# Autogenerated file; please don't edit
# date: 2023-12-21 15:24:16.315777

VERSION 5.8 ;

SITE IOLibSite
  CLASS PAD ;
  SYMMETRY R90 ;
  SIZE 1.00 BY 180.00 ;
END IOLibSite

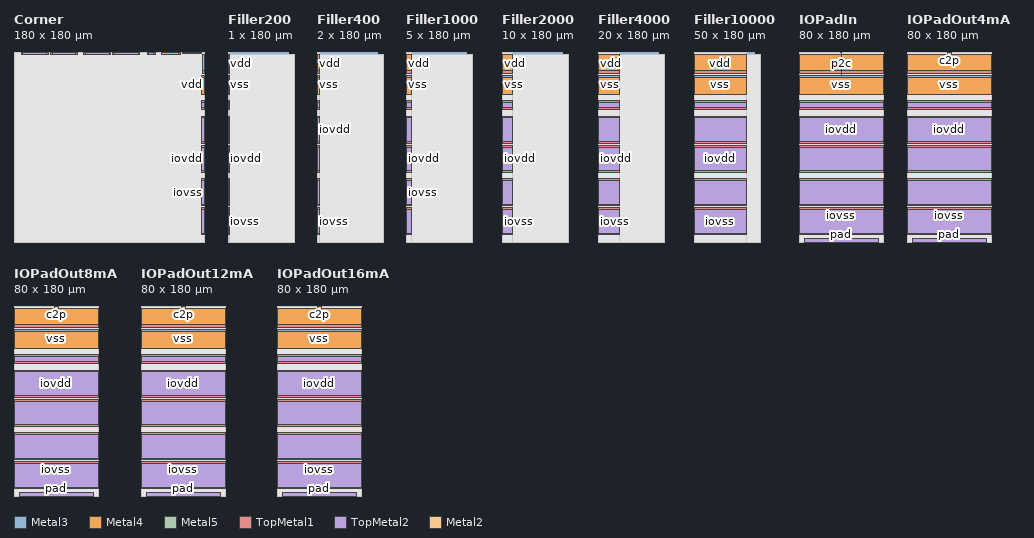
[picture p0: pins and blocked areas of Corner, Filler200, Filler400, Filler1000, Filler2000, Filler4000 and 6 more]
MACRO Corner
  CLASS PAD SPACER ;
  ORIGIN 180.000 0.000 ;
  FOREIGN Corner -180.000 0.000 ;
  SIZE 180.000 BY 180.000 ;
  SYMMETRY X Y R90 ;
  SITE IOLibSite ;
  PIN iovdd
    DIRECTION INOUT ;
    USE POWER ;
    PORT
      LAYER Metal3 ;
        RECT -2.000 66.000 0.000 91.500 ;
    END
    PORT
      LAYER Metal3 ;
        RECT -86.500 178.000 -61.000 180.000 ;
    END
    PORT
      LAYER Metal3 ;
        RECT -114.000 178.000 -88.500 180.000 ;
    END
    PORT
      LAYER Metal3 ;
        RECT -2.000 93.500 0.000 119.000 ;
    END
    PORT
      LAYER Metal4 ;
        RECT -2.000 66.000 0.000 91.500 ;
    END
    PORT
      LAYER Metal4 ;
        RECT -86.500 178.000 -61.000 180.000 ;
    END
    PORT
      LAYER Metal4 ;
        RECT -114.000 178.000 -88.500 180.000 ;
    END
    PORT
      LAYER Metal4 ;
        RECT -2.000 93.500 0.000 119.000 ;
    END
    PORT
      LAYER Metal5 ;
        RECT -2.000 66.000 0.000 91.500 ;
    END
    PORT
      LAYER Metal5 ;
        RECT -86.500 178.000 -61.000 180.000 ;
    END
    PORT
      LAYER Metal5 ;
        RECT -114.000 178.000 -88.500 180.000 ;
    END
    PORT
      LAYER Metal5 ;
        RECT -2.000 93.500 0.000 119.000 ;
    END
    PORT
      LAYER TopMetal1 ;
        RECT -2.000 66.000 0.000 91.500 ;
    END
    PORT
      LAYER TopMetal1 ;
        RECT -86.500 178.000 -61.000 180.000 ;
    END
    PORT
      LAYER TopMetal1 ;
        RECT -114.000 178.000 -88.500 180.000 ;
    END
    PORT
      LAYER TopMetal1 ;
        RECT -2.000 93.500 0.000 119.000 ;
    END
    PORT
      LAYER TopMetal2 ;
        RECT -112.500 178.000 -90.000 180.000 ;
    END
    PORT
      LAYER TopMetal2 ;
        RECT -2.000 67.500 0.000 90.000 ;
    END
    PORT
      LAYER TopMetal2 ;
        RECT -85.000 178.000 -62.500 180.000 ;
    END
    PORT
      LAYER TopMetal2 ;
        RECT -2.000 95.000 0.000 117.500 ;
    END
  END iovdd
  PIN iovss
    DIRECTION INOUT ;
    USE GROUND ;
    PORT
      LAYER Metal3 ;
        RECT -2.000 34.500 0.000 60.000 ;
    END
    PORT
      LAYER Metal3 ;
        RECT -173.000 178.000 -147.500 180.000 ;
    END
    PORT
      LAYER Metal3 ;
        RECT -2.000 126.000 0.000 134.000 ;
    END
    PORT
      LAYER Metal3 ;
        RECT -54.000 178.000 -46.000 180.000 ;
    END
    PORT
      LAYER Metal3 ;
        RECT -145.500 178.000 -120.000 180.000 ;
    END
    PORT
      LAYER Metal3 ;
        RECT -2.000 7.000 0.000 32.500 ;
    END
    PORT
      LAYER Metal4 ;
        RECT -2.000 34.500 0.000 60.000 ;
    END
    PORT
      LAYER Metal4 ;
        RECT -173.000 178.000 -147.500 180.000 ;
    END
    PORT
      LAYER Metal4 ;
        RECT -2.000 126.000 0.000 134.000 ;
    END
    PORT
      LAYER Metal4 ;
        RECT -54.000 178.000 -46.000 180.000 ;
    END
    PORT
      LAYER Metal4 ;
        RECT -145.500 178.000 -120.000 180.000 ;
    END
    PORT
      LAYER Metal4 ;
        RECT -2.000 7.000 0.000 32.500 ;
    END
    PORT
      LAYER Metal5 ;
        RECT -2.000 34.500 0.000 60.000 ;
    END
    PORT
      LAYER Metal5 ;
        RECT -173.000 178.000 -147.500 180.000 ;
    END
    PORT
      LAYER Metal5 ;
        RECT -2.000 126.000 0.000 134.000 ;
    END
    PORT
      LAYER Metal5 ;
        RECT -54.000 178.000 -46.000 180.000 ;
    END
    PORT
      LAYER Metal5 ;
        RECT -145.500 178.000 -120.000 180.000 ;
    END
    PORT
      LAYER Metal5 ;
        RECT -2.000 7.000 0.000 32.500 ;
    END
    PORT
      LAYER TopMetal1 ;
        RECT -2.000 34.500 0.000 60.000 ;
    END
    PORT
      LAYER TopMetal1 ;
        RECT -173.000 178.000 -147.500 180.000 ;
    END
    PORT
      LAYER TopMetal1 ;
        RECT -2.000 126.000 0.000 134.000 ;
    END
    PORT
      LAYER TopMetal1 ;
        RECT -54.000 178.000 -46.000 180.000 ;
    END
    PORT
      LAYER TopMetal1 ;
        RECT -145.500 178.000 -120.000 180.000 ;
    END
    PORT
      LAYER TopMetal1 ;
        RECT -2.000 7.000 0.000 32.500 ;
    END
    PORT
      LAYER TopMetal2 ;
        RECT -2.000 127.500 0.000 132.500 ;
    END
    PORT
      LAYER TopMetal2 ;
        RECT -2.000 36.000 0.000 58.500 ;
    END
    PORT
      LAYER TopMetal2 ;
        RECT -171.500 178.000 -149.000 180.000 ;
    END
    PORT
      LAYER TopMetal2 ;
        RECT -2.000 8.500 0.000 31.000 ;
    END
    PORT
      LAYER TopMetal2 ;
        RECT -144.000 178.000 -121.500 180.000 ;
    END
    PORT
      LAYER TopMetal2 ;
        RECT -52.500 178.000 -47.500 180.000 ;
    END
  END iovss
  PIN vdd
    DIRECTION INOUT ;
    USE POWER ;
    PORT
      LAYER Metal3 ;
        RECT -20.000 178.590 -2.000 180.000 ;
    END
    PORT
      LAYER Metal3 ;
        RECT -1.410 160.000 0.000 178.000 ;
    END
    PORT
      LAYER Metal4 ;
        RECT -2.000 140.000 0.000 155.800 ;
    END
    PORT
      LAYER Metal4 ;
        RECT -40.000 178.000 -24.200 180.000 ;
    END
    PORT
      LAYER Metal5 ;
        RECT -2.000 140.000 0.000 158.000 ;
    END
    PORT
      LAYER Metal5 ;
        RECT -40.000 178.000 -22.000 180.000 ;
    END
    PORT
      LAYER TopMetal1 ;
        RECT -2.000 140.000 0.000 158.000 ;
    END
    PORT
      LAYER TopMetal1 ;
        RECT -40.000 178.000 -22.000 180.000 ;
    END
  END vdd
  PIN vss
    DIRECTION INOUT ;
    USE GROUND ;
    PORT
      LAYER Metal3 ;
        RECT -2.000 140.000 0.000 158.000 ;
    END
    PORT
      LAYER Metal3 ;
        RECT -40.000 178.000 -22.000 180.000 ;
    END
    PORT
      LAYER Metal4 ;
        RECT -1.410 162.200 0.000 178.000 ;
    END
    PORT
      LAYER Metal4 ;
        RECT -17.800 178.590 -2.000 180.000 ;
    END
    PORT
      LAYER Metal5 ;
        RECT -20.000 178.590 -2.000 180.000 ;
    END
    PORT
      LAYER Metal5 ;
        RECT -1.410 160.000 0.000 178.000 ;
    END
    PORT
      LAYER TopMetal1 ;
        RECT -20.000 178.590 -2.000 180.000 ;
    END
    PORT
      LAYER TopMetal1 ;
        RECT -1.410 160.000 0.000 178.000 ;
    END
  END vss
  OBS
    LAYER Metal1 ;
      RECT -180.000 0.000 0.000 180.000 ;
    LAYER Metal2 ;
      RECT -180.000 0.000 0.000 180.000 ;
    LAYER Metal3 ;
      RECT -180.000 0.000 0.000 180.000 ;
    LAYER Metal4 ;
      RECT -180.000 0.000 0.000 180.000 ;
    LAYER Metal5 ;
      RECT -180.000 0.000 0.000 180.000 ;
    LAYER TopMetal1 ;
      RECT -180.000 0.000 0.000 180.000 ;
    LAYER TopMetal2 ;
      RECT -180.000 0.000 0.000 180.000 ;
    LAYER Via1 ;
      RECT -180.000 0.000 0.000 180.000 ;
    LAYER Via2 ;
      RECT -180.000 0.000 0.000 180.000 ;
  END
END Corner

MACRO Filler200
  CLASS PAD SPACER ;
  ORIGIN 0.000 0.000 ;
  FOREIGN Filler200 0.000 0.000 ;
  SIZE 1.000 BY 180.000 ;
  SYMMETRY X Y R90 ;
  SITE IOLibSite ;
  PIN iovdd
    DIRECTION INOUT ;
    USE POWER ;
    PORT
      LAYER Metal3 ;
        RECT 0.000 66.000 1.000 91.500 ;
    END
    PORT
      LAYER Metal3 ;
        RECT 0.000 93.500 1.000 119.000 ;
    END
    PORT
      LAYER Metal4 ;
        RECT 0.000 66.000 1.000 91.500 ;
    END
    PORT
      LAYER Metal4 ;
        RECT 0.000 93.500 1.000 119.000 ;
    END
    PORT
      LAYER Metal5 ;
        RECT 0.000 66.000 1.000 91.500 ;
    END
    PORT
      LAYER Metal5 ;
        RECT 0.000 93.500 1.000 119.000 ;
    END
    PORT
      LAYER TopMetal1 ;
        RECT 0.000 66.000 1.000 91.500 ;
    END
    PORT
      LAYER TopMetal1 ;
        RECT 0.000 93.500 1.000 119.000 ;
    END
    PORT
      LAYER TopMetal2 ;
        RECT 0.000 95.000 1.000 117.500 ;
    END
    PORT
      LAYER TopMetal2 ;
        RECT 0.000 67.500 1.000 90.000 ;
    END
  END iovdd
  PIN iovss
    DIRECTION INOUT ;
    USE GROUND ;
    PORT
      LAYER Metal3 ;
        RECT 0.000 7.000 1.000 32.500 ;
    END
    PORT
      LAYER Metal3 ;
        RECT 0.000 126.000 1.000 134.000 ;
    END
    PORT
      LAYER Metal3 ;
        RECT 0.000 34.500 1.000 60.000 ;
    END
    PORT
      LAYER Metal4 ;
        RECT 0.000 7.000 1.000 32.500 ;
    END
    PORT
      LAYER Metal4 ;
        RECT 0.000 126.000 1.000 134.000 ;
    END
    PORT
      LAYER Metal4 ;
        RECT 0.000 34.500 1.000 60.000 ;
    END
    PORT
      LAYER Metal5 ;
        RECT 0.000 7.000 1.000 32.500 ;
    END
    PORT
      LAYER Metal5 ;
        RECT 0.000 126.000 1.000 134.000 ;
    END
    PORT
      LAYER Metal5 ;
        RECT 0.000 34.500 1.000 60.000 ;
    END
    PORT
      LAYER TopMetal1 ;
        RECT 0.000 7.000 1.000 32.500 ;
    END
    PORT
      LAYER TopMetal1 ;
        RECT 0.000 126.000 1.000 134.000 ;
    END
    PORT
      LAYER TopMetal1 ;
        RECT 0.000 34.500 1.000 60.000 ;
    END
    PORT
      LAYER TopMetal2 ;
        RECT 0.000 8.500 1.000 31.000 ;
    END
    PORT
      LAYER TopMetal2 ;
        RECT 0.000 127.500 1.000 132.500 ;
    END
    PORT
      LAYER TopMetal2 ;
        RECT 0.000 36.000 1.000 58.500 ;
    END
  END iovss
  PIN vdd
    DIRECTION INOUT ;
    USE POWER ;
    PORT
      LAYER Metal3 ;
        RECT 0.000 160.000 1.000 178.000 ;
    END
    PORT
      LAYER Metal4 ;
        RECT 0.000 140.000 1.000 155.800 ;
    END
    PORT
      LAYER Metal5 ;
        RECT 0.000 140.000 1.000 158.000 ;
    END
    PORT
      LAYER TopMetal1 ;
        RECT 0.000 140.000 1.000 158.000 ;
    END
  END vdd
  PIN vss
    DIRECTION INOUT ;
    USE GROUND ;
    PORT
      LAYER Metal3 ;
        RECT 0.000 140.000 1.000 158.000 ;
    END
    PORT
      LAYER Metal4 ;
        RECT 0.000 162.200 1.000 178.000 ;
    END
    PORT
      LAYER Metal5 ;
        RECT 0.000 160.000 1.000 178.000 ;
    END
    PORT
      LAYER TopMetal1 ;
        RECT 0.000 160.000 1.000 178.000 ;
    END
  END vss
  OBS
    LAYER Metal1 ;
      RECT 0.000 0.000 1.000 180.000 ;
    LAYER Metal2 ;
      RECT 0.000 0.000 1.000 180.000 ;
    LAYER Metal3 ;
      RECT 0.000 0.000 80.000 178.000 ;
    LAYER Metal4 ;
      RECT 0.000 0.000 80.000 178.000 ;
    LAYER Metal5 ;
      RECT 0.000 0.000 80.000 178.000 ;
    LAYER TopMetal1 ;
      RECT 0.000 0.000 80.000 178.000 ;
    LAYER TopMetal2 ;
      RECT 0.000 8.500 1.000 132.500 ;
    LAYER Via1 ;
      RECT 0.000 0.000 1.000 180.000 ;
    LAYER Via2 ;
      RECT 0.000 0.000 1.000 180.000 ;
  END
END Filler200

MACRO Filler400
  CLASS PAD SPACER ;
  ORIGIN 0.000 0.000 ;
  FOREIGN Filler400 0.000 0.000 ;
  SIZE 2.000 BY 180.000 ;
  SYMMETRY X Y R90 ;
  SITE IOLibSite ;
  PIN iovdd
    DIRECTION INOUT ;
    USE POWER ;
    PORT
      LAYER Metal3 ;
        RECT 0.000 93.500 2.000 119.000 ;
    END
    PORT
      LAYER Metal3 ;
        RECT 0.000 66.000 2.000 91.500 ;
    END
    PORT
      LAYER Metal4 ;
        RECT 0.000 93.500 2.000 119.000 ;
    END
    PORT
      LAYER Metal4 ;
        RECT 0.000 66.000 2.000 91.500 ;
    END
    PORT
      LAYER Metal5 ;
        RECT 0.000 93.500 2.000 119.000 ;
    END
    PORT
      LAYER Metal5 ;
        RECT 0.000 66.000 2.000 91.500 ;
    END
    PORT
      LAYER TopMetal1 ;
        RECT 0.000 93.500 2.000 119.000 ;
    END
    PORT
      LAYER TopMetal1 ;
        RECT 0.000 66.000 2.000 91.500 ;
    END
    PORT
      LAYER TopMetal2 ;
        RECT 0.000 67.500 2.000 90.000 ;
    END
    PORT
      LAYER TopMetal2 ;
        RECT 0.000 95.000 2.000 117.500 ;
    END
  END iovdd
  PIN iovss
    DIRECTION INOUT ;
    USE GROUND ;
    PORT
      LAYER Metal3 ;
        RECT 0.000 126.000 2.000 134.000 ;
    END
    PORT
      LAYER Metal3 ;
        RECT 0.000 7.000 2.000 32.500 ;
    END
    PORT
      LAYER Metal3 ;
        RECT 0.000 34.500 2.000 60.000 ;
    END
    PORT
      LAYER Metal4 ;
        RECT 0.000 126.000 2.000 134.000 ;
    END
    PORT
      LAYER Metal4 ;
        RECT 0.000 7.000 2.000 32.500 ;
    END
    PORT
      LAYER Metal4 ;
        RECT 0.000 34.500 2.000 60.000 ;
    END
    PORT
      LAYER Metal5 ;
        RECT 0.000 126.000 2.000 134.000 ;
    END
    PORT
      LAYER Metal5 ;
        RECT 0.000 7.000 2.000 32.500 ;
    END
    PORT
      LAYER Metal5 ;
        RECT 0.000 34.500 2.000 60.000 ;
    END
    PORT
      LAYER TopMetal1 ;
        RECT 0.000 126.000 2.000 134.000 ;
    END
    PORT
      LAYER TopMetal1 ;
        RECT 0.000 7.000 2.000 32.500 ;
    END
    PORT
      LAYER TopMetal1 ;
        RECT 0.000 34.500 2.000 60.000 ;
    END
    PORT
      LAYER TopMetal2 ;
        RECT 0.000 8.500 2.000 31.000 ;
    END
    PORT
      LAYER TopMetal2 ;
        RECT 0.000 36.000 2.000 58.500 ;
    END
    PORT
      LAYER TopMetal2 ;
        RECT 0.000 127.500 2.000 132.500 ;
    END
  END iovss
  PIN vdd
    DIRECTION INOUT ;
    USE POWER ;
    PORT
      LAYER Metal3 ;
        RECT 0.000 160.000 2.000 178.000 ;
    END
    PORT
      LAYER Metal4 ;
        RECT 0.000 140.000 2.000 155.800 ;
    END
    PORT
      LAYER Metal5 ;
        RECT 0.000 140.000 2.000 158.000 ;
    END
    PORT
      LAYER TopMetal1 ;
        RECT 0.000 140.000 2.000 158.000 ;
    END
  END vdd
  PIN vss
    DIRECTION INOUT ;
    USE GROUND ;
    PORT
      LAYER Metal3 ;
        RECT 0.000 140.000 2.000 158.000 ;
    END
    PORT
      LAYER Metal4 ;
        RECT 0.000 162.200 2.000 178.000 ;
    END
    PORT
      LAYER Metal5 ;
        RECT 0.000 160.000 2.000 178.000 ;
    END
    PORT
      LAYER TopMetal1 ;
        RECT 0.000 160.000 2.000 178.000 ;
    END
  END vss
  OBS
    LAYER Metal1 ;
      RECT 0.000 0.000 2.000 180.000 ;
    LAYER Metal2 ;
      RECT 0.000 0.000 2.000 180.000 ;
    LAYER Metal3 ;
      RECT 0.000 0.000 80.000 178.000 ;
    LAYER Metal4 ;
      RECT 0.000 0.000 80.000 178.000 ;
    LAYER Metal5 ;
      RECT 0.000 0.000 80.000 178.000 ;
    LAYER TopMetal1 ;
      RECT 0.000 0.000 80.000 178.000 ;
    LAYER TopMetal2 ;
      RECT 0.000 8.500 2.000 132.500 ;
    LAYER Via1 ;
      RECT 0.000 0.000 2.000 180.000 ;
    LAYER Via2 ;
      RECT 0.000 0.000 2.000 180.000 ;
  END
END Filler400

MACRO Filler1000
  CLASS PAD SPACER ;
  ORIGIN 0.000 0.000 ;
  FOREIGN Filler1000 0.000 0.000 ;
  SIZE 5.000 BY 180.000 ;
  SYMMETRY X Y R90 ;
  SITE IOLibSite ;
  PIN iovdd
    DIRECTION INOUT ;
    USE POWER ;
    PORT
      LAYER Metal3 ;
        RECT 0.000 66.000 5.000 91.500 ;
    END
    PORT
      LAYER Metal3 ;
        RECT 0.000 93.500 5.000 119.000 ;
    END
    PORT
      LAYER Metal4 ;
        RECT 0.000 66.000 5.000 91.500 ;
    END
    PORT
      LAYER Metal4 ;
        RECT 0.000 93.500 5.000 119.000 ;
    END
    PORT
      LAYER Metal5 ;
        RECT 0.000 66.000 5.000 91.500 ;
    END
    PORT
      LAYER Metal5 ;
        RECT 0.000 93.500 5.000 119.000 ;
    END
    PORT
      LAYER TopMetal1 ;
        RECT 0.000 66.000 5.000 91.500 ;
    END
    PORT
      LAYER TopMetal1 ;
        RECT 0.000 93.500 5.000 119.000 ;
    END
    PORT
      LAYER TopMetal2 ;
        RECT 0.000 95.000 5.000 117.500 ;
    END
    PORT
      LAYER TopMetal2 ;
        RECT 0.000 67.500 5.000 90.000 ;
    END
  END iovdd
  PIN iovss
    DIRECTION INOUT ;
    USE GROUND ;
    PORT
      LAYER Metal3 ;
        RECT 0.000 34.500 5.000 60.000 ;
    END
    PORT
      LAYER Metal3 ;
        RECT 0.000 7.000 5.000 32.500 ;
    END
    PORT
      LAYER Metal3 ;
        RECT 0.000 126.000 5.000 134.000 ;
    END
    PORT
      LAYER Metal4 ;
        RECT 0.000 34.500 5.000 60.000 ;
    END
    PORT
      LAYER Metal4 ;
        RECT 0.000 7.000 5.000 32.500 ;
    END
    PORT
      LAYER Metal4 ;
        RECT 0.000 126.000 5.000 134.000 ;
    END
    PORT
      LAYER Metal5 ;
        RECT 0.000 34.500 5.000 60.000 ;
    END
    PORT
      LAYER Metal5 ;
        RECT 0.000 7.000 5.000 32.500 ;
    END
    PORT
      LAYER Metal5 ;
        RECT 0.000 126.000 5.000 134.000 ;
    END
    PORT
      LAYER TopMetal1 ;
        RECT 0.000 34.500 5.000 60.000 ;
    END
    PORT
      LAYER TopMetal1 ;
        RECT 0.000 7.000 5.000 32.500 ;
    END
    PORT
      LAYER TopMetal1 ;
        RECT 0.000 126.000 5.000 134.000 ;
    END
    PORT
      LAYER TopMetal2 ;
        RECT 0.000 127.500 5.000 132.500 ;
    END
    PORT
      LAYER TopMetal2 ;
        RECT 0.000 36.000 5.000 58.500 ;
    END
    PORT
      LAYER TopMetal2 ;
        RECT 0.000 8.500 5.000 31.000 ;
    END
  END iovss
  PIN vdd
    DIRECTION INOUT ;
    USE POWER ;
    PORT
      LAYER Metal3 ;
        RECT 0.000 160.000 5.000 178.000 ;
    END
    PORT
      LAYER Metal4 ;
        RECT 0.000 140.000 5.000 155.800 ;
    END
    PORT
      LAYER Metal5 ;
        RECT 0.000 140.000 5.000 158.000 ;
    END
    PORT
      LAYER TopMetal1 ;
        RECT 0.000 140.000 5.000 158.000 ;
    END
  END vdd
  PIN vss
    DIRECTION INOUT ;
    USE GROUND ;
    PORT
      LAYER Metal3 ;
        RECT 0.000 140.000 5.000 158.000 ;
    END
    PORT
      LAYER Metal4 ;
        RECT 0.000 162.200 5.000 178.000 ;
    END
    PORT
      LAYER Metal5 ;
        RECT 0.000 160.000 5.000 178.000 ;
    END
    PORT
      LAYER TopMetal1 ;
        RECT 0.000 160.000 5.000 178.000 ;
    END
  END vss
  OBS
    LAYER Metal1 ;
      RECT 0.000 0.000 5.000 180.000 ;
    LAYER Metal2 ;
      RECT 0.000 0.000 5.000 180.000 ;
    LAYER Metal3 ;
      RECT 0.000 0.000 80.000 178.000 ;
    LAYER Metal4 ;
      RECT 0.000 0.000 80.000 178.000 ;
    LAYER Metal5 ;
      RECT 0.000 0.000 80.000 178.000 ;
    LAYER TopMetal1 ;
      RECT 0.000 0.000 80.000 178.000 ;
    LAYER TopMetal2 ;
      RECT 0.000 8.500 5.000 132.500 ;
    LAYER Via1 ;
      RECT 0.000 0.000 5.000 180.000 ;
    LAYER Via2 ;
      RECT 0.000 0.000 5.000 180.000 ;
  END
END Filler1000

MACRO Filler2000
  CLASS PAD SPACER ;
  ORIGIN 0.000 0.000 ;
  FOREIGN Filler2000 0.000 0.000 ;
  SIZE 10.000 BY 180.000 ;
  SYMMETRY X Y R90 ;
  SITE IOLibSite ;
  PIN iovdd
    DIRECTION INOUT ;
    USE POWER ;
    PORT
      LAYER Metal3 ;
        RECT 0.000 66.000 10.000 91.500 ;
    END
    PORT
      LAYER Metal3 ;
        RECT 0.000 93.500 10.000 119.000 ;
    END
    PORT
      LAYER Metal4 ;
        RECT 0.000 66.000 10.000 91.500 ;
    END
    PORT
      LAYER Metal4 ;
        RECT 0.000 93.500 10.000 119.000 ;
    END
    PORT
      LAYER Metal5 ;
        RECT 0.000 66.000 10.000 91.500 ;
    END
    PORT
      LAYER Metal5 ;
        RECT 0.000 93.500 10.000 119.000 ;
    END
    PORT
      LAYER TopMetal1 ;
        RECT 0.000 66.000 10.000 91.500 ;
    END
    PORT
      LAYER TopMetal1 ;
        RECT 0.000 93.500 10.000 119.000 ;
    END
    PORT
      LAYER TopMetal2 ;
        RECT 0.000 67.500 10.000 90.000 ;
    END
    PORT
      LAYER TopMetal2 ;
        RECT 0.000 95.000 10.000 117.500 ;
    END
  END iovdd
  PIN iovss
    DIRECTION INOUT ;
    USE GROUND ;
    PORT
      LAYER Metal3 ;
        RECT 0.000 126.000 10.000 134.000 ;
    END
    PORT
      LAYER Metal3 ;
        RECT 0.000 7.000 10.000 32.500 ;
    END
    PORT
      LAYER Metal3 ;
        RECT 0.000 34.500 10.000 60.000 ;
    END
    PORT
      LAYER Metal4 ;
        RECT 0.000 126.000 10.000 134.000 ;
    END
    PORT
      LAYER Metal4 ;
        RECT 0.000 7.000 10.000 32.500 ;
    END
    PORT
      LAYER Metal4 ;
        RECT 0.000 34.500 10.000 60.000 ;
    END
    PORT
      LAYER Metal5 ;
        RECT 0.000 126.000 10.000 134.000 ;
    END
    PORT
      LAYER Metal5 ;
        RECT 0.000 7.000 10.000 32.500 ;
    END
    PORT
      LAYER Metal5 ;
        RECT 0.000 34.500 10.000 60.000 ;
    END
    PORT
      LAYER TopMetal1 ;
        RECT 0.000 126.000 10.000 134.000 ;
    END
    PORT
      LAYER TopMetal1 ;
        RECT 0.000 7.000 10.000 32.500 ;
    END
    PORT
      LAYER TopMetal1 ;
        RECT 0.000 34.500 10.000 60.000 ;
    END
    PORT
      LAYER TopMetal2 ;
        RECT 0.000 8.500 10.000 31.000 ;
    END
    PORT
      LAYER TopMetal2 ;
        RECT 0.000 36.000 10.000 58.500 ;
    END
    PORT
      LAYER TopMetal2 ;
        RECT 0.000 127.500 10.000 132.500 ;
    END
  END iovss
  PIN vdd
    DIRECTION INOUT ;
    USE POWER ;
    PORT
      LAYER Metal3 ;
        RECT 0.000 160.000 10.000 178.000 ;
    END
    PORT
      LAYER Metal4 ;
        RECT 0.000 140.000 10.000 155.800 ;
    END
    PORT
      LAYER Metal5 ;
        RECT 0.000 140.000 10.000 158.000 ;
    END
    PORT
      LAYER TopMetal1 ;
        RECT 0.000 140.000 10.000 158.000 ;
    END
  END vdd
  PIN vss
    DIRECTION INOUT ;
    USE GROUND ;
    PORT
      LAYER Metal3 ;
        RECT 0.000 140.000 10.000 158.000 ;
    END
    PORT
      LAYER Metal4 ;
        RECT 0.000 162.200 10.000 178.000 ;
    END
    PORT
      LAYER Metal5 ;
        RECT 0.000 160.000 10.000 178.000 ;
    END
    PORT
      LAYER TopMetal1 ;
        RECT 0.000 160.000 10.000 178.000 ;
    END
  END vss
  OBS
    LAYER Metal1 ;
      RECT 0.000 0.000 10.000 180.000 ;
    LAYER Metal2 ;
      RECT 0.000 0.000 10.000 180.000 ;
    LAYER Metal3 ;
      RECT 0.000 0.000 80.000 178.000 ;
    LAYER Metal4 ;
      RECT 0.000 0.000 80.000 178.000 ;
    LAYER Metal5 ;
      RECT 0.000 0.000 80.000 178.000 ;
    LAYER TopMetal1 ;
      RECT 0.000 0.000 80.000 178.000 ;
    LAYER TopMetal2 ;
      RECT 0.000 8.500 10.000 132.500 ;
    LAYER Via1 ;
      RECT 0.000 0.000 10.000 180.000 ;
    LAYER Via2 ;
      RECT 0.000 0.000 10.000 180.000 ;
  END
END Filler2000

MACRO Filler4000
  CLASS PAD SPACER ;
  ORIGIN 0.000 0.000 ;
  FOREIGN Filler4000 0.000 0.000 ;
  SIZE 20.000 BY 180.000 ;
  SYMMETRY X Y R90 ;
  SITE IOLibSite ;
  PIN iovdd
    DIRECTION INOUT ;
    USE POWER ;
    PORT
      LAYER Metal3 ;
        RECT 0.000 66.000 20.000 91.500 ;
    END
    PORT
      LAYER Metal3 ;
        RECT 0.000 93.500 20.000 119.000 ;
    END
    PORT
      LAYER Metal4 ;
        RECT 0.000 66.000 20.000 91.500 ;
    END
    PORT
      LAYER Metal4 ;
        RECT 0.000 93.500 20.000 119.000 ;
    END
    PORT
      LAYER Metal5 ;
        RECT 0.000 66.000 20.000 91.500 ;
    END
    PORT
      LAYER Metal5 ;
        RECT 0.000 93.500 20.000 119.000 ;
    END
    PORT
      LAYER TopMetal1 ;
        RECT 0.000 66.000 20.000 91.500 ;
    END
    PORT
      LAYER TopMetal1 ;
        RECT 0.000 93.500 20.000 119.000 ;
    END
    PORT
      LAYER TopMetal2 ;
        RECT 0.000 95.000 20.000 117.500 ;
    END
    PORT
      LAYER TopMetal2 ;
        RECT 0.000 67.500 20.000 90.000 ;
    END
  END iovdd
  PIN iovss
    DIRECTION INOUT ;
    USE GROUND ;
    PORT
      LAYER Metal3 ;
        RECT 0.000 7.000 20.000 32.500 ;
    END
    PORT
      LAYER Metal3 ;
        RECT 0.000 34.500 20.000 60.000 ;
    END
    PORT
      LAYER Metal3 ;
        RECT 0.000 126.000 20.000 134.000 ;
    END
    PORT
      LAYER Metal4 ;
        RECT 0.000 7.000 20.000 32.500 ;
    END
    PORT
      LAYER Metal4 ;
        RECT 0.000 34.500 20.000 60.000 ;
    END
    PORT
      LAYER Metal4 ;
        RECT 0.000 126.000 20.000 134.000 ;
    END
    PORT
      LAYER Metal5 ;
        RECT 0.000 7.000 20.000 32.500 ;
    END
    PORT
      LAYER Metal5 ;
        RECT 0.000 34.500 20.000 60.000 ;
    END
    PORT
      LAYER Metal5 ;
        RECT 0.000 126.000 20.000 134.000 ;
    END
    PORT
      LAYER TopMetal1 ;
        RECT 0.000 7.000 20.000 32.500 ;
    END
    PORT
      LAYER TopMetal1 ;
        RECT 0.000 34.500 20.000 60.000 ;
    END
    PORT
      LAYER TopMetal1 ;
        RECT 0.000 126.000 20.000 134.000 ;
    END
    PORT
      LAYER TopMetal2 ;
        RECT 0.000 127.500 20.000 132.500 ;
    END
    PORT
      LAYER TopMetal2 ;
        RECT 0.000 36.000 20.000 58.500 ;
    END
    PORT
      LAYER TopMetal2 ;
        RECT 0.000 8.500 20.000 31.000 ;
    END
  END iovss
  PIN vdd
    DIRECTION INOUT ;
    USE POWER ;
    PORT
      LAYER Metal3 ;
        RECT 0.000 160.000 20.000 178.000 ;
    END
    PORT
      LAYER Metal4 ;
        RECT 0.000 140.000 20.000 155.800 ;
    END
    PORT
      LAYER Metal5 ;
        RECT 0.000 140.000 20.000 158.000 ;
    END
    PORT
      LAYER TopMetal1 ;
        RECT 0.000 140.000 20.000 158.000 ;
    END
  END vdd
  PIN vss
    DIRECTION INOUT ;
    USE GROUND ;
    PORT
      LAYER Metal3 ;
        RECT 0.000 140.000 20.000 158.000 ;
    END
    PORT
      LAYER Metal4 ;
        RECT 0.000 162.200 20.000 178.000 ;
    END
    PORT
      LAYER Metal5 ;
        RECT 0.000 160.000 20.000 178.000 ;
    END
    PORT
      LAYER TopMetal1 ;
        RECT 0.000 160.000 20.000 178.000 ;
    END
  END vss
  OBS
    LAYER Metal1 ;
      RECT 0.000 0.000 20.000 180.000 ;
    LAYER Metal2 ;
      RECT 0.000 0.000 20.000 180.000 ;
    LAYER Metal3 ;
      RECT 0.000 0.000 80.000 178.000 ;
    LAYER Metal4 ;
      RECT 0.000 0.000 80.000 178.000 ;
    LAYER Metal5 ;
      RECT 0.000 0.000 80.000 178.000 ;
    LAYER TopMetal1 ;
      RECT 0.000 0.000 80.000 178.000 ;
    LAYER TopMetal2 ;
      RECT 0.000 8.500 20.000 132.500 ;
    LAYER Via1 ;
      RECT 0.000 0.000 20.000 180.000 ;
    LAYER Via2 ;
      RECT 0.000 0.000 20.000 180.000 ;
  END
END Filler4000

MACRO Filler10000
  CLASS PAD SPACER ;
  ORIGIN 0.000 0.000 ;
  FOREIGN Filler10000 0.000 0.000 ;
  SIZE 50.000 BY 180.000 ;
  SYMMETRY X Y R90 ;
  SITE IOLibSite ;
  PIN iovdd
    DIRECTION INOUT ;
    USE POWER ;
    PORT
      LAYER Metal3 ;
        RECT 0.000 66.000 50.000 91.500 ;
    END
    PORT
      LAYER Metal3 ;
        RECT 0.000 93.500 50.000 119.000 ;
    END
    PORT
      LAYER Metal4 ;
        RECT 0.000 66.000 50.000 91.500 ;
    END
    PORT
      LAYER Metal4 ;
        RECT 0.000 93.500 50.000 119.000 ;
    END
    PORT
      LAYER Metal5 ;
        RECT 0.000 66.000 50.000 91.500 ;
    END
    PORT
      LAYER Metal5 ;
        RECT 0.000 93.500 50.000 119.000 ;
    END
    PORT
      LAYER TopMetal1 ;
        RECT 0.000 66.000 50.000 91.500 ;
    END
    PORT
      LAYER TopMetal1 ;
        RECT 0.000 93.500 50.000 119.000 ;
    END
    PORT
      LAYER TopMetal2 ;
        RECT 0.000 95.000 50.000 117.500 ;
    END
    PORT
      LAYER TopMetal2 ;
        RECT 0.000 67.500 50.000 90.000 ;
    END
  END iovdd
  PIN iovss
    DIRECTION INOUT ;
    USE GROUND ;
    PORT
      LAYER Metal3 ;
        RECT 0.000 7.000 50.000 32.500 ;
    END
    PORT
      LAYER Metal3 ;
        RECT 0.000 126.000 50.000 134.000 ;
    END
    PORT
      LAYER Metal3 ;
        RECT 0.000 34.500 50.000 60.000 ;
    END
    PORT
      LAYER Metal4 ;
        RECT 0.000 7.000 50.000 32.500 ;
    END
    PORT
      LAYER Metal4 ;
        RECT 0.000 126.000 50.000 134.000 ;
    END
    PORT
      LAYER Metal4 ;
        RECT 0.000 34.500 50.000 60.000 ;
    END
    PORT
      LAYER Metal5 ;
        RECT 0.000 7.000 50.000 32.500 ;
    END
    PORT
      LAYER Metal5 ;
        RECT 0.000 126.000 50.000 134.000 ;
    END
    PORT
      LAYER Metal5 ;
        RECT 0.000 34.500 50.000 60.000 ;
    END
    PORT
      LAYER TopMetal1 ;
        RECT 0.000 7.000 50.000 32.500 ;
    END
    PORT
      LAYER TopMetal1 ;
        RECT 0.000 126.000 50.000 134.000 ;
    END
    PORT
      LAYER TopMetal1 ;
        RECT 0.000 34.500 50.000 60.000 ;
    END
    PORT
      LAYER TopMetal2 ;
        RECT 0.000 8.500 50.000 31.000 ;
    END
    PORT
      LAYER TopMetal2 ;
        RECT 0.000 127.500 50.000 132.500 ;
    END
    PORT
      LAYER TopMetal2 ;
        RECT 0.000 36.000 50.000 58.500 ;
    END
  END iovss
  PIN vdd
    DIRECTION INOUT ;
    USE POWER ;
    PORT
      LAYER Metal3 ;
        RECT 0.000 160.000 50.000 178.000 ;
    END
    PORT
      LAYER Metal4 ;
        RECT 0.000 140.000 50.000 155.800 ;
    END
    PORT
      LAYER Metal5 ;
        RECT 0.000 140.000 50.000 158.000 ;
    END
    PORT
      LAYER TopMetal1 ;
        RECT 0.000 140.000 50.000 158.000 ;
    END
  END vdd
  PIN vss
    DIRECTION INOUT ;
    USE GROUND ;
    PORT
      LAYER Metal3 ;
        RECT 0.000 140.000 50.000 158.000 ;
    END
    PORT
      LAYER Metal4 ;
        RECT 0.000 162.200 50.000 178.000 ;
    END
    PORT
      LAYER Metal5 ;
        RECT 0.000 160.000 50.000 178.000 ;
    END
    PORT
      LAYER TopMetal1 ;
        RECT 0.000 160.000 50.000 178.000 ;
    END
  END vss
  OBS
    LAYER Metal1 ;
      RECT 0.000 0.000 50.000 180.000 ;
    LAYER Metal2 ;
      RECT 0.000 0.000 50.000 180.000 ;
    LAYER Metal3 ;
      RECT 0.000 0.000 80.000 178.000 ;
    LAYER Metal4 ;
      RECT 0.000 0.000 80.000 178.000 ;
    LAYER Metal5 ;
      RECT 0.000 0.000 80.000 178.000 ;
    LAYER TopMetal1 ;
      RECT 0.000 0.000 80.000 178.000 ;
    LAYER TopMetal2 ;
      RECT 0.000 8.500 50.000 132.500 ;
    LAYER Via1 ;
      RECT 0.000 0.000 50.000 180.000 ;
    LAYER Via2 ;
      RECT 0.000 0.000 50.000 180.000 ;
  END
END Filler10000

MACRO IOPadIn
  CLASS PAD INPUT ;
  ORIGIN 0.000 0.000 ;
  FOREIGN IOPadIn 0.000 0.000 ;
  SIZE 80.000 BY 180.000 ;
  SYMMETRY X Y R90 ;
  SITE IOLibSite ;
  PIN iovdd
    DIRECTION INOUT ;
    USE POWER ;
    PORT
      LAYER Metal3 ;
        RECT 0.000 93.500 80.000 119.000 ;
    END
    PORT
      LAYER Metal3 ;
        RECT 0.000 66.000 80.000 91.500 ;
    END
    PORT
      LAYER Metal4 ;
        RECT 0.000 93.500 80.000 119.000 ;
    END
    PORT
      LAYER Metal4 ;
        RECT 0.000 66.000 80.000 91.500 ;
    END
    PORT
      LAYER Metal5 ;
        RECT 0.000 93.500 80.000 119.000 ;
    END
    PORT
      LAYER Metal5 ;
        RECT 0.000 66.000 80.000 91.500 ;
    END
    PORT
      LAYER TopMetal1 ;
        RECT 0.000 93.500 80.000 119.000 ;
    END
    PORT
      LAYER TopMetal1 ;
        RECT 0.000 66.000 80.000 91.500 ;
    END
    PORT
      LAYER TopMetal2 ;
        RECT 0.000 95.000 80.000 117.500 ;
    END
    PORT
      LAYER TopMetal2 ;
        RECT 0.000 67.500 80.000 90.000 ;
    END
  END iovdd
  PIN iovss
    DIRECTION INOUT ;
    USE GROUND ;
    PORT
      LAYER Metal3 ;
        RECT 0.000 7.000 80.000 32.500 ;
    END
    PORT
      LAYER Metal3 ;
        RECT 0.000 126.000 80.000 134.000 ;
    END
    PORT
      LAYER Metal3 ;
        RECT 0.000 34.500 80.000 60.000 ;
    END
    PORT
      LAYER Metal4 ;
        RECT 0.000 7.000 80.000 32.500 ;
    END
    PORT
      LAYER Metal4 ;
        RECT 0.000 126.000 80.000 134.000 ;
    END
    PORT
      LAYER Metal4 ;
        RECT 0.000 34.500 80.000 60.000 ;
    END
    PORT
      LAYER Metal5 ;
        RECT 0.000 7.000 80.000 32.500 ;
    END
    PORT
      LAYER Metal5 ;
        RECT 0.000 126.000 80.000 134.000 ;
    END
    PORT
      LAYER Metal5 ;
        RECT 0.000 34.500 80.000 60.000 ;
    END
    PORT
      LAYER TopMetal1 ;
        RECT 0.000 7.000 80.000 32.500 ;
    END
    PORT
      LAYER TopMetal1 ;
        RECT 0.000 126.000 80.000 134.000 ;
    END
    PORT
      LAYER TopMetal1 ;
        RECT 0.000 34.500 80.000 60.000 ;
    END
    PORT
      LAYER TopMetal2 ;
        RECT 0.000 36.000 80.000 58.500 ;
    END
    PORT
      LAYER TopMetal2 ;
        RECT 0.000 8.500 80.000 31.000 ;
    END
    PORT
      LAYER TopMetal2 ;
        RECT 0.000 127.500 80.000 132.500 ;
    END
  END iovss
  PIN p2c
    DIRECTION OUTPUT ;
    USE SIGNAL ;
    PORT
      LAYER Metal2 ;
        RECT 39.830 157.810 40.120 180.000 ;
      LAYER Metal3 ;
        RECT 39.725 179.710 40.225 180.000 ;
    END
  END p2c
  PIN pad
    DIRECTION INOUT ;
    USE SIGNAL ;
    PORT
      LAYER Metal2 ;
        RECT 5.000 0.000 75.000 3.000 ;
      LAYER Metal3 ;
        RECT 5.000 0.000 75.000 3.000 ;
      LAYER Metal4 ;
        RECT 5.000 0.000 75.000 3.000 ;
      LAYER Metal5 ;
        RECT 5.000 0.000 75.000 3.000 ;
      LAYER TopMetal1 ;
        RECT 5.000 0.000 75.000 3.000 ;
      LAYER TopMetal2 ;
        RECT 5.000 0.000 75.000 3.000 ;
    END
  END pad
  PIN vdd
    DIRECTION INOUT ;
    USE POWER ;
    PORT
      LAYER Metal3 ;
        RECT 0.000 160.000 80.000 178.000 ;
    END
    PORT
      LAYER Metal4 ;
        RECT 0.000 140.000 80.000 155.800 ;
    END
    PORT
      LAYER Metal5 ;
        RECT 0.000 140.000 80.000 158.000 ;
    END
    PORT
      LAYER TopMetal1 ;
        RECT 0.000 140.000 80.000 158.000 ;
    END
  END vdd
  PIN vss
    DIRECTION INOUT ;
    USE GROUND ;
    PORT
      LAYER Metal3 ;
        RECT 0.000 140.000 80.000 158.000 ;
    END
    PORT
      LAYER Metal4 ;
        RECT 0.000 162.200 80.000 178.000 ;
    END
    PORT
      LAYER Metal5 ;
        RECT 0.000 160.000 80.000 178.000 ;
    END
    PORT
      LAYER TopMetal1 ;
        RECT 0.000 160.000 80.000 178.000 ;
    END
  END vss
  OBS
    LAYER Metal1 ;
      RECT 0.000 0.000 80.000 180.000 ;
    LAYER Metal2 ;
      RECT 0.000 0.000 80.000 180.000 ;
    LAYER Metal3 ;
      RECT 0.000 0.000 80.000 178.000 ;
    LAYER Metal4 ;
      RECT 0.000 0.000 80.000 178.000 ;
    LAYER Metal5 ;
      RECT 0.000 0.000 80.000 178.000 ;
    LAYER TopMetal1 ;
      RECT 0.000 0.000 80.000 178.000 ;
    LAYER TopMetal2 ;
      RECT 0.000 0.000 80.000 132.500 ;
    LAYER Via1 ;
      RECT 0.000 0.000 80.000 180.000 ;
    LAYER Via2 ;
      RECT 0.000 0.000 80.000 180.000 ;
  END
END IOPadIn

MACRO IOPadOut4mA
  CLASS PAD OUTPUT ;
  ORIGIN 0.000 0.000 ;
  FOREIGN IOPadOut4mA 0.000 0.000 ;
  SIZE 80.000 BY 180.000 ;
  SYMMETRY X Y R90 ;
  SITE IOLibSite ;
  PIN c2p
    DIRECTION INPUT ;
    USE SIGNAL ;
    PORT
      LAYER Metal2 ;
        RECT 38.145 167.000 41.855 180.000 ;
      LAYER Metal3 ;
        RECT 38.145 179.710 41.855 180.000 ;
    END
  END c2p
  PIN iovdd
    DIRECTION INOUT ;
    USE POWER ;
    PORT
      LAYER Metal3 ;
        RECT 0.000 93.500 80.000 119.000 ;
    END
    PORT
      LAYER Metal3 ;
        RECT 0.000 66.000 80.000 91.500 ;
    END
    PORT
      LAYER Metal4 ;
        RECT 0.000 93.500 80.000 119.000 ;
    END
    PORT
      LAYER Metal4 ;
        RECT 0.000 66.000 80.000 91.500 ;
    END
    PORT
      LAYER Metal5 ;
        RECT 0.000 93.500 80.000 119.000 ;
    END
    PORT
      LAYER Metal5 ;
        RECT 0.000 66.000 80.000 91.500 ;
    END
    PORT
      LAYER TopMetal1 ;
        RECT 0.000 93.500 80.000 119.000 ;
    END
    PORT
      LAYER TopMetal1 ;
        RECT 0.000 66.000 80.000 91.500 ;
    END
    PORT
      LAYER TopMetal2 ;
        RECT 0.000 95.000 80.000 117.500 ;
    END
    PORT
      LAYER TopMetal2 ;
        RECT 0.000 67.500 80.000 90.000 ;
    END
  END iovdd
  PIN iovss
    DIRECTION INOUT ;
    USE GROUND ;
    PORT
      LAYER Metal3 ;
        RECT 0.000 7.000 80.000 32.500 ;
    END
    PORT
      LAYER Metal3 ;
        RECT 0.000 126.000 80.000 134.000 ;
    END
    PORT
      LAYER Metal3 ;
        RECT 0.000 34.500 80.000 60.000 ;
    END
    PORT
      LAYER Metal4 ;
        RECT 0.000 7.000 80.000 32.500 ;
    END
    PORT
      LAYER Metal4 ;
        RECT 0.000 126.000 80.000 134.000 ;
    END
    PORT
      LAYER Metal4 ;
        RECT 0.000 34.500 80.000 60.000 ;
    END
    PORT
      LAYER Metal5 ;
        RECT 0.000 7.000 80.000 32.500 ;
    END
    PORT
      LAYER Metal5 ;
        RECT 0.000 126.000 80.000 134.000 ;
    END
    PORT
      LAYER Metal5 ;
        RECT 0.000 34.500 80.000 60.000 ;
    END
    PORT
      LAYER TopMetal1 ;
        RECT 0.000 7.000 80.000 32.500 ;
    END
    PORT
      LAYER TopMetal1 ;
        RECT 0.000 126.000 80.000 134.000 ;
    END
    PORT
      LAYER TopMetal1 ;
        RECT 0.000 34.500 80.000 60.000 ;
    END
    PORT
      LAYER TopMetal2 ;
        RECT 0.000 36.000 80.000 58.500 ;
    END
    PORT
      LAYER TopMetal2 ;
        RECT 0.000 8.500 80.000 31.000 ;
    END
    PORT
      LAYER TopMetal2 ;
        RECT 0.000 127.500 80.000 132.500 ;
    END
  END iovss
  PIN pad
    DIRECTION INOUT ;
    USE SIGNAL ;
    PORT
      LAYER Metal2 ;
        RECT 5.000 0.000 75.000 3.000 ;
      LAYER Metal3 ;
        RECT 5.000 0.000 75.000 3.000 ;
      LAYER Metal4 ;
        RECT 5.000 0.000 75.000 3.000 ;
      LAYER Metal5 ;
        RECT 5.000 0.000 75.000 3.000 ;
      LAYER TopMetal1 ;
        RECT 5.000 0.000 75.000 3.000 ;
      LAYER TopMetal2 ;
        RECT 5.000 0.000 75.000 3.000 ;
    END
  END pad
  PIN vdd
    DIRECTION INOUT ;
    USE POWER ;
    PORT
      LAYER Metal3 ;
        RECT 0.000 160.000 80.000 178.000 ;
    END
    PORT
      LAYER Metal4 ;
        RECT 0.000 140.000 80.000 155.800 ;
    END
    PORT
      LAYER Metal5 ;
        RECT 0.000 140.000 80.000 158.000 ;
    END
    PORT
      LAYER TopMetal1 ;
        RECT 0.000 140.000 80.000 158.000 ;
    END
  END vdd
  PIN vss
    DIRECTION INOUT ;
    USE GROUND ;
    PORT
      LAYER Metal3 ;
        RECT 0.000 140.000 80.000 158.000 ;
    END
    PORT
      LAYER Metal4 ;
        RECT 0.000 162.200 80.000 178.000 ;
    END
    PORT
      LAYER Metal5 ;
        RECT 0.000 160.000 80.000 178.000 ;
    END
    PORT
      LAYER TopMetal1 ;
        RECT 0.000 160.000 80.000 178.000 ;
    END
  END vss
  OBS
    LAYER Metal1 ;
      RECT 0.000 0.000 80.000 180.000 ;
    LAYER Metal2 ;
      RECT 0.000 0.000 80.000 180.000 ;
    LAYER Metal3 ;
      RECT 0.000 0.000 80.000 178.000 ;
    LAYER Metal4 ;
      RECT 0.000 0.000 80.000 178.000 ;
    LAYER Metal5 ;
      RECT 0.000 0.000 80.000 178.000 ;
    LAYER TopMetal1 ;
      RECT 0.000 0.000 80.000 178.000 ;
    LAYER TopMetal2 ;
      RECT 0.000 0.000 80.000 132.500 ;
    LAYER Via1 ;
      RECT 0.000 0.000 80.000 180.000 ;
    LAYER Via2 ;
      RECT 0.000 0.000 80.000 180.000 ;
  END
END IOPadOut4mA

MACRO IOPadOut8mA
  CLASS PAD OUTPUT ;
  ORIGIN 0.000 0.000 ;
  FOREIGN IOPadOut8mA 0.000 0.000 ;
  SIZE 80.000 BY 180.000 ;
  SYMMETRY X Y R90 ;
  SITE IOLibSite ;
  PIN c2p
    DIRECTION INPUT ;
    USE SIGNAL ;
    PORT
      LAYER Metal2 ;
        RECT 38.145 167.000 41.855 180.000 ;
      LAYER Metal3 ;
        RECT 38.145 179.710 41.855 180.000 ;
    END
  END c2p
  PIN iovdd
    DIRECTION INOUT ;
    USE POWER ;
    PORT
      LAYER Metal3 ;
        RECT 0.000 93.500 80.000 119.000 ;
    END
    PORT
      LAYER Metal3 ;
        RECT 0.000 66.000 80.000 91.500 ;
    END
    PORT
      LAYER Metal4 ;
        RECT 0.000 93.500 80.000 119.000 ;
    END
    PORT
      LAYER Metal4 ;
        RECT 0.000 66.000 80.000 91.500 ;
    END
    PORT
      LAYER Metal5 ;
        RECT 0.000 93.500 80.000 119.000 ;
    END
    PORT
      LAYER Metal5 ;
        RECT 0.000 66.000 80.000 91.500 ;
    END
    PORT
      LAYER TopMetal1 ;
        RECT 0.000 93.500 80.000 119.000 ;
    END
    PORT
      LAYER TopMetal1 ;
        RECT 0.000 66.000 80.000 91.500 ;
    END
    PORT
      LAYER TopMetal2 ;
        RECT 0.000 95.000 80.000 117.500 ;
    END
    PORT
      LAYER TopMetal2 ;
        RECT 0.000 67.500 80.000 90.000 ;
    END
  END iovdd
  PIN iovss
    DIRECTION INOUT ;
    USE GROUND ;
    PORT
      LAYER Metal3 ;
        RECT 0.000 7.000 80.000 32.500 ;
    END
    PORT
      LAYER Metal3 ;
        RECT 0.000 126.000 80.000 134.000 ;
    END
    PORT
      LAYER Metal3 ;
        RECT 0.000 34.500 80.000 60.000 ;
    END
    PORT
      LAYER Metal4 ;
        RECT 0.000 7.000 80.000 32.500 ;
    END
    PORT
      LAYER Metal4 ;
        RECT 0.000 126.000 80.000 134.000 ;
    END
    PORT
      LAYER Metal4 ;
        RECT 0.000 34.500 80.000 60.000 ;
    END
    PORT
      LAYER Metal5 ;
        RECT 0.000 7.000 80.000 32.500 ;
    END
    PORT
      LAYER Metal5 ;
        RECT 0.000 126.000 80.000 134.000 ;
    END
    PORT
      LAYER Metal5 ;
        RECT 0.000 34.500 80.000 60.000 ;
    END
    PORT
      LAYER TopMetal1 ;
        RECT 0.000 7.000 80.000 32.500 ;
    END
    PORT
      LAYER TopMetal1 ;
        RECT 0.000 126.000 80.000 134.000 ;
    END
    PORT
      LAYER TopMetal1 ;
        RECT 0.000 34.500 80.000 60.000 ;
    END
    PORT
      LAYER TopMetal2 ;
        RECT 0.000 36.000 80.000 58.500 ;
    END
    PORT
      LAYER TopMetal2 ;
        RECT 0.000 8.500 80.000 31.000 ;
    END
    PORT
      LAYER TopMetal2 ;
        RECT 0.000 127.500 80.000 132.500 ;
    END
  END iovss
  PIN pad
    DIRECTION INOUT ;
    USE SIGNAL ;
    PORT
      LAYER Metal2 ;
        RECT 5.000 0.000 75.000 3.000 ;
      LAYER Metal3 ;
        RECT 5.000 0.000 75.000 3.000 ;
      LAYER Metal4 ;
        RECT 5.000 0.000 75.000 3.000 ;
      LAYER Metal5 ;
        RECT 5.000 0.000 75.000 3.000 ;
      LAYER TopMetal1 ;
        RECT 5.000 0.000 75.000 3.000 ;
      LAYER TopMetal2 ;
        RECT 5.000 0.000 75.000 3.000 ;
    END
  END pad
  PIN vdd
    DIRECTION INOUT ;
    USE POWER ;
    PORT
      LAYER Metal3 ;
        RECT 0.000 160.000 80.000 178.000 ;
    END
    PORT
      LAYER Metal4 ;
        RECT 0.000 140.000 80.000 155.800 ;
    END
    PORT
      LAYER Metal5 ;
        RECT 0.000 140.000 80.000 158.000 ;
    END
    PORT
      LAYER TopMetal1 ;
        RECT 0.000 140.000 80.000 158.000 ;
    END
  END vdd
  PIN vss
    DIRECTION INOUT ;
    USE GROUND ;
    PORT
      LAYER Metal3 ;
        RECT 0.000 140.000 80.000 158.000 ;
    END
    PORT
      LAYER Metal4 ;
        RECT 0.000 162.200 80.000 178.000 ;
    END
    PORT
      LAYER Metal5 ;
        RECT 0.000 160.000 80.000 178.000 ;
    END
    PORT
      LAYER TopMetal1 ;
        RECT 0.000 160.000 80.000 178.000 ;
    END
  END vss
  OBS
    LAYER Metal1 ;
      RECT 0.000 0.000 80.000 180.000 ;
    LAYER Metal2 ;
      RECT 0.000 0.000 80.000 180.000 ;
    LAYER Metal3 ;
      RECT 0.000 0.000 80.000 178.000 ;
    LAYER Metal4 ;
      RECT 0.000 0.000 80.000 178.000 ;
    LAYER Metal5 ;
      RECT 0.000 0.000 80.000 178.000 ;
    LAYER TopMetal1 ;
      RECT 0.000 0.000 80.000 178.000 ;
    LAYER TopMetal2 ;
      RECT 0.000 0.000 80.000 132.500 ;
    LAYER Via1 ;
      RECT 0.000 0.000 80.000 180.000 ;
    LAYER Via2 ;
      RECT 0.000 0.000 80.000 180.000 ;
  END
END IOPadOut8mA

MACRO IOPadOut12mA
  CLASS PAD OUTPUT ;
  ORIGIN 0.000 0.000 ;
  FOREIGN IOPadOut12mA 0.000 0.000 ;
  SIZE 80.000 BY 180.000 ;
  SYMMETRY X Y R90 ;
  SITE IOLibSite ;
  PIN c2p
    DIRECTION INPUT ;
    USE SIGNAL ;
    PORT
      LAYER Metal2 ;
        RECT 38.145 167.000 41.855 180.000 ;
      LAYER Metal3 ;
        RECT 38.145 179.710 41.855 180.000 ;
    END
  END c2p
  PIN iovdd
    DIRECTION INOUT ;
    USE POWER ;
    PORT
      LAYER Metal3 ;
        RECT 0.000 93.500 80.000 119.000 ;
    END
    PORT
      LAYER Metal3 ;
        RECT 0.000 66.000 80.000 91.500 ;
    END
    PORT
      LAYER Metal4 ;
        RECT 0.000 93.500 80.000 119.000 ;
    END
    PORT
      LAYER Metal4 ;
        RECT 0.000 66.000 80.000 91.500 ;
    END
    PORT
      LAYER Metal5 ;
        RECT 0.000 93.500 80.000 119.000 ;
    END
    PORT
      LAYER Metal5 ;
        RECT 0.000 66.000 80.000 91.500 ;
    END
    PORT
      LAYER TopMetal1 ;
        RECT 0.000 93.500 80.000 119.000 ;
    END
    PORT
      LAYER TopMetal1 ;
        RECT 0.000 66.000 80.000 91.500 ;
    END
    PORT
      LAYER TopMetal2 ;
        RECT 0.000 95.000 80.000 117.500 ;
    END
    PORT
      LAYER TopMetal2 ;
        RECT 0.000 67.500 80.000 90.000 ;
    END
  END iovdd
  PIN iovss
    DIRECTION INOUT ;
    USE GROUND ;
    PORT
      LAYER Metal3 ;
        RECT 0.000 7.000 80.000 32.500 ;
    END
    PORT
      LAYER Metal3 ;
        RECT 0.000 126.000 80.000 134.000 ;
    END
    PORT
      LAYER Metal3 ;
        RECT 0.000 34.500 80.000 60.000 ;
    END
    PORT
      LAYER Metal4 ;
        RECT 0.000 7.000 80.000 32.500 ;
    END
    PORT
      LAYER Metal4 ;
        RECT 0.000 126.000 80.000 134.000 ;
    END
    PORT
      LAYER Metal4 ;
        RECT 0.000 34.500 80.000 60.000 ;
    END
    PORT
      LAYER Metal5 ;
        RECT 0.000 7.000 80.000 32.500 ;
    END
    PORT
      LAYER Metal5 ;
        RECT 0.000 126.000 80.000 134.000 ;
    END
    PORT
      LAYER Metal5 ;
        RECT 0.000 34.500 80.000 60.000 ;
    END
    PORT
      LAYER TopMetal1 ;
        RECT 0.000 7.000 80.000 32.500 ;
    END
    PORT
      LAYER TopMetal1 ;
        RECT 0.000 126.000 80.000 134.000 ;
    END
    PORT
      LAYER TopMetal1 ;
        RECT 0.000 34.500 80.000 60.000 ;
    END
    PORT
      LAYER TopMetal2 ;
        RECT 0.000 36.000 80.000 58.500 ;
    END
    PORT
      LAYER TopMetal2 ;
        RECT 0.000 8.500 80.000 31.000 ;
    END
    PORT
      LAYER TopMetal2 ;
        RECT 0.000 127.500 80.000 132.500 ;
    END
  END iovss
  PIN pad
    DIRECTION INOUT ;
    USE SIGNAL ;
    PORT
      LAYER Metal2 ;
        RECT 5.000 0.000 75.000 3.000 ;
      LAYER Metal3 ;
        RECT 5.000 0.000 75.000 3.000 ;
      LAYER Metal4 ;
        RECT 5.000 0.000 75.000 3.000 ;
      LAYER Metal5 ;
        RECT 5.000 0.000 75.000 3.000 ;
      LAYER TopMetal1 ;
        RECT 5.000 0.000 75.000 3.000 ;
      LAYER TopMetal2 ;
        RECT 5.000 0.000 75.000 3.000 ;
    END
  END pad
  PIN vdd
    DIRECTION INOUT ;
    USE POWER ;
    PORT
      LAYER Metal3 ;
        RECT 0.000 160.000 80.000 178.000 ;
    END
    PORT
      LAYER Metal4 ;
        RECT 0.000 140.000 80.000 155.800 ;
    END
    PORT
      LAYER Metal5 ;
        RECT 0.000 140.000 80.000 158.000 ;
    END
    PORT
      LAYER TopMetal1 ;
        RECT 0.000 140.000 80.000 158.000 ;
    END
  END vdd
  PIN vss
    DIRECTION INOUT ;
    USE GROUND ;
    PORT
      LAYER Metal3 ;
        RECT 0.000 140.000 80.000 158.000 ;
    END
    PORT
      LAYER Metal4 ;
        RECT 0.000 162.200 80.000 178.000 ;
    END
    PORT
      LAYER Metal5 ;
        RECT 0.000 160.000 80.000 178.000 ;
    END
    PORT
      LAYER TopMetal1 ;
        RECT 0.000 160.000 80.000 178.000 ;
    END
  END vss
  OBS
    LAYER Metal1 ;
      RECT 0.000 0.000 80.000 180.000 ;
    LAYER Metal2 ;
      RECT 0.000 0.000 80.000 180.000 ;
    LAYER Metal3 ;
      RECT 0.000 0.000 80.000 178.000 ;
    LAYER Metal4 ;
      RECT 0.000 0.000 80.000 178.000 ;
    LAYER Metal5 ;
      RECT 0.000 0.000 80.000 178.000 ;
    LAYER TopMetal1 ;
      RECT 0.000 0.000 80.000 178.000 ;
    LAYER TopMetal2 ;
      RECT 0.000 0.000 80.000 132.500 ;
    LAYER Via1 ;
      RECT 0.000 0.000 80.000 180.000 ;
    LAYER Via2 ;
      RECT 0.000 0.000 80.000 180.000 ;
  END
END IOPadOut12mA

MACRO IOPadOut16mA
  CLASS PAD OUTPUT ;
  ORIGIN 0.000 0.000 ;
  FOREIGN IOPadOut16mA 0.000 0.000 ;
  SIZE 80.000 BY 180.000 ;
  SYMMETRY X Y R90 ;
  SITE IOLibSite ;
  PIN c2p
    DIRECTION INPUT ;
    USE SIGNAL ;
    PORT
      LAYER Metal2 ;
        RECT 38.145 167.000 41.855 180.000 ;
      LAYER Metal3 ;
        RECT 38.145 179.710 41.855 180.000 ;
    END
  END c2p
  PIN iovdd
    DIRECTION INOUT ;
    USE POWER ;
    PORT
      LAYER Metal3 ;
        RECT 0.000 93.500 80.000 119.000 ;
    END
    PORT
      LAYER Metal3 ;
        RECT 0.000 66.000 80.000 91.500 ;
    END
    PORT
      LAYER Metal4 ;
        RECT 0.000 93.500 80.000 119.000 ;
    END
    PORT
      LAYER Metal4 ;
        RECT 0.000 66.000 80.000 91.500 ;
    END
    PORT
      LAYER Metal5 ;
        RECT 0.000 93.500 80.000 119.000 ;
    END
    PORT
      LAYER Metal5 ;
        RECT 0.000 66.000 80.000 91.500 ;
    END
    PORT
      LAYER TopMetal1 ;
        RECT 0.000 93.500 80.000 119.000 ;
    END
    PORT
      LAYER TopMetal1 ;
        RECT 0.000 66.000 80.000 91.500 ;
    END
    PORT
      LAYER TopMetal2 ;
        RECT 0.000 95.000 80.000 117.500 ;
    END
    PORT
      LAYER TopMetal2 ;
        RECT 0.000 67.500 80.000 90.000 ;
    END
  END iovdd
  PIN iovss
    DIRECTION INOUT ;
    USE GROUND ;
    PORT
      LAYER Metal3 ;
        RECT 0.000 7.000 80.000 32.500 ;
    END
    PORT
      LAYER Metal3 ;
        RECT 0.000 126.000 80.000 134.000 ;
    END
    PORT
      LAYER Metal3 ;
        RECT 0.000 34.500 80.000 60.000 ;
    END
    PORT
      LAYER Metal4 ;
        RECT 0.000 7.000 80.000 32.500 ;
    END
    PORT
      LAYER Metal4 ;
        RECT 0.000 126.000 80.000 134.000 ;
    END
    PORT
      LAYER Metal4 ;
        RECT 0.000 34.500 80.000 60.000 ;
    END
    PORT
      LAYER Metal5 ;
        RECT 0.000 7.000 80.000 32.500 ;
    END
    PORT
      LAYER Metal5 ;
        RECT 0.000 126.000 80.000 134.000 ;
    END
    PORT
      LAYER Metal5 ;
        RECT 0.000 34.500 80.000 60.000 ;
    END
    PORT
      LAYER TopMetal1 ;
        RECT 0.000 7.000 80.000 32.500 ;
    END
    PORT
      LAYER TopMetal1 ;
        RECT 0.000 126.000 80.000 134.000 ;
    END
    PORT
      LAYER TopMetal1 ;
        RECT 0.000 34.500 80.000 60.000 ;
    END
    PORT
      LAYER TopMetal2 ;
        RECT 0.000 36.000 80.000 58.500 ;
    END
    PORT
      LAYER TopMetal2 ;
        RECT 0.000 8.500 80.000 31.000 ;
    END
    PORT
      LAYER TopMetal2 ;
        RECT 0.000 127.500 80.000 132.500 ;
    END
  END iovss
  PIN pad
    DIRECTION INOUT ;
    USE SIGNAL ;
    PORT
      LAYER Metal2 ;
        RECT 5.000 0.000 75.000 3.000 ;
      LAYER Metal3 ;
        RECT 5.000 0.000 75.000 3.000 ;
      LAYER Metal4 ;
        RECT 5.000 0.000 75.000 3.000 ;
      LAYER Metal5 ;
        RECT 5.000 0.000 75.000 3.000 ;
      LAYER TopMetal1 ;
        RECT 5.000 0.000 75.000 3.000 ;
      LAYER TopMetal2 ;
        RECT 5.000 0.000 75.000 3.000 ;
    END
  END pad
  PIN vdd
    DIRECTION INOUT ;
    USE POWER ;
    PORT
      LAYER Metal3 ;
        RECT 0.000 160.000 80.000 178.000 ;
    END
    PORT
      LAYER Metal4 ;
        RECT 0.000 140.000 80.000 155.800 ;
    END
    PORT
      LAYER Metal5 ;
        RECT 0.000 140.000 80.000 158.000 ;
    END
    PORT
      LAYER TopMetal1 ;
        RECT 0.000 140.000 80.000 158.000 ;
    END
  END vdd
  PIN vss
    DIRECTION INOUT ;
    USE GROUND ;
    PORT
      LAYER Metal3 ;
        RECT 0.000 140.000 80.000 158.000 ;
    END
    PORT
      LAYER Metal4 ;
        RECT 0.000 162.200 80.000 178.000 ;
    END
    PORT
      LAYER Metal5 ;
        RECT 0.000 160.000 80.000 178.000 ;
    END
    PORT
      LAYER TopMetal1 ;
        RECT 0.000 160.000 80.000 178.000 ;
    END
  END vss
  OBS
    LAYER Metal1 ;
      RECT 0.000 0.000 80.000 180.000 ;
    LAYER Metal2 ;
      RECT 0.000 0.000 80.000 180.000 ;
    LAYER Metal3 ;
      RECT 0.000 0.000 80.000 178.000 ;
    LAYER Metal4 ;
      RECT 0.000 0.000 80.000 178.000 ;
    LAYER Metal5 ;
      RECT 0.000 0.000 80.000 178.000 ;
    LAYER TopMetal1 ;
      RECT 0.000 0.000 80.000 178.000 ;
    LAYER TopMetal2 ;
      RECT 0.000 0.000 80.000 132.500 ;
    LAYER Via1 ;
      RECT 0.000 0.000 80.000 180.000 ;
    LAYER Via2 ;
      RECT 0.000 0.000 80.000 180.000 ;
  END
END IOPadOut16mA

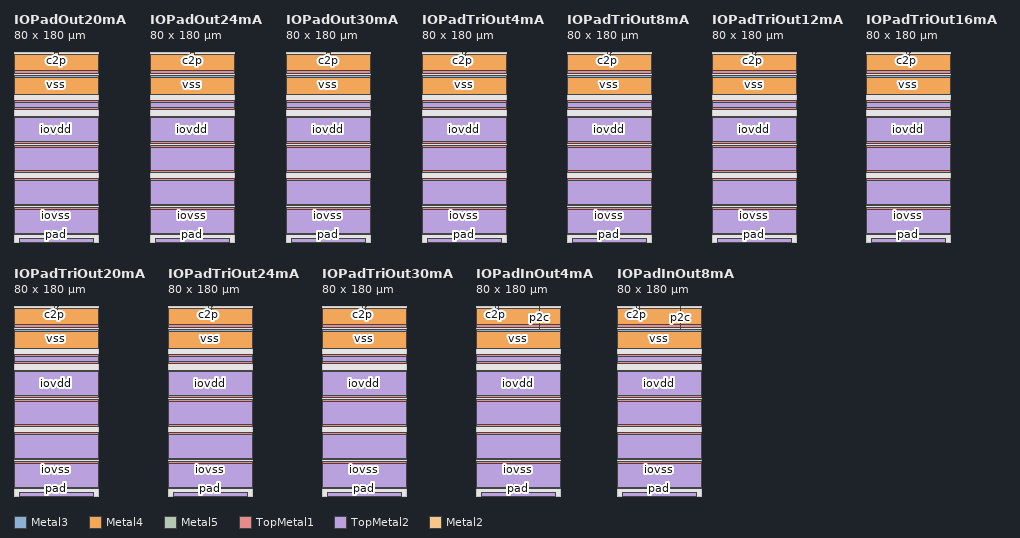
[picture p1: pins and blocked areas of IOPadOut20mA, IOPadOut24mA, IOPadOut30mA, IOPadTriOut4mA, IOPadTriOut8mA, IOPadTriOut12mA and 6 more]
MACRO IOPadOut20mA
  CLASS PAD OUTPUT ;
  ORIGIN 0.000 0.000 ;
  FOREIGN IOPadOut20mA 0.000 0.000 ;
  SIZE 80.000 BY 180.000 ;
  SYMMETRY X Y R90 ;
  SITE IOLibSite ;
  PIN c2p
    DIRECTION INPUT ;
    USE SIGNAL ;
    PORT
      LAYER Metal2 ;
        RECT 38.145 167.000 41.855 180.000 ;
      LAYER Metal3 ;
        RECT 38.145 179.710 41.855 180.000 ;
    END
  END c2p
  PIN iovdd
    DIRECTION INOUT ;
    USE POWER ;
    PORT
      LAYER Metal3 ;
        RECT 0.000 93.500 80.000 119.000 ;
    END
    PORT
      LAYER Metal3 ;
        RECT 0.000 66.000 80.000 91.500 ;
    END
    PORT
      LAYER Metal4 ;
        RECT 0.000 93.500 80.000 119.000 ;
    END
    PORT
      LAYER Metal4 ;
        RECT 0.000 66.000 80.000 91.500 ;
    END
    PORT
      LAYER Metal5 ;
        RECT 0.000 93.500 80.000 119.000 ;
    END
    PORT
      LAYER Metal5 ;
        RECT 0.000 66.000 80.000 91.500 ;
    END
    PORT
      LAYER TopMetal1 ;
        RECT 0.000 93.500 80.000 119.000 ;
    END
    PORT
      LAYER TopMetal1 ;
        RECT 0.000 66.000 80.000 91.500 ;
    END
    PORT
      LAYER TopMetal2 ;
        RECT 0.000 95.000 80.000 117.500 ;
    END
    PORT
      LAYER TopMetal2 ;
        RECT 0.000 67.500 80.000 90.000 ;
    END
  END iovdd
  PIN iovss
    DIRECTION INOUT ;
    USE GROUND ;
    PORT
      LAYER Metal3 ;
        RECT 0.000 7.000 80.000 32.500 ;
    END
    PORT
      LAYER Metal3 ;
        RECT 0.000 126.000 80.000 134.000 ;
    END
    PORT
      LAYER Metal3 ;
        RECT 0.000 34.500 80.000 60.000 ;
    END
    PORT
      LAYER Metal4 ;
        RECT 0.000 7.000 80.000 32.500 ;
    END
    PORT
      LAYER Metal4 ;
        RECT 0.000 126.000 80.000 134.000 ;
    END
    PORT
      LAYER Metal4 ;
        RECT 0.000 34.500 80.000 60.000 ;
    END
    PORT
      LAYER Metal5 ;
        RECT 0.000 7.000 80.000 32.500 ;
    END
    PORT
      LAYER Metal5 ;
        RECT 0.000 126.000 80.000 134.000 ;
    END
    PORT
      LAYER Metal5 ;
        RECT 0.000 34.500 80.000 60.000 ;
    END
    PORT
      LAYER TopMetal1 ;
        RECT 0.000 7.000 80.000 32.500 ;
    END
    PORT
      LAYER TopMetal1 ;
        RECT 0.000 126.000 80.000 134.000 ;
    END
    PORT
      LAYER TopMetal1 ;
        RECT 0.000 34.500 80.000 60.000 ;
    END
    PORT
      LAYER TopMetal2 ;
        RECT 0.000 36.000 80.000 58.500 ;
    END
    PORT
      LAYER TopMetal2 ;
        RECT 0.000 8.500 80.000 31.000 ;
    END
    PORT
      LAYER TopMetal2 ;
        RECT 0.000 127.500 80.000 132.500 ;
    END
  END iovss
  PIN pad
    DIRECTION INOUT ;
    USE SIGNAL ;
    PORT
      LAYER Metal2 ;
        RECT 5.000 0.000 75.000 3.000 ;
      LAYER Metal3 ;
        RECT 5.000 0.000 75.000 3.000 ;
      LAYER Metal4 ;
        RECT 5.000 0.000 75.000 3.000 ;
      LAYER Metal5 ;
        RECT 5.000 0.000 75.000 3.000 ;
      LAYER TopMetal1 ;
        RECT 5.000 0.000 75.000 3.000 ;
      LAYER TopMetal2 ;
        RECT 5.000 0.000 75.000 3.000 ;
    END
  END pad
  PIN vdd
    DIRECTION INOUT ;
    USE POWER ;
    PORT
      LAYER Metal3 ;
        RECT 0.000 160.000 80.000 178.000 ;
    END
    PORT
      LAYER Metal4 ;
        RECT 0.000 140.000 80.000 155.800 ;
    END
    PORT
      LAYER Metal5 ;
        RECT 0.000 140.000 80.000 158.000 ;
    END
    PORT
      LAYER TopMetal1 ;
        RECT 0.000 140.000 80.000 158.000 ;
    END
  END vdd
  PIN vss
    DIRECTION INOUT ;
    USE GROUND ;
    PORT
      LAYER Metal3 ;
        RECT 0.000 140.000 80.000 158.000 ;
    END
    PORT
      LAYER Metal4 ;
        RECT 0.000 162.200 80.000 178.000 ;
    END
    PORT
      LAYER Metal5 ;
        RECT 0.000 160.000 80.000 178.000 ;
    END
    PORT
      LAYER TopMetal1 ;
        RECT 0.000 160.000 80.000 178.000 ;
    END
  END vss
  OBS
    LAYER Metal1 ;
      RECT 0.000 0.000 80.000 180.000 ;
    LAYER Metal2 ;
      RECT 0.000 0.000 80.000 180.000 ;
    LAYER Metal3 ;
      RECT 0.000 0.000 80.000 178.000 ;
    LAYER Metal4 ;
      RECT 0.000 0.000 80.000 178.000 ;
    LAYER Metal5 ;
      RECT 0.000 0.000 80.000 178.000 ;
    LAYER TopMetal1 ;
      RECT 0.000 0.000 80.000 178.000 ;
    LAYER TopMetal2 ;
      RECT 0.000 0.000 80.000 132.500 ;
    LAYER Via1 ;
      RECT 0.000 0.000 80.000 180.000 ;
    LAYER Via2 ;
      RECT 0.000 0.000 80.000 180.000 ;
  END
END IOPadOut20mA

MACRO IOPadOut24mA
  CLASS PAD OUTPUT ;
  ORIGIN 0.000 0.000 ;
  FOREIGN IOPadOut24mA 0.000 0.000 ;
  SIZE 80.000 BY 180.000 ;
  SYMMETRY X Y R90 ;
  SITE IOLibSite ;
  PIN c2p
    DIRECTION INPUT ;
    USE SIGNAL ;
    PORT
      LAYER Metal2 ;
        RECT 38.145 167.000 41.855 180.000 ;
      LAYER Metal3 ;
        RECT 38.145 179.710 41.855 180.000 ;
    END
  END c2p
  PIN iovdd
    DIRECTION INOUT ;
    USE POWER ;
    PORT
      LAYER Metal3 ;
        RECT 0.000 93.500 80.000 119.000 ;
    END
    PORT
      LAYER Metal3 ;
        RECT 0.000 66.000 80.000 91.500 ;
    END
    PORT
      LAYER Metal4 ;
        RECT 0.000 93.500 80.000 119.000 ;
    END
    PORT
      LAYER Metal4 ;
        RECT 0.000 66.000 80.000 91.500 ;
    END
    PORT
      LAYER Metal5 ;
        RECT 0.000 93.500 80.000 119.000 ;
    END
    PORT
      LAYER Metal5 ;
        RECT 0.000 66.000 80.000 91.500 ;
    END
    PORT
      LAYER TopMetal1 ;
        RECT 0.000 93.500 80.000 119.000 ;
    END
    PORT
      LAYER TopMetal1 ;
        RECT 0.000 66.000 80.000 91.500 ;
    END
    PORT
      LAYER TopMetal2 ;
        RECT 0.000 95.000 80.000 117.500 ;
    END
    PORT
      LAYER TopMetal2 ;
        RECT 0.000 67.500 80.000 90.000 ;
    END
  END iovdd
  PIN iovss
    DIRECTION INOUT ;
    USE GROUND ;
    PORT
      LAYER Metal3 ;
        RECT 0.000 7.000 80.000 32.500 ;
    END
    PORT
      LAYER Metal3 ;
        RECT 0.000 126.000 80.000 134.000 ;
    END
    PORT
      LAYER Metal3 ;
        RECT 0.000 34.500 80.000 60.000 ;
    END
    PORT
      LAYER Metal4 ;
        RECT 0.000 7.000 80.000 32.500 ;
    END
    PORT
      LAYER Metal4 ;
        RECT 0.000 126.000 80.000 134.000 ;
    END
    PORT
      LAYER Metal4 ;
        RECT 0.000 34.500 80.000 60.000 ;
    END
    PORT
      LAYER Metal5 ;
        RECT 0.000 7.000 80.000 32.500 ;
    END
    PORT
      LAYER Metal5 ;
        RECT 0.000 126.000 80.000 134.000 ;
    END
    PORT
      LAYER Metal5 ;
        RECT 0.000 34.500 80.000 60.000 ;
    END
    PORT
      LAYER TopMetal1 ;
        RECT 0.000 7.000 80.000 32.500 ;
    END
    PORT
      LAYER TopMetal1 ;
        RECT 0.000 126.000 80.000 134.000 ;
    END
    PORT
      LAYER TopMetal1 ;
        RECT 0.000 34.500 80.000 60.000 ;
    END
    PORT
      LAYER TopMetal2 ;
        RECT 0.000 36.000 80.000 58.500 ;
    END
    PORT
      LAYER TopMetal2 ;
        RECT 0.000 8.500 80.000 31.000 ;
    END
    PORT
      LAYER TopMetal2 ;
        RECT 0.000 127.500 80.000 132.500 ;
    END
  END iovss
  PIN pad
    DIRECTION INOUT ;
    USE SIGNAL ;
    PORT
      LAYER Metal2 ;
        RECT 5.000 0.000 75.000 3.000 ;
      LAYER Metal3 ;
        RECT 5.000 0.000 75.000 3.000 ;
      LAYER Metal4 ;
        RECT 5.000 0.000 75.000 3.000 ;
      LAYER Metal5 ;
        RECT 5.000 0.000 75.000 3.000 ;
      LAYER TopMetal1 ;
        RECT 5.000 0.000 75.000 3.000 ;
      LAYER TopMetal2 ;
        RECT 5.000 0.000 75.000 3.000 ;
    END
  END pad
  PIN vdd
    DIRECTION INOUT ;
    USE POWER ;
    PORT
      LAYER Metal3 ;
        RECT 0.000 160.000 80.000 178.000 ;
    END
    PORT
      LAYER Metal4 ;
        RECT 0.000 140.000 80.000 155.800 ;
    END
    PORT
      LAYER Metal5 ;
        RECT 0.000 140.000 80.000 158.000 ;
    END
    PORT
      LAYER TopMetal1 ;
        RECT 0.000 140.000 80.000 158.000 ;
    END
  END vdd
  PIN vss
    DIRECTION INOUT ;
    USE GROUND ;
    PORT
      LAYER Metal3 ;
        RECT 0.000 140.000 80.000 158.000 ;
    END
    PORT
      LAYER Metal4 ;
        RECT 0.000 162.200 80.000 178.000 ;
    END
    PORT
      LAYER Metal5 ;
        RECT 0.000 160.000 80.000 178.000 ;
    END
    PORT
      LAYER TopMetal1 ;
        RECT 0.000 160.000 80.000 178.000 ;
    END
  END vss
  OBS
    LAYER Metal1 ;
      RECT 0.000 0.000 80.000 180.000 ;
    LAYER Metal2 ;
      RECT 0.000 0.000 80.000 180.000 ;
    LAYER Metal3 ;
      RECT 0.000 0.000 80.000 178.000 ;
    LAYER Metal4 ;
      RECT 0.000 0.000 80.000 178.000 ;
    LAYER Metal5 ;
      RECT 0.000 0.000 80.000 178.000 ;
    LAYER TopMetal1 ;
      RECT 0.000 0.000 80.000 178.000 ;
    LAYER TopMetal2 ;
      RECT 0.000 0.000 80.000 132.500 ;
    LAYER Via1 ;
      RECT 0.000 0.000 80.000 180.000 ;
    LAYER Via2 ;
      RECT 0.000 0.000 80.000 180.000 ;
  END
END IOPadOut24mA

MACRO IOPadOut30mA
  CLASS PAD OUTPUT ;
  ORIGIN 0.000 0.000 ;
  FOREIGN IOPadOut30mA 0.000 0.000 ;
  SIZE 80.000 BY 180.000 ;
  SYMMETRY X Y R90 ;
  SITE IOLibSite ;
  PIN c2p
    DIRECTION INPUT ;
    USE SIGNAL ;
    PORT
      LAYER Metal2 ;
        RECT 38.145 167.000 41.855 180.000 ;
      LAYER Metal3 ;
        RECT 38.145 179.710 41.855 180.000 ;
    END
  END c2p
  PIN iovdd
    DIRECTION INOUT ;
    USE POWER ;
    PORT
      LAYER Metal3 ;
        RECT 0.000 93.500 80.000 119.000 ;
    END
    PORT
      LAYER Metal3 ;
        RECT 0.000 66.000 80.000 91.500 ;
    END
    PORT
      LAYER Metal4 ;
        RECT 0.000 93.500 80.000 119.000 ;
    END
    PORT
      LAYER Metal4 ;
        RECT 0.000 66.000 80.000 91.500 ;
    END
    PORT
      LAYER Metal5 ;
        RECT 0.000 93.500 80.000 119.000 ;
    END
    PORT
      LAYER Metal5 ;
        RECT 0.000 66.000 80.000 91.500 ;
    END
    PORT
      LAYER TopMetal1 ;
        RECT 0.000 93.500 80.000 119.000 ;
    END
    PORT
      LAYER TopMetal1 ;
        RECT 0.000 66.000 80.000 91.500 ;
    END
    PORT
      LAYER TopMetal2 ;
        RECT 0.000 95.000 80.000 117.500 ;
    END
    PORT
      LAYER TopMetal2 ;
        RECT 0.000 67.500 80.000 90.000 ;
    END
  END iovdd
  PIN iovss
    DIRECTION INOUT ;
    USE GROUND ;
    PORT
      LAYER Metal3 ;
        RECT 0.000 7.000 80.000 32.500 ;
    END
    PORT
      LAYER Metal3 ;
        RECT 0.000 126.000 80.000 134.000 ;
    END
    PORT
      LAYER Metal3 ;
        RECT 0.000 34.500 80.000 60.000 ;
    END
    PORT
      LAYER Metal4 ;
        RECT 0.000 7.000 80.000 32.500 ;
    END
    PORT
      LAYER Metal4 ;
        RECT 0.000 126.000 80.000 134.000 ;
    END
    PORT
      LAYER Metal4 ;
        RECT 0.000 34.500 80.000 60.000 ;
    END
    PORT
      LAYER Metal5 ;
        RECT 0.000 7.000 80.000 32.500 ;
    END
    PORT
      LAYER Metal5 ;
        RECT 0.000 126.000 80.000 134.000 ;
    END
    PORT
      LAYER Metal5 ;
        RECT 0.000 34.500 80.000 60.000 ;
    END
    PORT
      LAYER TopMetal1 ;
        RECT 0.000 7.000 80.000 32.500 ;
    END
    PORT
      LAYER TopMetal1 ;
        RECT 0.000 126.000 80.000 134.000 ;
    END
    PORT
      LAYER TopMetal1 ;
        RECT 0.000 34.500 80.000 60.000 ;
    END
    PORT
      LAYER TopMetal2 ;
        RECT 0.000 36.000 80.000 58.500 ;
    END
    PORT
      LAYER TopMetal2 ;
        RECT 0.000 8.500 80.000 31.000 ;
    END
    PORT
      LAYER TopMetal2 ;
        RECT 0.000 127.500 80.000 132.500 ;
    END
  END iovss
  PIN pad
    DIRECTION INOUT ;
    USE SIGNAL ;
    PORT
      LAYER Metal2 ;
        RECT 5.000 0.000 75.000 3.000 ;
      LAYER Metal3 ;
        RECT 5.000 0.000 75.000 3.000 ;
      LAYER Metal4 ;
        RECT 5.000 0.000 75.000 3.000 ;
      LAYER Metal5 ;
        RECT 5.000 0.000 75.000 3.000 ;
      LAYER TopMetal1 ;
        RECT 5.000 0.000 75.000 3.000 ;
      LAYER TopMetal2 ;
        RECT 5.000 0.000 75.000 3.000 ;
    END
  END pad
  PIN vdd
    DIRECTION INOUT ;
    USE POWER ;
    PORT
      LAYER Metal3 ;
        RECT 0.000 160.000 80.000 178.000 ;
    END
    PORT
      LAYER Metal4 ;
        RECT 0.000 140.000 80.000 155.800 ;
    END
    PORT
      LAYER Metal5 ;
        RECT 0.000 140.000 80.000 158.000 ;
    END
    PORT
      LAYER TopMetal1 ;
        RECT 0.000 140.000 80.000 158.000 ;
    END
  END vdd
  PIN vss
    DIRECTION INOUT ;
    USE GROUND ;
    PORT
      LAYER Metal3 ;
        RECT 0.000 140.000 80.000 158.000 ;
    END
    PORT
      LAYER Metal4 ;
        RECT 0.000 162.200 80.000 178.000 ;
    END
    PORT
      LAYER Metal5 ;
        RECT 0.000 160.000 80.000 178.000 ;
    END
    PORT
      LAYER TopMetal1 ;
        RECT 0.000 160.000 80.000 178.000 ;
    END
  END vss
  OBS
    LAYER Metal1 ;
      RECT 0.000 0.000 80.000 180.000 ;
    LAYER Metal2 ;
      RECT 0.000 0.000 80.000 180.000 ;
    LAYER Metal3 ;
      RECT 0.000 0.000 80.000 178.000 ;
    LAYER Metal4 ;
      RECT 0.000 0.000 80.000 178.000 ;
    LAYER Metal5 ;
      RECT 0.000 0.000 80.000 178.000 ;
    LAYER TopMetal1 ;
      RECT 0.000 0.000 80.000 178.000 ;
    LAYER TopMetal2 ;
      RECT 0.000 0.000 80.000 132.500 ;
    LAYER Via1 ;
      RECT 0.000 0.000 80.000 180.000 ;
    LAYER Via2 ;
      RECT 0.000 0.000 80.000 180.000 ;
  END
END IOPadOut30mA

MACRO IOPadTriOut4mA
  CLASS PAD OUTPUT ;
  ORIGIN 0.000 0.000 ;
  FOREIGN IOPadTriOut4mA 0.000 0.000 ;
  SIZE 80.000 BY 180.000 ;
  SYMMETRY X Y R90 ;
  SITE IOLibSite ;
  PIN c2p
    DIRECTION INPUT ;
    USE SIGNAL ;
    PORT
      LAYER Metal2 ;
        RECT 38.330 178.090 38.620 180.000 ;
      LAYER Metal3 ;
        RECT 38.225 179.710 38.725 180.000 ;
    END
  END c2p
  PIN c2p_en
    DIRECTION INPUT ;
    USE SIGNAL ;
    PORT
      LAYER Metal2 ;
        RECT 41.380 174.045 41.670 180.000 ;
      LAYER Metal3 ;
        RECT 41.275 179.710 41.775 180.000 ;
    END
  END c2p_en
  PIN iovdd
    DIRECTION INOUT ;
    USE POWER ;
    PORT
      LAYER Metal3 ;
        RECT 0.000 93.500 80.000 119.000 ;
    END
    PORT
      LAYER Metal3 ;
        RECT 0.000 66.000 80.000 91.500 ;
    END
    PORT
      LAYER Metal4 ;
        RECT 0.000 93.500 80.000 119.000 ;
    END
    PORT
      LAYER Metal4 ;
        RECT 0.000 66.000 80.000 91.500 ;
    END
    PORT
      LAYER Metal5 ;
        RECT 0.000 93.500 80.000 119.000 ;
    END
    PORT
      LAYER Metal5 ;
        RECT 0.000 66.000 80.000 91.500 ;
    END
    PORT
      LAYER TopMetal1 ;
        RECT 0.000 93.500 80.000 119.000 ;
    END
    PORT
      LAYER TopMetal1 ;
        RECT 0.000 66.000 80.000 91.500 ;
    END
    PORT
      LAYER TopMetal2 ;
        RECT 0.000 95.000 80.000 117.500 ;
    END
    PORT
      LAYER TopMetal2 ;
        RECT 0.000 67.500 80.000 90.000 ;
    END
  END iovdd
  PIN iovss
    DIRECTION INOUT ;
    USE GROUND ;
    PORT
      LAYER Metal3 ;
        RECT 0.000 7.000 80.000 32.500 ;
    END
    PORT
      LAYER Metal3 ;
        RECT 0.000 126.000 80.000 134.000 ;
    END
    PORT
      LAYER Metal3 ;
        RECT 0.000 34.500 80.000 60.000 ;
    END
    PORT
      LAYER Metal4 ;
        RECT 0.000 7.000 80.000 32.500 ;
    END
    PORT
      LAYER Metal4 ;
        RECT 0.000 126.000 80.000 134.000 ;
    END
    PORT
      LAYER Metal4 ;
        RECT 0.000 34.500 80.000 60.000 ;
    END
    PORT
      LAYER Metal5 ;
        RECT 0.000 7.000 80.000 32.500 ;
    END
    PORT
      LAYER Metal5 ;
        RECT 0.000 126.000 80.000 134.000 ;
    END
    PORT
      LAYER Metal5 ;
        RECT 0.000 34.500 80.000 60.000 ;
    END
    PORT
      LAYER TopMetal1 ;
        RECT 0.000 7.000 80.000 32.500 ;
    END
    PORT
      LAYER TopMetal1 ;
        RECT 0.000 126.000 80.000 134.000 ;
    END
    PORT
      LAYER TopMetal1 ;
        RECT 0.000 34.500 80.000 60.000 ;
    END
    PORT
      LAYER TopMetal2 ;
        RECT 0.000 36.000 80.000 58.500 ;
    END
    PORT
      LAYER TopMetal2 ;
        RECT 0.000 8.500 80.000 31.000 ;
    END
    PORT
      LAYER TopMetal2 ;
        RECT 0.000 127.500 80.000 132.500 ;
    END
  END iovss
  PIN pad
    DIRECTION INOUT ;
    USE SIGNAL ;
    PORT
      LAYER Metal2 ;
        RECT 5.000 0.000 75.000 3.000 ;
      LAYER Metal3 ;
        RECT 5.000 0.000 75.000 3.000 ;
      LAYER Metal4 ;
        RECT 5.000 0.000 75.000 3.000 ;
      LAYER Metal5 ;
        RECT 5.000 0.000 75.000 3.000 ;
      LAYER TopMetal1 ;
        RECT 5.000 0.000 75.000 3.000 ;
      LAYER TopMetal2 ;
        RECT 5.000 0.000 75.000 3.000 ;
    END
  END pad
  PIN vdd
    DIRECTION INOUT ;
    USE POWER ;
    PORT
      LAYER Metal3 ;
        RECT 0.000 160.000 80.000 178.000 ;
    END
    PORT
      LAYER Metal4 ;
        RECT 0.000 140.000 80.000 155.800 ;
    END
    PORT
      LAYER Metal5 ;
        RECT 0.000 140.000 80.000 158.000 ;
    END
    PORT
      LAYER TopMetal1 ;
        RECT 0.000 140.000 80.000 158.000 ;
    END
  END vdd
  PIN vss
    DIRECTION INOUT ;
    USE GROUND ;
    PORT
      LAYER Metal3 ;
        RECT 0.000 140.000 80.000 158.000 ;
    END
    PORT
      LAYER Metal4 ;
        RECT 0.000 162.200 80.000 178.000 ;
    END
    PORT
      LAYER Metal5 ;
        RECT 0.000 160.000 80.000 178.000 ;
    END
    PORT
      LAYER TopMetal1 ;
        RECT 0.000 160.000 80.000 178.000 ;
    END
  END vss
  OBS
    LAYER Metal1 ;
      RECT 0.000 0.000 80.000 180.000 ;
    LAYER Metal2 ;
      RECT 0.000 0.000 80.000 180.000 ;
    LAYER Metal3 ;
      RECT 0.000 0.000 80.000 178.000 ;
    LAYER Metal4 ;
      RECT 0.000 0.000 80.000 178.000 ;
    LAYER Metal5 ;
      RECT 0.000 0.000 80.000 178.000 ;
    LAYER TopMetal1 ;
      RECT 0.000 0.000 80.000 178.000 ;
    LAYER TopMetal2 ;
      RECT 0.000 0.000 80.000 132.500 ;
    LAYER Via1 ;
      RECT 0.000 0.000 80.000 180.000 ;
    LAYER Via2 ;
      RECT 0.000 0.000 80.000 180.000 ;
  END
END IOPadTriOut4mA

MACRO IOPadTriOut8mA
  CLASS PAD OUTPUT ;
  ORIGIN 0.000 0.000 ;
  FOREIGN IOPadTriOut8mA 0.000 0.000 ;
  SIZE 80.000 BY 180.000 ;
  SYMMETRY X Y R90 ;
  SITE IOLibSite ;
  PIN c2p
    DIRECTION INPUT ;
    USE SIGNAL ;
    PORT
      LAYER Metal2 ;
        RECT 38.330 178.090 38.620 180.000 ;
      LAYER Metal3 ;
        RECT 38.225 179.710 38.725 180.000 ;
    END
  END c2p
  PIN c2p_en
    DIRECTION INPUT ;
    USE SIGNAL ;
    PORT
      LAYER Metal2 ;
        RECT 41.380 174.045 41.670 180.000 ;
      LAYER Metal3 ;
        RECT 41.275 179.710 41.775 180.000 ;
    END
  END c2p_en
  PIN iovdd
    DIRECTION INOUT ;
    USE POWER ;
    PORT
      LAYER Metal3 ;
        RECT 0.000 93.500 80.000 119.000 ;
    END
    PORT
      LAYER Metal3 ;
        RECT 0.000 66.000 80.000 91.500 ;
    END
    PORT
      LAYER Metal4 ;
        RECT 0.000 93.500 80.000 119.000 ;
    END
    PORT
      LAYER Metal4 ;
        RECT 0.000 66.000 80.000 91.500 ;
    END
    PORT
      LAYER Metal5 ;
        RECT 0.000 93.500 80.000 119.000 ;
    END
    PORT
      LAYER Metal5 ;
        RECT 0.000 66.000 80.000 91.500 ;
    END
    PORT
      LAYER TopMetal1 ;
        RECT 0.000 93.500 80.000 119.000 ;
    END
    PORT
      LAYER TopMetal1 ;
        RECT 0.000 66.000 80.000 91.500 ;
    END
    PORT
      LAYER TopMetal2 ;
        RECT 0.000 95.000 80.000 117.500 ;
    END
    PORT
      LAYER TopMetal2 ;
        RECT 0.000 67.500 80.000 90.000 ;
    END
  END iovdd
  PIN iovss
    DIRECTION INOUT ;
    USE GROUND ;
    PORT
      LAYER Metal3 ;
        RECT 0.000 7.000 80.000 32.500 ;
    END
    PORT
      LAYER Metal3 ;
        RECT 0.000 126.000 80.000 134.000 ;
    END
    PORT
      LAYER Metal3 ;
        RECT 0.000 34.500 80.000 60.000 ;
    END
    PORT
      LAYER Metal4 ;
        RECT 0.000 7.000 80.000 32.500 ;
    END
    PORT
      LAYER Metal4 ;
        RECT 0.000 126.000 80.000 134.000 ;
    END
    PORT
      LAYER Metal4 ;
        RECT 0.000 34.500 80.000 60.000 ;
    END
    PORT
      LAYER Metal5 ;
        RECT 0.000 7.000 80.000 32.500 ;
    END
    PORT
      LAYER Metal5 ;
        RECT 0.000 126.000 80.000 134.000 ;
    END
    PORT
      LAYER Metal5 ;
        RECT 0.000 34.500 80.000 60.000 ;
    END
    PORT
      LAYER TopMetal1 ;
        RECT 0.000 7.000 80.000 32.500 ;
    END
    PORT
      LAYER TopMetal1 ;
        RECT 0.000 126.000 80.000 134.000 ;
    END
    PORT
      LAYER TopMetal1 ;
        RECT 0.000 34.500 80.000 60.000 ;
    END
    PORT
      LAYER TopMetal2 ;
        RECT 0.000 36.000 80.000 58.500 ;
    END
    PORT
      LAYER TopMetal2 ;
        RECT 0.000 8.500 80.000 31.000 ;
    END
    PORT
      LAYER TopMetal2 ;
        RECT 0.000 127.500 80.000 132.500 ;
    END
  END iovss
  PIN pad
    DIRECTION INOUT ;
    USE SIGNAL ;
    PORT
      LAYER Metal2 ;
        RECT 5.000 0.000 75.000 3.000 ;
      LAYER Metal3 ;
        RECT 5.000 0.000 75.000 3.000 ;
      LAYER Metal4 ;
        RECT 5.000 0.000 75.000 3.000 ;
      LAYER Metal5 ;
        RECT 5.000 0.000 75.000 3.000 ;
      LAYER TopMetal1 ;
        RECT 5.000 0.000 75.000 3.000 ;
      LAYER TopMetal2 ;
        RECT 5.000 0.000 75.000 3.000 ;
    END
  END pad
  PIN vdd
    DIRECTION INOUT ;
    USE POWER ;
    PORT
      LAYER Metal3 ;
        RECT 0.000 160.000 80.000 178.000 ;
    END
    PORT
      LAYER Metal4 ;
        RECT 0.000 140.000 80.000 155.800 ;
    END
    PORT
      LAYER Metal5 ;
        RECT 0.000 140.000 80.000 158.000 ;
    END
    PORT
      LAYER TopMetal1 ;
        RECT 0.000 140.000 80.000 158.000 ;
    END
  END vdd
  PIN vss
    DIRECTION INOUT ;
    USE GROUND ;
    PORT
      LAYER Metal3 ;
        RECT 0.000 140.000 80.000 158.000 ;
    END
    PORT
      LAYER Metal4 ;
        RECT 0.000 162.200 80.000 178.000 ;
    END
    PORT
      LAYER Metal5 ;
        RECT 0.000 160.000 80.000 178.000 ;
    END
    PORT
      LAYER TopMetal1 ;
        RECT 0.000 160.000 80.000 178.000 ;
    END
  END vss
  OBS
    LAYER Metal1 ;
      RECT 0.000 0.000 80.000 180.000 ;
    LAYER Metal2 ;
      RECT 0.000 0.000 80.000 180.000 ;
    LAYER Metal3 ;
      RECT 0.000 0.000 80.000 178.000 ;
    LAYER Metal4 ;
      RECT 0.000 0.000 80.000 178.000 ;
    LAYER Metal5 ;
      RECT 0.000 0.000 80.000 178.000 ;
    LAYER TopMetal1 ;
      RECT 0.000 0.000 80.000 178.000 ;
    LAYER TopMetal2 ;
      RECT 0.000 0.000 80.000 132.500 ;
    LAYER Via1 ;
      RECT 0.000 0.000 80.000 180.000 ;
    LAYER Via2 ;
      RECT 0.000 0.000 80.000 180.000 ;
  END
END IOPadTriOut8mA

MACRO IOPadTriOut12mA
  CLASS PAD OUTPUT ;
  ORIGIN 0.000 0.000 ;
  FOREIGN IOPadTriOut12mA 0.000 0.000 ;
  SIZE 80.000 BY 180.000 ;
  SYMMETRY X Y R90 ;
  SITE IOLibSite ;
  PIN c2p
    DIRECTION INPUT ;
    USE SIGNAL ;
    PORT
      LAYER Metal2 ;
        RECT 38.330 178.090 38.620 180.000 ;
      LAYER Metal3 ;
        RECT 38.225 179.710 38.725 180.000 ;
    END
  END c2p
  PIN c2p_en
    DIRECTION INPUT ;
    USE SIGNAL ;
    PORT
      LAYER Metal2 ;
        RECT 41.380 174.045 41.670 180.000 ;
      LAYER Metal3 ;
        RECT 41.275 179.710 41.775 180.000 ;
    END
  END c2p_en
  PIN iovdd
    DIRECTION INOUT ;
    USE POWER ;
    PORT
      LAYER Metal3 ;
        RECT 0.000 93.500 80.000 119.000 ;
    END
    PORT
      LAYER Metal3 ;
        RECT 0.000 66.000 80.000 91.500 ;
    END
    PORT
      LAYER Metal4 ;
        RECT 0.000 93.500 80.000 119.000 ;
    END
    PORT
      LAYER Metal4 ;
        RECT 0.000 66.000 80.000 91.500 ;
    END
    PORT
      LAYER Metal5 ;
        RECT 0.000 93.500 80.000 119.000 ;
    END
    PORT
      LAYER Metal5 ;
        RECT 0.000 66.000 80.000 91.500 ;
    END
    PORT
      LAYER TopMetal1 ;
        RECT 0.000 93.500 80.000 119.000 ;
    END
    PORT
      LAYER TopMetal1 ;
        RECT 0.000 66.000 80.000 91.500 ;
    END
    PORT
      LAYER TopMetal2 ;
        RECT 0.000 95.000 80.000 117.500 ;
    END
    PORT
      LAYER TopMetal2 ;
        RECT 0.000 67.500 80.000 90.000 ;
    END
  END iovdd
  PIN iovss
    DIRECTION INOUT ;
    USE GROUND ;
    PORT
      LAYER Metal3 ;
        RECT 0.000 7.000 80.000 32.500 ;
    END
    PORT
      LAYER Metal3 ;
        RECT 0.000 126.000 80.000 134.000 ;
    END
    PORT
      LAYER Metal3 ;
        RECT 0.000 34.500 80.000 60.000 ;
    END
    PORT
      LAYER Metal4 ;
        RECT 0.000 7.000 80.000 32.500 ;
    END
    PORT
      LAYER Metal4 ;
        RECT 0.000 126.000 80.000 134.000 ;
    END
    PORT
      LAYER Metal4 ;
        RECT 0.000 34.500 80.000 60.000 ;
    END
    PORT
      LAYER Metal5 ;
        RECT 0.000 7.000 80.000 32.500 ;
    END
    PORT
      LAYER Metal5 ;
        RECT 0.000 126.000 80.000 134.000 ;
    END
    PORT
      LAYER Metal5 ;
        RECT 0.000 34.500 80.000 60.000 ;
    END
    PORT
      LAYER TopMetal1 ;
        RECT 0.000 7.000 80.000 32.500 ;
    END
    PORT
      LAYER TopMetal1 ;
        RECT 0.000 126.000 80.000 134.000 ;
    END
    PORT
      LAYER TopMetal1 ;
        RECT 0.000 34.500 80.000 60.000 ;
    END
    PORT
      LAYER TopMetal2 ;
        RECT 0.000 36.000 80.000 58.500 ;
    END
    PORT
      LAYER TopMetal2 ;
        RECT 0.000 8.500 80.000 31.000 ;
    END
    PORT
      LAYER TopMetal2 ;
        RECT 0.000 127.500 80.000 132.500 ;
    END
  END iovss
  PIN pad
    DIRECTION INOUT ;
    USE SIGNAL ;
    PORT
      LAYER Metal2 ;
        RECT 5.000 0.000 75.000 3.000 ;
      LAYER Metal3 ;
        RECT 5.000 0.000 75.000 3.000 ;
      LAYER Metal4 ;
        RECT 5.000 0.000 75.000 3.000 ;
      LAYER Metal5 ;
        RECT 5.000 0.000 75.000 3.000 ;
      LAYER TopMetal1 ;
        RECT 5.000 0.000 75.000 3.000 ;
      LAYER TopMetal2 ;
        RECT 5.000 0.000 75.000 3.000 ;
    END
  END pad
  PIN vdd
    DIRECTION INOUT ;
    USE POWER ;
    PORT
      LAYER Metal3 ;
        RECT 0.000 160.000 80.000 178.000 ;
    END
    PORT
      LAYER Metal4 ;
        RECT 0.000 140.000 80.000 155.800 ;
    END
    PORT
      LAYER Metal5 ;
        RECT 0.000 140.000 80.000 158.000 ;
    END
    PORT
      LAYER TopMetal1 ;
        RECT 0.000 140.000 80.000 158.000 ;
    END
  END vdd
  PIN vss
    DIRECTION INOUT ;
    USE GROUND ;
    PORT
      LAYER Metal3 ;
        RECT 0.000 140.000 80.000 158.000 ;
    END
    PORT
      LAYER Metal4 ;
        RECT 0.000 162.200 80.000 178.000 ;
    END
    PORT
      LAYER Metal5 ;
        RECT 0.000 160.000 80.000 178.000 ;
    END
    PORT
      LAYER TopMetal1 ;
        RECT 0.000 160.000 80.000 178.000 ;
    END
  END vss
  OBS
    LAYER Metal1 ;
      RECT 0.000 0.000 80.000 180.000 ;
    LAYER Metal2 ;
      RECT 0.000 0.000 80.000 180.000 ;
    LAYER Metal3 ;
      RECT 0.000 0.000 80.000 178.000 ;
    LAYER Metal4 ;
      RECT 0.000 0.000 80.000 178.000 ;
    LAYER Metal5 ;
      RECT 0.000 0.000 80.000 178.000 ;
    LAYER TopMetal1 ;
      RECT 0.000 0.000 80.000 178.000 ;
    LAYER TopMetal2 ;
      RECT 0.000 0.000 80.000 132.500 ;
    LAYER Via1 ;
      RECT 0.000 0.000 80.000 180.000 ;
    LAYER Via2 ;
      RECT 0.000 0.000 80.000 180.000 ;
  END
END IOPadTriOut12mA

MACRO IOPadTriOut16mA
  CLASS PAD OUTPUT ;
  ORIGIN 0.000 0.000 ;
  FOREIGN IOPadTriOut16mA 0.000 0.000 ;
  SIZE 80.000 BY 180.000 ;
  SYMMETRY X Y R90 ;
  SITE IOLibSite ;
  PIN c2p
    DIRECTION INPUT ;
    USE SIGNAL ;
    PORT
      LAYER Metal2 ;
        RECT 38.330 178.090 38.620 180.000 ;
      LAYER Metal3 ;
        RECT 38.225 179.710 38.725 180.000 ;
    END
  END c2p
  PIN c2p_en
    DIRECTION INPUT ;
    USE SIGNAL ;
    PORT
      LAYER Metal2 ;
        RECT 41.380 174.045 41.670 180.000 ;
      LAYER Metal3 ;
        RECT 41.275 179.710 41.775 180.000 ;
    END
  END c2p_en
  PIN iovdd
    DIRECTION INOUT ;
    USE POWER ;
    PORT
      LAYER Metal3 ;
        RECT 0.000 93.500 80.000 119.000 ;
    END
    PORT
      LAYER Metal3 ;
        RECT 0.000 66.000 80.000 91.500 ;
    END
    PORT
      LAYER Metal4 ;
        RECT 0.000 93.500 80.000 119.000 ;
    END
    PORT
      LAYER Metal4 ;
        RECT 0.000 66.000 80.000 91.500 ;
    END
    PORT
      LAYER Metal5 ;
        RECT 0.000 93.500 80.000 119.000 ;
    END
    PORT
      LAYER Metal5 ;
        RECT 0.000 66.000 80.000 91.500 ;
    END
    PORT
      LAYER TopMetal1 ;
        RECT 0.000 93.500 80.000 119.000 ;
    END
    PORT
      LAYER TopMetal1 ;
        RECT 0.000 66.000 80.000 91.500 ;
    END
    PORT
      LAYER TopMetal2 ;
        RECT 0.000 95.000 80.000 117.500 ;
    END
    PORT
      LAYER TopMetal2 ;
        RECT 0.000 67.500 80.000 90.000 ;
    END
  END iovdd
  PIN iovss
    DIRECTION INOUT ;
    USE GROUND ;
    PORT
      LAYER Metal3 ;
        RECT 0.000 7.000 80.000 32.500 ;
    END
    PORT
      LAYER Metal3 ;
        RECT 0.000 126.000 80.000 134.000 ;
    END
    PORT
      LAYER Metal3 ;
        RECT 0.000 34.500 80.000 60.000 ;
    END
    PORT
      LAYER Metal4 ;
        RECT 0.000 7.000 80.000 32.500 ;
    END
    PORT
      LAYER Metal4 ;
        RECT 0.000 126.000 80.000 134.000 ;
    END
    PORT
      LAYER Metal4 ;
        RECT 0.000 34.500 80.000 60.000 ;
    END
    PORT
      LAYER Metal5 ;
        RECT 0.000 7.000 80.000 32.500 ;
    END
    PORT
      LAYER Metal5 ;
        RECT 0.000 126.000 80.000 134.000 ;
    END
    PORT
      LAYER Metal5 ;
        RECT 0.000 34.500 80.000 60.000 ;
    END
    PORT
      LAYER TopMetal1 ;
        RECT 0.000 7.000 80.000 32.500 ;
    END
    PORT
      LAYER TopMetal1 ;
        RECT 0.000 126.000 80.000 134.000 ;
    END
    PORT
      LAYER TopMetal1 ;
        RECT 0.000 34.500 80.000 60.000 ;
    END
    PORT
      LAYER TopMetal2 ;
        RECT 0.000 36.000 80.000 58.500 ;
    END
    PORT
      LAYER TopMetal2 ;
        RECT 0.000 8.500 80.000 31.000 ;
    END
    PORT
      LAYER TopMetal2 ;
        RECT 0.000 127.500 80.000 132.500 ;
    END
  END iovss
  PIN pad
    DIRECTION INOUT ;
    USE SIGNAL ;
    PORT
      LAYER Metal2 ;
        RECT 5.000 0.000 75.000 3.000 ;
      LAYER Metal3 ;
        RECT 5.000 0.000 75.000 3.000 ;
      LAYER Metal4 ;
        RECT 5.000 0.000 75.000 3.000 ;
      LAYER Metal5 ;
        RECT 5.000 0.000 75.000 3.000 ;
      LAYER TopMetal1 ;
        RECT 5.000 0.000 75.000 3.000 ;
      LAYER TopMetal2 ;
        RECT 5.000 0.000 75.000 3.000 ;
    END
  END pad
  PIN vdd
    DIRECTION INOUT ;
    USE POWER ;
    PORT
      LAYER Metal3 ;
        RECT 0.000 160.000 80.000 178.000 ;
    END
    PORT
      LAYER Metal4 ;
        RECT 0.000 140.000 80.000 155.800 ;
    END
    PORT
      LAYER Metal5 ;
        RECT 0.000 140.000 80.000 158.000 ;
    END
    PORT
      LAYER TopMetal1 ;
        RECT 0.000 140.000 80.000 158.000 ;
    END
  END vdd
  PIN vss
    DIRECTION INOUT ;
    USE GROUND ;
    PORT
      LAYER Metal3 ;
        RECT 0.000 140.000 80.000 158.000 ;
    END
    PORT
      LAYER Metal4 ;
        RECT 0.000 162.200 80.000 178.000 ;
    END
    PORT
      LAYER Metal5 ;
        RECT 0.000 160.000 80.000 178.000 ;
    END
    PORT
      LAYER TopMetal1 ;
        RECT 0.000 160.000 80.000 178.000 ;
    END
  END vss
  OBS
    LAYER Metal1 ;
      RECT 0.000 0.000 80.000 180.000 ;
    LAYER Metal2 ;
      RECT 0.000 0.000 80.000 180.000 ;
    LAYER Metal3 ;
      RECT 0.000 0.000 80.000 178.000 ;
    LAYER Metal4 ;
      RECT 0.000 0.000 80.000 178.000 ;
    LAYER Metal5 ;
      RECT 0.000 0.000 80.000 178.000 ;
    LAYER TopMetal1 ;
      RECT 0.000 0.000 80.000 178.000 ;
    LAYER TopMetal2 ;
      RECT 0.000 0.000 80.000 132.500 ;
    LAYER Via1 ;
      RECT 0.000 0.000 80.000 180.000 ;
    LAYER Via2 ;
      RECT 0.000 0.000 80.000 180.000 ;
  END
END IOPadTriOut16mA

MACRO IOPadTriOut20mA
  CLASS PAD OUTPUT ;
  ORIGIN 0.000 0.000 ;
  FOREIGN IOPadTriOut20mA 0.000 0.000 ;
  SIZE 80.000 BY 180.000 ;
  SYMMETRY X Y R90 ;
  SITE IOLibSite ;
  PIN c2p
    DIRECTION INPUT ;
    USE SIGNAL ;
    PORT
      LAYER Metal2 ;
        RECT 38.330 178.090 38.620 180.000 ;
      LAYER Metal3 ;
        RECT 38.225 179.710 38.725 180.000 ;
    END
  END c2p
  PIN c2p_en
    DIRECTION INPUT ;
    USE SIGNAL ;
    PORT
      LAYER Metal2 ;
        RECT 41.380 174.045 41.670 180.000 ;
      LAYER Metal3 ;
        RECT 41.275 179.710 41.775 180.000 ;
    END
  END c2p_en
  PIN iovdd
    DIRECTION INOUT ;
    USE POWER ;
    PORT
      LAYER Metal3 ;
        RECT 0.000 93.500 80.000 119.000 ;
    END
    PORT
      LAYER Metal3 ;
        RECT 0.000 66.000 80.000 91.500 ;
    END
    PORT
      LAYER Metal4 ;
        RECT 0.000 93.500 80.000 119.000 ;
    END
    PORT
      LAYER Metal4 ;
        RECT 0.000 66.000 80.000 91.500 ;
    END
    PORT
      LAYER Metal5 ;
        RECT 0.000 93.500 80.000 119.000 ;
    END
    PORT
      LAYER Metal5 ;
        RECT 0.000 66.000 80.000 91.500 ;
    END
    PORT
      LAYER TopMetal1 ;
        RECT 0.000 93.500 80.000 119.000 ;
    END
    PORT
      LAYER TopMetal1 ;
        RECT 0.000 66.000 80.000 91.500 ;
    END
    PORT
      LAYER TopMetal2 ;
        RECT 0.000 95.000 80.000 117.500 ;
    END
    PORT
      LAYER TopMetal2 ;
        RECT 0.000 67.500 80.000 90.000 ;
    END
  END iovdd
  PIN iovss
    DIRECTION INOUT ;
    USE GROUND ;
    PORT
      LAYER Metal3 ;
        RECT 0.000 7.000 80.000 32.500 ;
    END
    PORT
      LAYER Metal3 ;
        RECT 0.000 126.000 80.000 134.000 ;
    END
    PORT
      LAYER Metal3 ;
        RECT 0.000 34.500 80.000 60.000 ;
    END
    PORT
      LAYER Metal4 ;
        RECT 0.000 7.000 80.000 32.500 ;
    END
    PORT
      LAYER Metal4 ;
        RECT 0.000 126.000 80.000 134.000 ;
    END
    PORT
      LAYER Metal4 ;
        RECT 0.000 34.500 80.000 60.000 ;
    END
    PORT
      LAYER Metal5 ;
        RECT 0.000 7.000 80.000 32.500 ;
    END
    PORT
      LAYER Metal5 ;
        RECT 0.000 126.000 80.000 134.000 ;
    END
    PORT
      LAYER Metal5 ;
        RECT 0.000 34.500 80.000 60.000 ;
    END
    PORT
      LAYER TopMetal1 ;
        RECT 0.000 7.000 80.000 32.500 ;
    END
    PORT
      LAYER TopMetal1 ;
        RECT 0.000 126.000 80.000 134.000 ;
    END
    PORT
      LAYER TopMetal1 ;
        RECT 0.000 34.500 80.000 60.000 ;
    END
    PORT
      LAYER TopMetal2 ;
        RECT 0.000 36.000 80.000 58.500 ;
    END
    PORT
      LAYER TopMetal2 ;
        RECT 0.000 8.500 80.000 31.000 ;
    END
    PORT
      LAYER TopMetal2 ;
        RECT 0.000 127.500 80.000 132.500 ;
    END
  END iovss
  PIN pad
    DIRECTION INOUT ;
    USE SIGNAL ;
    PORT
      LAYER Metal2 ;
        RECT 5.000 0.000 75.000 3.000 ;
      LAYER Metal3 ;
        RECT 5.000 0.000 75.000 3.000 ;
      LAYER Metal4 ;
        RECT 5.000 0.000 75.000 3.000 ;
      LAYER Metal5 ;
        RECT 5.000 0.000 75.000 3.000 ;
      LAYER TopMetal1 ;
        RECT 5.000 0.000 75.000 3.000 ;
      LAYER TopMetal2 ;
        RECT 5.000 0.000 75.000 3.000 ;
    END
  END pad
  PIN vdd
    DIRECTION INOUT ;
    USE POWER ;
    PORT
      LAYER Metal3 ;
        RECT 0.000 160.000 80.000 178.000 ;
    END
    PORT
      LAYER Metal4 ;
        RECT 0.000 140.000 80.000 155.800 ;
    END
    PORT
      LAYER Metal5 ;
        RECT 0.000 140.000 80.000 158.000 ;
    END
    PORT
      LAYER TopMetal1 ;
        RECT 0.000 140.000 80.000 158.000 ;
    END
  END vdd
  PIN vss
    DIRECTION INOUT ;
    USE GROUND ;
    PORT
      LAYER Metal3 ;
        RECT 0.000 140.000 80.000 158.000 ;
    END
    PORT
      LAYER Metal4 ;
        RECT 0.000 162.200 80.000 178.000 ;
    END
    PORT
      LAYER Metal5 ;
        RECT 0.000 160.000 80.000 178.000 ;
    END
    PORT
      LAYER TopMetal1 ;
        RECT 0.000 160.000 80.000 178.000 ;
    END
  END vss
  OBS
    LAYER Metal1 ;
      RECT 0.000 0.000 80.000 180.000 ;
    LAYER Metal2 ;
      RECT 0.000 0.000 80.000 180.000 ;
    LAYER Metal3 ;
      RECT 0.000 0.000 80.000 178.000 ;
    LAYER Metal4 ;
      RECT 0.000 0.000 80.000 178.000 ;
    LAYER Metal5 ;
      RECT 0.000 0.000 80.000 178.000 ;
    LAYER TopMetal1 ;
      RECT 0.000 0.000 80.000 178.000 ;
    LAYER TopMetal2 ;
      RECT 0.000 0.000 80.000 132.500 ;
    LAYER Via1 ;
      RECT 0.000 0.000 80.000 180.000 ;
    LAYER Via2 ;
      RECT 0.000 0.000 80.000 180.000 ;
  END
END IOPadTriOut20mA

MACRO IOPadTriOut24mA
  CLASS PAD OUTPUT ;
  ORIGIN 0.000 0.000 ;
  FOREIGN IOPadTriOut24mA 0.000 0.000 ;
  SIZE 80.000 BY 180.000 ;
  SYMMETRY X Y R90 ;
  SITE IOLibSite ;
  PIN c2p
    DIRECTION INPUT ;
    USE SIGNAL ;
    PORT
      LAYER Metal2 ;
        RECT 38.330 178.090 38.620 180.000 ;
      LAYER Metal3 ;
        RECT 38.225 179.710 38.725 180.000 ;
    END
  END c2p
  PIN c2p_en
    DIRECTION INPUT ;
    USE SIGNAL ;
    PORT
      LAYER Metal2 ;
        RECT 41.380 174.045 41.670 180.000 ;
      LAYER Metal3 ;
        RECT 41.275 179.710 41.775 180.000 ;
    END
  END c2p_en
  PIN iovdd
    DIRECTION INOUT ;
    USE POWER ;
    PORT
      LAYER Metal3 ;
        RECT 0.000 93.500 80.000 119.000 ;
    END
    PORT
      LAYER Metal3 ;
        RECT 0.000 66.000 80.000 91.500 ;
    END
    PORT
      LAYER Metal4 ;
        RECT 0.000 93.500 80.000 119.000 ;
    END
    PORT
      LAYER Metal4 ;
        RECT 0.000 66.000 80.000 91.500 ;
    END
    PORT
      LAYER Metal5 ;
        RECT 0.000 93.500 80.000 119.000 ;
    END
    PORT
      LAYER Metal5 ;
        RECT 0.000 66.000 80.000 91.500 ;
    END
    PORT
      LAYER TopMetal1 ;
        RECT 0.000 93.500 80.000 119.000 ;
    END
    PORT
      LAYER TopMetal1 ;
        RECT 0.000 66.000 80.000 91.500 ;
    END
    PORT
      LAYER TopMetal2 ;
        RECT 0.000 95.000 80.000 117.500 ;
    END
    PORT
      LAYER TopMetal2 ;
        RECT 0.000 67.500 80.000 90.000 ;
    END
  END iovdd
  PIN iovss
    DIRECTION INOUT ;
    USE GROUND ;
    PORT
      LAYER Metal3 ;
        RECT 0.000 7.000 80.000 32.500 ;
    END
    PORT
      LAYER Metal3 ;
        RECT 0.000 126.000 80.000 134.000 ;
    END
    PORT
      LAYER Metal3 ;
        RECT 0.000 34.500 80.000 60.000 ;
    END
    PORT
      LAYER Metal4 ;
        RECT 0.000 7.000 80.000 32.500 ;
    END
    PORT
      LAYER Metal4 ;
        RECT 0.000 126.000 80.000 134.000 ;
    END
    PORT
      LAYER Metal4 ;
        RECT 0.000 34.500 80.000 60.000 ;
    END
    PORT
      LAYER Metal5 ;
        RECT 0.000 7.000 80.000 32.500 ;
    END
    PORT
      LAYER Metal5 ;
        RECT 0.000 126.000 80.000 134.000 ;
    END
    PORT
      LAYER Metal5 ;
        RECT 0.000 34.500 80.000 60.000 ;
    END
    PORT
      LAYER TopMetal1 ;
        RECT 0.000 7.000 80.000 32.500 ;
    END
    PORT
      LAYER TopMetal1 ;
        RECT 0.000 126.000 80.000 134.000 ;
    END
    PORT
      LAYER TopMetal1 ;
        RECT 0.000 34.500 80.000 60.000 ;
    END
    PORT
      LAYER TopMetal2 ;
        RECT 0.000 36.000 80.000 58.500 ;
    END
    PORT
      LAYER TopMetal2 ;
        RECT 0.000 8.500 80.000 31.000 ;
    END
    PORT
      LAYER TopMetal2 ;
        RECT 0.000 127.500 80.000 132.500 ;
    END
  END iovss
  PIN pad
    DIRECTION INOUT ;
    USE SIGNAL ;
    PORT
      LAYER Metal2 ;
        RECT 5.000 0.000 75.000 3.000 ;
      LAYER Metal3 ;
        RECT 5.000 0.000 75.000 3.000 ;
      LAYER Metal4 ;
        RECT 5.000 0.000 75.000 3.000 ;
      LAYER Metal5 ;
        RECT 5.000 0.000 75.000 3.000 ;
      LAYER TopMetal1 ;
        RECT 5.000 0.000 75.000 3.000 ;
      LAYER TopMetal2 ;
        RECT 5.000 0.000 75.000 3.000 ;
    END
  END pad
  PIN vdd
    DIRECTION INOUT ;
    USE POWER ;
    PORT
      LAYER Metal3 ;
        RECT 0.000 160.000 80.000 178.000 ;
    END
    PORT
      LAYER Metal4 ;
        RECT 0.000 140.000 80.000 155.800 ;
    END
    PORT
      LAYER Metal5 ;
        RECT 0.000 140.000 80.000 158.000 ;
    END
    PORT
      LAYER TopMetal1 ;
        RECT 0.000 140.000 80.000 158.000 ;
    END
  END vdd
  PIN vss
    DIRECTION INOUT ;
    USE GROUND ;
    PORT
      LAYER Metal3 ;
        RECT 0.000 140.000 80.000 158.000 ;
    END
    PORT
      LAYER Metal4 ;
        RECT 0.000 162.200 80.000 178.000 ;
    END
    PORT
      LAYER Metal5 ;
        RECT 0.000 160.000 80.000 178.000 ;
    END
    PORT
      LAYER TopMetal1 ;
        RECT 0.000 160.000 80.000 178.000 ;
    END
  END vss
  OBS
    LAYER Metal1 ;
      RECT 0.000 0.000 80.000 180.000 ;
    LAYER Metal2 ;
      RECT 0.000 0.000 80.000 180.000 ;
    LAYER Metal3 ;
      RECT 0.000 0.000 80.000 178.000 ;
    LAYER Metal4 ;
      RECT 0.000 0.000 80.000 178.000 ;
    LAYER Metal5 ;
      RECT 0.000 0.000 80.000 178.000 ;
    LAYER TopMetal1 ;
      RECT 0.000 0.000 80.000 178.000 ;
    LAYER TopMetal2 ;
      RECT 0.000 0.000 80.000 132.500 ;
    LAYER Via1 ;
      RECT 0.000 0.000 80.000 180.000 ;
    LAYER Via2 ;
      RECT 0.000 0.000 80.000 180.000 ;
  END
END IOPadTriOut24mA

MACRO IOPadTriOut30mA
  CLASS PAD OUTPUT ;
  ORIGIN 0.000 0.000 ;
  FOREIGN IOPadTriOut30mA 0.000 0.000 ;
  SIZE 80.000 BY 180.000 ;
  SYMMETRY X Y R90 ;
  SITE IOLibSite ;
  PIN c2p
    DIRECTION INPUT ;
    USE SIGNAL ;
    PORT
      LAYER Metal2 ;
        RECT 38.330 178.090 38.620 180.000 ;
      LAYER Metal3 ;
        RECT 38.225 179.710 38.725 180.000 ;
    END
  END c2p
  PIN c2p_en
    DIRECTION INPUT ;
    USE SIGNAL ;
    PORT
      LAYER Metal2 ;
        RECT 41.380 174.045 41.670 180.000 ;
      LAYER Metal3 ;
        RECT 41.275 179.710 41.775 180.000 ;
    END
  END c2p_en
  PIN iovdd
    DIRECTION INOUT ;
    USE POWER ;
    PORT
      LAYER Metal3 ;
        RECT 0.000 93.500 80.000 119.000 ;
    END
    PORT
      LAYER Metal3 ;
        RECT 0.000 66.000 80.000 91.500 ;
    END
    PORT
      LAYER Metal4 ;
        RECT 0.000 93.500 80.000 119.000 ;
    END
    PORT
      LAYER Metal4 ;
        RECT 0.000 66.000 80.000 91.500 ;
    END
    PORT
      LAYER Metal5 ;
        RECT 0.000 93.500 80.000 119.000 ;
    END
    PORT
      LAYER Metal5 ;
        RECT 0.000 66.000 80.000 91.500 ;
    END
    PORT
      LAYER TopMetal1 ;
        RECT 0.000 93.500 80.000 119.000 ;
    END
    PORT
      LAYER TopMetal1 ;
        RECT 0.000 66.000 80.000 91.500 ;
    END
    PORT
      LAYER TopMetal2 ;
        RECT 0.000 95.000 80.000 117.500 ;
    END
    PORT
      LAYER TopMetal2 ;
        RECT 0.000 67.500 80.000 90.000 ;
    END
  END iovdd
  PIN iovss
    DIRECTION INOUT ;
    USE GROUND ;
    PORT
      LAYER Metal3 ;
        RECT 0.000 7.000 80.000 32.500 ;
    END
    PORT
      LAYER Metal3 ;
        RECT 0.000 126.000 80.000 134.000 ;
    END
    PORT
      LAYER Metal3 ;
        RECT 0.000 34.500 80.000 60.000 ;
    END
    PORT
      LAYER Metal4 ;
        RECT 0.000 7.000 80.000 32.500 ;
    END
    PORT
      LAYER Metal4 ;
        RECT 0.000 126.000 80.000 134.000 ;
    END
    PORT
      LAYER Metal4 ;
        RECT 0.000 34.500 80.000 60.000 ;
    END
    PORT
      LAYER Metal5 ;
        RECT 0.000 7.000 80.000 32.500 ;
    END
    PORT
      LAYER Metal5 ;
        RECT 0.000 126.000 80.000 134.000 ;
    END
    PORT
      LAYER Metal5 ;
        RECT 0.000 34.500 80.000 60.000 ;
    END
    PORT
      LAYER TopMetal1 ;
        RECT 0.000 7.000 80.000 32.500 ;
    END
    PORT
      LAYER TopMetal1 ;
        RECT 0.000 126.000 80.000 134.000 ;
    END
    PORT
      LAYER TopMetal1 ;
        RECT 0.000 34.500 80.000 60.000 ;
    END
    PORT
      LAYER TopMetal2 ;
        RECT 0.000 36.000 80.000 58.500 ;
    END
    PORT
      LAYER TopMetal2 ;
        RECT 0.000 8.500 80.000 31.000 ;
    END
    PORT
      LAYER TopMetal2 ;
        RECT 0.000 127.500 80.000 132.500 ;
    END
  END iovss
  PIN pad
    DIRECTION INOUT ;
    USE SIGNAL ;
    PORT
      LAYER Metal2 ;
        RECT 5.000 0.000 75.000 3.000 ;
      LAYER Metal3 ;
        RECT 5.000 0.000 75.000 3.000 ;
      LAYER Metal4 ;
        RECT 5.000 0.000 75.000 3.000 ;
      LAYER Metal5 ;
        RECT 5.000 0.000 75.000 3.000 ;
      LAYER TopMetal1 ;
        RECT 5.000 0.000 75.000 3.000 ;
      LAYER TopMetal2 ;
        RECT 5.000 0.000 75.000 3.000 ;
    END
  END pad
  PIN vdd
    DIRECTION INOUT ;
    USE POWER ;
    PORT
      LAYER Metal3 ;
        RECT 0.000 160.000 80.000 178.000 ;
    END
    PORT
      LAYER Metal4 ;
        RECT 0.000 140.000 80.000 155.800 ;
    END
    PORT
      LAYER Metal5 ;
        RECT 0.000 140.000 80.000 158.000 ;
    END
    PORT
      LAYER TopMetal1 ;
        RECT 0.000 140.000 80.000 158.000 ;
    END
  END vdd
  PIN vss
    DIRECTION INOUT ;
    USE GROUND ;
    PORT
      LAYER Metal3 ;
        RECT 0.000 140.000 80.000 158.000 ;
    END
    PORT
      LAYER Metal4 ;
        RECT 0.000 162.200 80.000 178.000 ;
    END
    PORT
      LAYER Metal5 ;
        RECT 0.000 160.000 80.000 178.000 ;
    END
    PORT
      LAYER TopMetal1 ;
        RECT 0.000 160.000 80.000 178.000 ;
    END
  END vss
  OBS
    LAYER Metal1 ;
      RECT 0.000 0.000 80.000 180.000 ;
    LAYER Metal2 ;
      RECT 0.000 0.000 80.000 180.000 ;
    LAYER Metal3 ;
      RECT 0.000 0.000 80.000 178.000 ;
    LAYER Metal4 ;
      RECT 0.000 0.000 80.000 178.000 ;
    LAYER Metal5 ;
      RECT 0.000 0.000 80.000 178.000 ;
    LAYER TopMetal1 ;
      RECT 0.000 0.000 80.000 178.000 ;
    LAYER TopMetal2 ;
      RECT 0.000 0.000 80.000 132.500 ;
    LAYER Via1 ;
      RECT 0.000 0.000 80.000 180.000 ;
    LAYER Via2 ;
      RECT 0.000 0.000 80.000 180.000 ;
  END
END IOPadTriOut30mA

MACRO IOPadInOut4mA
  CLASS PAD INOUT ;
  ORIGIN 0.000 0.000 ;
  FOREIGN IOPadInOut4mA 0.000 0.000 ;
  SIZE 80.000 BY 180.000 ;
  SYMMETRY X Y R90 ;
  SITE IOLibSite ;
  PIN c2p
    DIRECTION INPUT ;
    USE SIGNAL ;
    PORT
      LAYER Metal2 ;
        RECT 18.330 178.090 18.620 180.000 ;
      LAYER Metal3 ;
        RECT 18.225 179.710 18.725 180.000 ;
    END
  END c2p
  PIN c2p_en
    DIRECTION INPUT ;
    USE SIGNAL ;
    PORT
      LAYER Metal2 ;
        RECT 21.380 174.045 21.670 180.000 ;
      LAYER Metal3 ;
        RECT 21.275 179.710 21.775 180.000 ;
    END
  END c2p_en
  PIN iovdd
    DIRECTION INOUT ;
    USE POWER ;
    PORT
      LAYER Metal3 ;
        RECT 0.000 93.500 80.000 119.000 ;
    END
    PORT
      LAYER Metal3 ;
        RECT 0.000 66.000 80.000 91.500 ;
    END
    PORT
      LAYER Metal4 ;
        RECT 0.000 93.500 80.000 119.000 ;
    END
    PORT
      LAYER Metal4 ;
        RECT 0.000 66.000 80.000 91.500 ;
    END
    PORT
      LAYER Metal5 ;
        RECT 0.000 93.500 80.000 119.000 ;
    END
    PORT
      LAYER Metal5 ;
        RECT 0.000 66.000 80.000 91.500 ;
    END
    PORT
      LAYER TopMetal1 ;
        RECT 0.000 93.500 80.000 119.000 ;
    END
    PORT
      LAYER TopMetal1 ;
        RECT 0.000 66.000 80.000 91.500 ;
    END
    PORT
      LAYER TopMetal2 ;
        RECT 0.000 95.000 80.000 117.500 ;
    END
    PORT
      LAYER TopMetal2 ;
        RECT 0.000 67.500 80.000 90.000 ;
    END
  END iovdd
  PIN iovss
    DIRECTION INOUT ;
    USE GROUND ;
    PORT
      LAYER Metal3 ;
        RECT 0.000 7.000 80.000 32.500 ;
    END
    PORT
      LAYER Metal3 ;
        RECT 0.000 126.000 80.000 134.000 ;
    END
    PORT
      LAYER Metal3 ;
        RECT 0.000 34.500 80.000 60.000 ;
    END
    PORT
      LAYER Metal4 ;
        RECT 0.000 7.000 80.000 32.500 ;
    END
    PORT
      LAYER Metal4 ;
        RECT 0.000 126.000 80.000 134.000 ;
    END
    PORT
      LAYER Metal4 ;
        RECT 0.000 34.500 80.000 60.000 ;
    END
    PORT
      LAYER Metal5 ;
        RECT 0.000 7.000 80.000 32.500 ;
    END
    PORT
      LAYER Metal5 ;
        RECT 0.000 126.000 80.000 134.000 ;
    END
    PORT
      LAYER Metal5 ;
        RECT 0.000 34.500 80.000 60.000 ;
    END
    PORT
      LAYER TopMetal1 ;
        RECT 0.000 7.000 80.000 32.500 ;
    END
    PORT
      LAYER TopMetal1 ;
        RECT 0.000 126.000 80.000 134.000 ;
    END
    PORT
      LAYER TopMetal1 ;
        RECT 0.000 34.500 80.000 60.000 ;
    END
    PORT
      LAYER TopMetal2 ;
        RECT 0.000 36.000 80.000 58.500 ;
    END
    PORT
      LAYER TopMetal2 ;
        RECT 0.000 8.500 80.000 31.000 ;
    END
    PORT
      LAYER TopMetal2 ;
        RECT 0.000 127.500 80.000 132.500 ;
    END
  END iovss
  PIN p2c
    DIRECTION OUTPUT ;
    USE SIGNAL ;
    PORT
      LAYER Metal2 ;
        RECT 59.830 157.810 60.120 180.000 ;
      LAYER Metal3 ;
        RECT 59.725 179.710 60.225 180.000 ;
    END
  END p2c
  PIN pad
    DIRECTION INOUT ;
    USE SIGNAL ;
    PORT
      LAYER Metal2 ;
        RECT 5.000 0.000 75.000 3.000 ;
      LAYER Metal3 ;
        RECT 5.000 0.000 75.000 3.000 ;
      LAYER Metal4 ;
        RECT 5.000 0.000 75.000 3.000 ;
      LAYER Metal5 ;
        RECT 5.000 0.000 75.000 3.000 ;
      LAYER TopMetal1 ;
        RECT 5.000 0.000 75.000 3.000 ;
      LAYER TopMetal2 ;
        RECT 5.000 0.000 75.000 3.000 ;
    END
  END pad
  PIN vdd
    DIRECTION INOUT ;
    USE POWER ;
    PORT
      LAYER Metal3 ;
        RECT 0.000 160.000 80.000 178.000 ;
    END
    PORT
      LAYER Metal4 ;
        RECT 0.000 140.000 80.000 155.800 ;
    END
    PORT
      LAYER Metal5 ;
        RECT 0.000 140.000 80.000 158.000 ;
    END
    PORT
      LAYER TopMetal1 ;
        RECT 0.000 140.000 80.000 158.000 ;
    END
  END vdd
  PIN vss
    DIRECTION INOUT ;
    USE GROUND ;
    PORT
      LAYER Metal3 ;
        RECT 0.000 140.000 80.000 158.000 ;
    END
    PORT
      LAYER Metal4 ;
        RECT 0.000 162.200 80.000 178.000 ;
    END
    PORT
      LAYER Metal5 ;
        RECT 0.000 160.000 80.000 178.000 ;
    END
    PORT
      LAYER TopMetal1 ;
        RECT 0.000 160.000 80.000 178.000 ;
    END
  END vss
  OBS
    LAYER Metal1 ;
      RECT 0.000 0.000 80.000 180.000 ;
    LAYER Metal2 ;
      RECT 0.000 0.000 80.000 180.000 ;
    LAYER Metal3 ;
      RECT 0.000 0.000 80.000 178.000 ;
    LAYER Metal4 ;
      RECT 0.000 0.000 80.000 178.000 ;
    LAYER Metal5 ;
      RECT 0.000 0.000 80.000 178.000 ;
    LAYER TopMetal1 ;
      RECT 0.000 0.000 80.000 178.000 ;
    LAYER TopMetal2 ;
      RECT 0.000 0.000 80.000 132.500 ;
    LAYER Via1 ;
      RECT 0.000 0.000 80.000 180.000 ;
    LAYER Via2 ;
      RECT 0.000 0.000 80.000 180.000 ;
  END
END IOPadInOut4mA

MACRO IOPadInOut8mA
  CLASS PAD INOUT ;
  ORIGIN 0.000 0.000 ;
  FOREIGN IOPadInOut8mA 0.000 0.000 ;
  SIZE 80.000 BY 180.000 ;
  SYMMETRY X Y R90 ;
  SITE IOLibSite ;
  PIN c2p
    DIRECTION INPUT ;
    USE SIGNAL ;
    PORT
      LAYER Metal2 ;
        RECT 18.330 178.090 18.620 180.000 ;
      LAYER Metal3 ;
        RECT 18.225 179.710 18.725 180.000 ;
    END
  END c2p
  PIN c2p_en
    DIRECTION INPUT ;
    USE SIGNAL ;
    PORT
      LAYER Metal2 ;
        RECT 21.380 174.045 21.670 180.000 ;
      LAYER Metal3 ;
        RECT 21.275 179.710 21.775 180.000 ;
    END
  END c2p_en
  PIN iovdd
    DIRECTION INOUT ;
    USE POWER ;
    PORT
      LAYER Metal3 ;
        RECT 0.000 93.500 80.000 119.000 ;
    END
    PORT
      LAYER Metal3 ;
        RECT 0.000 66.000 80.000 91.500 ;
    END
    PORT
      LAYER Metal4 ;
        RECT 0.000 93.500 80.000 119.000 ;
    END
    PORT
      LAYER Metal4 ;
        RECT 0.000 66.000 80.000 91.500 ;
    END
    PORT
      LAYER Metal5 ;
        RECT 0.000 93.500 80.000 119.000 ;
    END
    PORT
      LAYER Metal5 ;
        RECT 0.000 66.000 80.000 91.500 ;
    END
    PORT
      LAYER TopMetal1 ;
        RECT 0.000 93.500 80.000 119.000 ;
    END
    PORT
      LAYER TopMetal1 ;
        RECT 0.000 66.000 80.000 91.500 ;
    END
    PORT
      LAYER TopMetal2 ;
        RECT 0.000 95.000 80.000 117.500 ;
    END
    PORT
      LAYER TopMetal2 ;
        RECT 0.000 67.500 80.000 90.000 ;
    END
  END iovdd
  PIN iovss
    DIRECTION INOUT ;
    USE GROUND ;
    PORT
      LAYER Metal3 ;
        RECT 0.000 7.000 80.000 32.500 ;
    END
    PORT
      LAYER Metal3 ;
        RECT 0.000 126.000 80.000 134.000 ;
    END
    PORT
      LAYER Metal3 ;
        RECT 0.000 34.500 80.000 60.000 ;
    END
    PORT
      LAYER Metal4 ;
        RECT 0.000 7.000 80.000 32.500 ;
    END
    PORT
      LAYER Metal4 ;
        RECT 0.000 126.000 80.000 134.000 ;
    END
    PORT
      LAYER Metal4 ;
        RECT 0.000 34.500 80.000 60.000 ;
    END
    PORT
      LAYER Metal5 ;
        RECT 0.000 7.000 80.000 32.500 ;
    END
    PORT
      LAYER Metal5 ;
        RECT 0.000 126.000 80.000 134.000 ;
    END
    PORT
      LAYER Metal5 ;
        RECT 0.000 34.500 80.000 60.000 ;
    END
    PORT
      LAYER TopMetal1 ;
        RECT 0.000 7.000 80.000 32.500 ;
    END
    PORT
      LAYER TopMetal1 ;
        RECT 0.000 126.000 80.000 134.000 ;
    END
    PORT
      LAYER TopMetal1 ;
        RECT 0.000 34.500 80.000 60.000 ;
    END
    PORT
      LAYER TopMetal2 ;
        RECT 0.000 36.000 80.000 58.500 ;
    END
    PORT
      LAYER TopMetal2 ;
        RECT 0.000 8.500 80.000 31.000 ;
    END
    PORT
      LAYER TopMetal2 ;
        RECT 0.000 127.500 80.000 132.500 ;
    END
  END iovss
  PIN p2c
    DIRECTION OUTPUT ;
    USE SIGNAL ;
    PORT
      LAYER Metal2 ;
        RECT 59.830 157.810 60.120 180.000 ;
      LAYER Metal3 ;
        RECT 59.725 179.710 60.225 180.000 ;
    END
  END p2c
  PIN pad
    DIRECTION INOUT ;
    USE SIGNAL ;
    PORT
      LAYER Metal2 ;
        RECT 5.000 0.000 75.000 3.000 ;
      LAYER Metal3 ;
        RECT 5.000 0.000 75.000 3.000 ;
      LAYER Metal4 ;
        RECT 5.000 0.000 75.000 3.000 ;
      LAYER Metal5 ;
        RECT 5.000 0.000 75.000 3.000 ;
      LAYER TopMetal1 ;
        RECT 5.000 0.000 75.000 3.000 ;
      LAYER TopMetal2 ;
        RECT 5.000 0.000 75.000 3.000 ;
    END
  END pad
  PIN vdd
    DIRECTION INOUT ;
    USE POWER ;
    PORT
      LAYER Metal3 ;
        RECT 0.000 160.000 80.000 178.000 ;
    END
    PORT
      LAYER Metal4 ;
        RECT 0.000 140.000 80.000 155.800 ;
    END
    PORT
      LAYER Metal5 ;
        RECT 0.000 140.000 80.000 158.000 ;
    END
    PORT
      LAYER TopMetal1 ;
        RECT 0.000 140.000 80.000 158.000 ;
    END
  END vdd
  PIN vss
    DIRECTION INOUT ;
    USE GROUND ;
    PORT
      LAYER Metal3 ;
        RECT 0.000 140.000 80.000 158.000 ;
    END
    PORT
      LAYER Metal4 ;
        RECT 0.000 162.200 80.000 178.000 ;
    END
    PORT
      LAYER Metal5 ;
        RECT 0.000 160.000 80.000 178.000 ;
    END
    PORT
      LAYER TopMetal1 ;
        RECT 0.000 160.000 80.000 178.000 ;
    END
  END vss
  OBS
    LAYER Metal1 ;
      RECT 0.000 0.000 80.000 180.000 ;
    LAYER Metal2 ;
      RECT 0.000 0.000 80.000 180.000 ;
    LAYER Metal3 ;
      RECT 0.000 0.000 80.000 178.000 ;
    LAYER Metal4 ;
      RECT 0.000 0.000 80.000 178.000 ;
    LAYER Metal5 ;
      RECT 0.000 0.000 80.000 178.000 ;
    LAYER TopMetal1 ;
      RECT 0.000 0.000 80.000 178.000 ;
    LAYER TopMetal2 ;
      RECT 0.000 0.000 80.000 132.500 ;
    LAYER Via1 ;
      RECT 0.000 0.000 80.000 180.000 ;
    LAYER Via2 ;
      RECT 0.000 0.000 80.000 180.000 ;
  END
END IOPadInOut8mA

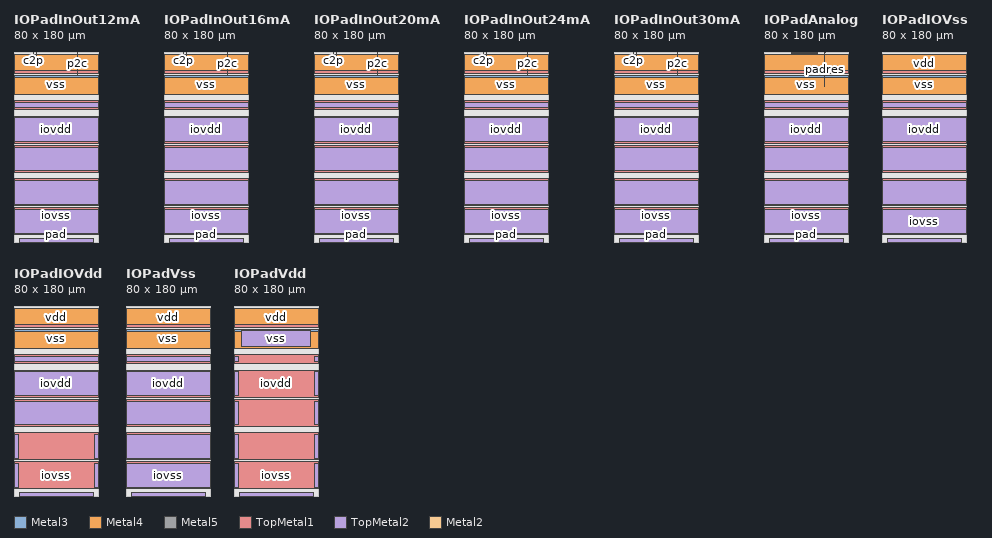
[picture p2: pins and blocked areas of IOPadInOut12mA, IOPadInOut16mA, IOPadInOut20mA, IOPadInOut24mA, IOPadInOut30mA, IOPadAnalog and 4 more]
MACRO IOPadInOut12mA
  CLASS PAD INOUT ;
  ORIGIN 0.000 0.000 ;
  FOREIGN IOPadInOut12mA 0.000 0.000 ;
  SIZE 80.000 BY 180.000 ;
  SYMMETRY X Y R90 ;
  SITE IOLibSite ;
  PIN c2p
    DIRECTION INPUT ;
    USE SIGNAL ;
    PORT
      LAYER Metal2 ;
        RECT 18.330 178.090 18.620 180.000 ;
      LAYER Metal3 ;
        RECT 18.225 179.710 18.725 180.000 ;
    END
  END c2p
  PIN c2p_en
    DIRECTION INPUT ;
    USE SIGNAL ;
    PORT
      LAYER Metal2 ;
        RECT 21.380 174.045 21.670 180.000 ;
      LAYER Metal3 ;
        RECT 21.275 179.710 21.775 180.000 ;
    END
  END c2p_en
  PIN iovdd
    DIRECTION INOUT ;
    USE POWER ;
    PORT
      LAYER Metal3 ;
        RECT 0.000 93.500 80.000 119.000 ;
    END
    PORT
      LAYER Metal3 ;
        RECT 0.000 66.000 80.000 91.500 ;
    END
    PORT
      LAYER Metal4 ;
        RECT 0.000 93.500 80.000 119.000 ;
    END
    PORT
      LAYER Metal4 ;
        RECT 0.000 66.000 80.000 91.500 ;
    END
    PORT
      LAYER Metal5 ;
        RECT 0.000 93.500 80.000 119.000 ;
    END
    PORT
      LAYER Metal5 ;
        RECT 0.000 66.000 80.000 91.500 ;
    END
    PORT
      LAYER TopMetal1 ;
        RECT 0.000 93.500 80.000 119.000 ;
    END
    PORT
      LAYER TopMetal1 ;
        RECT 0.000 66.000 80.000 91.500 ;
    END
    PORT
      LAYER TopMetal2 ;
        RECT 0.000 95.000 80.000 117.500 ;
    END
    PORT
      LAYER TopMetal2 ;
        RECT 0.000 67.500 80.000 90.000 ;
    END
  END iovdd
  PIN iovss
    DIRECTION INOUT ;
    USE GROUND ;
    PORT
      LAYER Metal3 ;
        RECT 0.000 7.000 80.000 32.500 ;
    END
    PORT
      LAYER Metal3 ;
        RECT 0.000 126.000 80.000 134.000 ;
    END
    PORT
      LAYER Metal3 ;
        RECT 0.000 34.500 80.000 60.000 ;
    END
    PORT
      LAYER Metal4 ;
        RECT 0.000 7.000 80.000 32.500 ;
    END
    PORT
      LAYER Metal4 ;
        RECT 0.000 126.000 80.000 134.000 ;
    END
    PORT
      LAYER Metal4 ;
        RECT 0.000 34.500 80.000 60.000 ;
    END
    PORT
      LAYER Metal5 ;
        RECT 0.000 7.000 80.000 32.500 ;
    END
    PORT
      LAYER Metal5 ;
        RECT 0.000 126.000 80.000 134.000 ;
    END
    PORT
      LAYER Metal5 ;
        RECT 0.000 34.500 80.000 60.000 ;
    END
    PORT
      LAYER TopMetal1 ;
        RECT 0.000 7.000 80.000 32.500 ;
    END
    PORT
      LAYER TopMetal1 ;
        RECT 0.000 126.000 80.000 134.000 ;
    END
    PORT
      LAYER TopMetal1 ;
        RECT 0.000 34.500 80.000 60.000 ;
    END
    PORT
      LAYER TopMetal2 ;
        RECT 0.000 36.000 80.000 58.500 ;
    END
    PORT
      LAYER TopMetal2 ;
        RECT 0.000 8.500 80.000 31.000 ;
    END
    PORT
      LAYER TopMetal2 ;
        RECT 0.000 127.500 80.000 132.500 ;
    END
  END iovss
  PIN p2c
    DIRECTION OUTPUT ;
    USE SIGNAL ;
    PORT
      LAYER Metal2 ;
        RECT 59.830 157.810 60.120 180.000 ;
      LAYER Metal3 ;
        RECT 59.725 179.710 60.225 180.000 ;
    END
  END p2c
  PIN pad
    DIRECTION INOUT ;
    USE SIGNAL ;
    PORT
      LAYER Metal2 ;
        RECT 5.000 0.000 75.000 3.000 ;
      LAYER Metal3 ;
        RECT 5.000 0.000 75.000 3.000 ;
      LAYER Metal4 ;
        RECT 5.000 0.000 75.000 3.000 ;
      LAYER Metal5 ;
        RECT 5.000 0.000 75.000 3.000 ;
      LAYER TopMetal1 ;
        RECT 5.000 0.000 75.000 3.000 ;
      LAYER TopMetal2 ;
        RECT 5.000 0.000 75.000 3.000 ;
    END
  END pad
  PIN vdd
    DIRECTION INOUT ;
    USE POWER ;
    PORT
      LAYER Metal3 ;
        RECT 0.000 160.000 80.000 178.000 ;
    END
    PORT
      LAYER Metal4 ;
        RECT 0.000 140.000 80.000 155.800 ;
    END
    PORT
      LAYER Metal5 ;
        RECT 0.000 140.000 80.000 158.000 ;
    END
    PORT
      LAYER TopMetal1 ;
        RECT 0.000 140.000 80.000 158.000 ;
    END
  END vdd
  PIN vss
    DIRECTION INOUT ;
    USE GROUND ;
    PORT
      LAYER Metal3 ;
        RECT 0.000 140.000 80.000 158.000 ;
    END
    PORT
      LAYER Metal4 ;
        RECT 0.000 162.200 80.000 178.000 ;
    END
    PORT
      LAYER Metal5 ;
        RECT 0.000 160.000 80.000 178.000 ;
    END
    PORT
      LAYER TopMetal1 ;
        RECT 0.000 160.000 80.000 178.000 ;
    END
  END vss
  OBS
    LAYER Metal1 ;
      RECT 0.000 0.000 80.000 180.000 ;
    LAYER Metal2 ;
      RECT 0.000 0.000 80.000 180.000 ;
    LAYER Metal3 ;
      RECT 0.000 0.000 80.000 178.000 ;
    LAYER Metal4 ;
      RECT 0.000 0.000 80.000 178.000 ;
    LAYER Metal5 ;
      RECT 0.000 0.000 80.000 178.000 ;
    LAYER TopMetal1 ;
      RECT 0.000 0.000 80.000 178.000 ;
    LAYER TopMetal2 ;
      RECT 0.000 0.000 80.000 132.500 ;
    LAYER Via1 ;
      RECT 0.000 0.000 80.000 180.000 ;
    LAYER Via2 ;
      RECT 0.000 0.000 80.000 180.000 ;
  END
END IOPadInOut12mA

MACRO IOPadInOut16mA
  CLASS PAD INOUT ;
  ORIGIN 0.000 0.000 ;
  FOREIGN IOPadInOut16mA 0.000 0.000 ;
  SIZE 80.000 BY 180.000 ;
  SYMMETRY X Y R90 ;
  SITE IOLibSite ;
  PIN c2p
    DIRECTION INPUT ;
    USE SIGNAL ;
    PORT
      LAYER Metal2 ;
        RECT 18.330 178.090 18.620 180.000 ;
      LAYER Metal3 ;
        RECT 18.225 179.710 18.725 180.000 ;
    END
  END c2p
  PIN c2p_en
    DIRECTION INPUT ;
    USE SIGNAL ;
    PORT
      LAYER Metal2 ;
        RECT 21.380 174.045 21.670 180.000 ;
      LAYER Metal3 ;
        RECT 21.275 179.710 21.775 180.000 ;
    END
  END c2p_en
  PIN iovdd
    DIRECTION INOUT ;
    USE POWER ;
    PORT
      LAYER Metal3 ;
        RECT 0.000 93.500 80.000 119.000 ;
    END
    PORT
      LAYER Metal3 ;
        RECT 0.000 66.000 80.000 91.500 ;
    END
    PORT
      LAYER Metal4 ;
        RECT 0.000 93.500 80.000 119.000 ;
    END
    PORT
      LAYER Metal4 ;
        RECT 0.000 66.000 80.000 91.500 ;
    END
    PORT
      LAYER Metal5 ;
        RECT 0.000 93.500 80.000 119.000 ;
    END
    PORT
      LAYER Metal5 ;
        RECT 0.000 66.000 80.000 91.500 ;
    END
    PORT
      LAYER TopMetal1 ;
        RECT 0.000 93.500 80.000 119.000 ;
    END
    PORT
      LAYER TopMetal1 ;
        RECT 0.000 66.000 80.000 91.500 ;
    END
    PORT
      LAYER TopMetal2 ;
        RECT 0.000 95.000 80.000 117.500 ;
    END
    PORT
      LAYER TopMetal2 ;
        RECT 0.000 67.500 80.000 90.000 ;
    END
  END iovdd
  PIN iovss
    DIRECTION INOUT ;
    USE GROUND ;
    PORT
      LAYER Metal3 ;
        RECT 0.000 7.000 80.000 32.500 ;
    END
    PORT
      LAYER Metal3 ;
        RECT 0.000 126.000 80.000 134.000 ;
    END
    PORT
      LAYER Metal3 ;
        RECT 0.000 34.500 80.000 60.000 ;
    END
    PORT
      LAYER Metal4 ;
        RECT 0.000 7.000 80.000 32.500 ;
    END
    PORT
      LAYER Metal4 ;
        RECT 0.000 126.000 80.000 134.000 ;
    END
    PORT
      LAYER Metal4 ;
        RECT 0.000 34.500 80.000 60.000 ;
    END
    PORT
      LAYER Metal5 ;
        RECT 0.000 7.000 80.000 32.500 ;
    END
    PORT
      LAYER Metal5 ;
        RECT 0.000 126.000 80.000 134.000 ;
    END
    PORT
      LAYER Metal5 ;
        RECT 0.000 34.500 80.000 60.000 ;
    END
    PORT
      LAYER TopMetal1 ;
        RECT 0.000 7.000 80.000 32.500 ;
    END
    PORT
      LAYER TopMetal1 ;
        RECT 0.000 126.000 80.000 134.000 ;
    END
    PORT
      LAYER TopMetal1 ;
        RECT 0.000 34.500 80.000 60.000 ;
    END
    PORT
      LAYER TopMetal2 ;
        RECT 0.000 36.000 80.000 58.500 ;
    END
    PORT
      LAYER TopMetal2 ;
        RECT 0.000 8.500 80.000 31.000 ;
    END
    PORT
      LAYER TopMetal2 ;
        RECT 0.000 127.500 80.000 132.500 ;
    END
  END iovss
  PIN p2c
    DIRECTION OUTPUT ;
    USE SIGNAL ;
    PORT
      LAYER Metal2 ;
        RECT 59.830 157.810 60.120 180.000 ;
      LAYER Metal3 ;
        RECT 59.725 179.710 60.225 180.000 ;
    END
  END p2c
  PIN pad
    DIRECTION INOUT ;
    USE SIGNAL ;
    PORT
      LAYER Metal2 ;
        RECT 5.000 0.000 75.000 3.000 ;
      LAYER Metal3 ;
        RECT 5.000 0.000 75.000 3.000 ;
      LAYER Metal4 ;
        RECT 5.000 0.000 75.000 3.000 ;
      LAYER Metal5 ;
        RECT 5.000 0.000 75.000 3.000 ;
      LAYER TopMetal1 ;
        RECT 5.000 0.000 75.000 3.000 ;
      LAYER TopMetal2 ;
        RECT 5.000 0.000 75.000 3.000 ;
    END
  END pad
  PIN vdd
    DIRECTION INOUT ;
    USE POWER ;
    PORT
      LAYER Metal3 ;
        RECT 0.000 160.000 80.000 178.000 ;
    END
    PORT
      LAYER Metal4 ;
        RECT 0.000 140.000 80.000 155.800 ;
    END
    PORT
      LAYER Metal5 ;
        RECT 0.000 140.000 80.000 158.000 ;
    END
    PORT
      LAYER TopMetal1 ;
        RECT 0.000 140.000 80.000 158.000 ;
    END
  END vdd
  PIN vss
    DIRECTION INOUT ;
    USE GROUND ;
    PORT
      LAYER Metal3 ;
        RECT 0.000 140.000 80.000 158.000 ;
    END
    PORT
      LAYER Metal4 ;
        RECT 0.000 162.200 80.000 178.000 ;
    END
    PORT
      LAYER Metal5 ;
        RECT 0.000 160.000 80.000 178.000 ;
    END
    PORT
      LAYER TopMetal1 ;
        RECT 0.000 160.000 80.000 178.000 ;
    END
  END vss
  OBS
    LAYER Metal1 ;
      RECT 0.000 0.000 80.000 180.000 ;
    LAYER Metal2 ;
      RECT 0.000 0.000 80.000 180.000 ;
    LAYER Metal3 ;
      RECT 0.000 0.000 80.000 178.000 ;
    LAYER Metal4 ;
      RECT 0.000 0.000 80.000 178.000 ;
    LAYER Metal5 ;
      RECT 0.000 0.000 80.000 178.000 ;
    LAYER TopMetal1 ;
      RECT 0.000 0.000 80.000 178.000 ;
    LAYER TopMetal2 ;
      RECT 0.000 0.000 80.000 132.500 ;
    LAYER Via1 ;
      RECT 0.000 0.000 80.000 180.000 ;
    LAYER Via2 ;
      RECT 0.000 0.000 80.000 180.000 ;
  END
END IOPadInOut16mA

MACRO IOPadInOut20mA
  CLASS PAD INOUT ;
  ORIGIN 0.000 0.000 ;
  FOREIGN IOPadInOut20mA 0.000 0.000 ;
  SIZE 80.000 BY 180.000 ;
  SYMMETRY X Y R90 ;
  SITE IOLibSite ;
  PIN c2p
    DIRECTION INPUT ;
    USE SIGNAL ;
    PORT
      LAYER Metal2 ;
        RECT 18.330 178.090 18.620 180.000 ;
      LAYER Metal3 ;
        RECT 18.225 179.710 18.725 180.000 ;
    END
  END c2p
  PIN c2p_en
    DIRECTION INPUT ;
    USE SIGNAL ;
    PORT
      LAYER Metal2 ;
        RECT 21.380 174.045 21.670 180.000 ;
      LAYER Metal3 ;
        RECT 21.275 179.710 21.775 180.000 ;
    END
  END c2p_en
  PIN iovdd
    DIRECTION INOUT ;
    USE POWER ;
    PORT
      LAYER Metal3 ;
        RECT 0.000 93.500 80.000 119.000 ;
    END
    PORT
      LAYER Metal3 ;
        RECT 0.000 66.000 80.000 91.500 ;
    END
    PORT
      LAYER Metal4 ;
        RECT 0.000 93.500 80.000 119.000 ;
    END
    PORT
      LAYER Metal4 ;
        RECT 0.000 66.000 80.000 91.500 ;
    END
    PORT
      LAYER Metal5 ;
        RECT 0.000 93.500 80.000 119.000 ;
    END
    PORT
      LAYER Metal5 ;
        RECT 0.000 66.000 80.000 91.500 ;
    END
    PORT
      LAYER TopMetal1 ;
        RECT 0.000 93.500 80.000 119.000 ;
    END
    PORT
      LAYER TopMetal1 ;
        RECT 0.000 66.000 80.000 91.500 ;
    END
    PORT
      LAYER TopMetal2 ;
        RECT 0.000 95.000 80.000 117.500 ;
    END
    PORT
      LAYER TopMetal2 ;
        RECT 0.000 67.500 80.000 90.000 ;
    END
  END iovdd
  PIN iovss
    DIRECTION INOUT ;
    USE GROUND ;
    PORT
      LAYER Metal3 ;
        RECT 0.000 7.000 80.000 32.500 ;
    END
    PORT
      LAYER Metal3 ;
        RECT 0.000 126.000 80.000 134.000 ;
    END
    PORT
      LAYER Metal3 ;
        RECT 0.000 34.500 80.000 60.000 ;
    END
    PORT
      LAYER Metal4 ;
        RECT 0.000 7.000 80.000 32.500 ;
    END
    PORT
      LAYER Metal4 ;
        RECT 0.000 126.000 80.000 134.000 ;
    END
    PORT
      LAYER Metal4 ;
        RECT 0.000 34.500 80.000 60.000 ;
    END
    PORT
      LAYER Metal5 ;
        RECT 0.000 7.000 80.000 32.500 ;
    END
    PORT
      LAYER Metal5 ;
        RECT 0.000 126.000 80.000 134.000 ;
    END
    PORT
      LAYER Metal5 ;
        RECT 0.000 34.500 80.000 60.000 ;
    END
    PORT
      LAYER TopMetal1 ;
        RECT 0.000 7.000 80.000 32.500 ;
    END
    PORT
      LAYER TopMetal1 ;
        RECT 0.000 126.000 80.000 134.000 ;
    END
    PORT
      LAYER TopMetal1 ;
        RECT 0.000 34.500 80.000 60.000 ;
    END
    PORT
      LAYER TopMetal2 ;
        RECT 0.000 36.000 80.000 58.500 ;
    END
    PORT
      LAYER TopMetal2 ;
        RECT 0.000 8.500 80.000 31.000 ;
    END
    PORT
      LAYER TopMetal2 ;
        RECT 0.000 127.500 80.000 132.500 ;
    END
  END iovss
  PIN p2c
    DIRECTION OUTPUT ;
    USE SIGNAL ;
    PORT
      LAYER Metal2 ;
        RECT 59.830 157.810 60.120 180.000 ;
      LAYER Metal3 ;
        RECT 59.725 179.710 60.225 180.000 ;
    END
  END p2c
  PIN pad
    DIRECTION INOUT ;
    USE SIGNAL ;
    PORT
      LAYER Metal2 ;
        RECT 5.000 0.000 75.000 3.000 ;
      LAYER Metal3 ;
        RECT 5.000 0.000 75.000 3.000 ;
      LAYER Metal4 ;
        RECT 5.000 0.000 75.000 3.000 ;
      LAYER Metal5 ;
        RECT 5.000 0.000 75.000 3.000 ;
      LAYER TopMetal1 ;
        RECT 5.000 0.000 75.000 3.000 ;
      LAYER TopMetal2 ;
        RECT 5.000 0.000 75.000 3.000 ;
    END
  END pad
  PIN vdd
    DIRECTION INOUT ;
    USE POWER ;
    PORT
      LAYER Metal3 ;
        RECT 0.000 160.000 80.000 178.000 ;
    END
    PORT
      LAYER Metal4 ;
        RECT 0.000 140.000 80.000 155.800 ;
    END
    PORT
      LAYER Metal5 ;
        RECT 0.000 140.000 80.000 158.000 ;
    END
    PORT
      LAYER TopMetal1 ;
        RECT 0.000 140.000 80.000 158.000 ;
    END
  END vdd
  PIN vss
    DIRECTION INOUT ;
    USE GROUND ;
    PORT
      LAYER Metal3 ;
        RECT 0.000 140.000 80.000 158.000 ;
    END
    PORT
      LAYER Metal4 ;
        RECT 0.000 162.200 80.000 178.000 ;
    END
    PORT
      LAYER Metal5 ;
        RECT 0.000 160.000 80.000 178.000 ;
    END
    PORT
      LAYER TopMetal1 ;
        RECT 0.000 160.000 80.000 178.000 ;
    END
  END vss
  OBS
    LAYER Metal1 ;
      RECT 0.000 0.000 80.000 180.000 ;
    LAYER Metal2 ;
      RECT 0.000 0.000 80.000 180.000 ;
    LAYER Metal3 ;
      RECT 0.000 0.000 80.000 178.000 ;
    LAYER Metal4 ;
      RECT 0.000 0.000 80.000 178.000 ;
    LAYER Metal5 ;
      RECT 0.000 0.000 80.000 178.000 ;
    LAYER TopMetal1 ;
      RECT 0.000 0.000 80.000 178.000 ;
    LAYER TopMetal2 ;
      RECT 0.000 0.000 80.000 132.500 ;
    LAYER Via1 ;
      RECT 0.000 0.000 80.000 180.000 ;
    LAYER Via2 ;
      RECT 0.000 0.000 80.000 180.000 ;
  END
END IOPadInOut20mA

MACRO IOPadInOut24mA
  CLASS PAD INOUT ;
  ORIGIN 0.000 0.000 ;
  FOREIGN IOPadInOut24mA 0.000 0.000 ;
  SIZE 80.000 BY 180.000 ;
  SYMMETRY X Y R90 ;
  SITE IOLibSite ;
  PIN c2p
    DIRECTION INPUT ;
    USE SIGNAL ;
    PORT
      LAYER Metal2 ;
        RECT 18.330 178.090 18.620 180.000 ;
      LAYER Metal3 ;
        RECT 18.225 179.710 18.725 180.000 ;
    END
  END c2p
  PIN c2p_en
    DIRECTION INPUT ;
    USE SIGNAL ;
    PORT
      LAYER Metal2 ;
        RECT 21.380 174.045 21.670 180.000 ;
      LAYER Metal3 ;
        RECT 21.275 179.710 21.775 180.000 ;
    END
  END c2p_en
  PIN iovdd
    DIRECTION INOUT ;
    USE POWER ;
    PORT
      LAYER Metal3 ;
        RECT 0.000 93.500 80.000 119.000 ;
    END
    PORT
      LAYER Metal3 ;
        RECT 0.000 66.000 80.000 91.500 ;
    END
    PORT
      LAYER Metal4 ;
        RECT 0.000 93.500 80.000 119.000 ;
    END
    PORT
      LAYER Metal4 ;
        RECT 0.000 66.000 80.000 91.500 ;
    END
    PORT
      LAYER Metal5 ;
        RECT 0.000 93.500 80.000 119.000 ;
    END
    PORT
      LAYER Metal5 ;
        RECT 0.000 66.000 80.000 91.500 ;
    END
    PORT
      LAYER TopMetal1 ;
        RECT 0.000 93.500 80.000 119.000 ;
    END
    PORT
      LAYER TopMetal1 ;
        RECT 0.000 66.000 80.000 91.500 ;
    END
    PORT
      LAYER TopMetal2 ;
        RECT 0.000 95.000 80.000 117.500 ;
    END
    PORT
      LAYER TopMetal2 ;
        RECT 0.000 67.500 80.000 90.000 ;
    END
  END iovdd
  PIN iovss
    DIRECTION INOUT ;
    USE GROUND ;
    PORT
      LAYER Metal3 ;
        RECT 0.000 7.000 80.000 32.500 ;
    END
    PORT
      LAYER Metal3 ;
        RECT 0.000 126.000 80.000 134.000 ;
    END
    PORT
      LAYER Metal3 ;
        RECT 0.000 34.500 80.000 60.000 ;
    END
    PORT
      LAYER Metal4 ;
        RECT 0.000 7.000 80.000 32.500 ;
    END
    PORT
      LAYER Metal4 ;
        RECT 0.000 126.000 80.000 134.000 ;
    END
    PORT
      LAYER Metal4 ;
        RECT 0.000 34.500 80.000 60.000 ;
    END
    PORT
      LAYER Metal5 ;
        RECT 0.000 7.000 80.000 32.500 ;
    END
    PORT
      LAYER Metal5 ;
        RECT 0.000 126.000 80.000 134.000 ;
    END
    PORT
      LAYER Metal5 ;
        RECT 0.000 34.500 80.000 60.000 ;
    END
    PORT
      LAYER TopMetal1 ;
        RECT 0.000 7.000 80.000 32.500 ;
    END
    PORT
      LAYER TopMetal1 ;
        RECT 0.000 126.000 80.000 134.000 ;
    END
    PORT
      LAYER TopMetal1 ;
        RECT 0.000 34.500 80.000 60.000 ;
    END
    PORT
      LAYER TopMetal2 ;
        RECT 0.000 36.000 80.000 58.500 ;
    END
    PORT
      LAYER TopMetal2 ;
        RECT 0.000 8.500 80.000 31.000 ;
    END
    PORT
      LAYER TopMetal2 ;
        RECT 0.000 127.500 80.000 132.500 ;
    END
  END iovss
  PIN p2c
    DIRECTION OUTPUT ;
    USE SIGNAL ;
    PORT
      LAYER Metal2 ;
        RECT 59.830 157.810 60.120 180.000 ;
      LAYER Metal3 ;
        RECT 59.725 179.710 60.225 180.000 ;
    END
  END p2c
  PIN pad
    DIRECTION INOUT ;
    USE SIGNAL ;
    PORT
      LAYER Metal2 ;
        RECT 5.000 0.000 75.000 3.000 ;
      LAYER Metal3 ;
        RECT 5.000 0.000 75.000 3.000 ;
      LAYER Metal4 ;
        RECT 5.000 0.000 75.000 3.000 ;
      LAYER Metal5 ;
        RECT 5.000 0.000 75.000 3.000 ;
      LAYER TopMetal1 ;
        RECT 5.000 0.000 75.000 3.000 ;
      LAYER TopMetal2 ;
        RECT 5.000 0.000 75.000 3.000 ;
    END
  END pad
  PIN vdd
    DIRECTION INOUT ;
    USE POWER ;
    PORT
      LAYER Metal3 ;
        RECT 0.000 160.000 80.000 178.000 ;
    END
    PORT
      LAYER Metal4 ;
        RECT 0.000 140.000 80.000 155.800 ;
    END
    PORT
      LAYER Metal5 ;
        RECT 0.000 140.000 80.000 158.000 ;
    END
    PORT
      LAYER TopMetal1 ;
        RECT 0.000 140.000 80.000 158.000 ;
    END
  END vdd
  PIN vss
    DIRECTION INOUT ;
    USE GROUND ;
    PORT
      LAYER Metal3 ;
        RECT 0.000 140.000 80.000 158.000 ;
    END
    PORT
      LAYER Metal4 ;
        RECT 0.000 162.200 80.000 178.000 ;
    END
    PORT
      LAYER Metal5 ;
        RECT 0.000 160.000 80.000 178.000 ;
    END
    PORT
      LAYER TopMetal1 ;
        RECT 0.000 160.000 80.000 178.000 ;
    END
  END vss
  OBS
    LAYER Metal1 ;
      RECT 0.000 0.000 80.000 180.000 ;
    LAYER Metal2 ;
      RECT 0.000 0.000 80.000 180.000 ;
    LAYER Metal3 ;
      RECT 0.000 0.000 80.000 178.000 ;
    LAYER Metal4 ;
      RECT 0.000 0.000 80.000 178.000 ;
    LAYER Metal5 ;
      RECT 0.000 0.000 80.000 178.000 ;
    LAYER TopMetal1 ;
      RECT 0.000 0.000 80.000 178.000 ;
    LAYER TopMetal2 ;
      RECT 0.000 0.000 80.000 132.500 ;
    LAYER Via1 ;
      RECT 0.000 0.000 80.000 180.000 ;
    LAYER Via2 ;
      RECT 0.000 0.000 80.000 180.000 ;
  END
END IOPadInOut24mA

MACRO IOPadInOut30mA
  CLASS PAD INOUT ;
  ORIGIN 0.000 0.000 ;
  FOREIGN IOPadInOut30mA 0.000 0.000 ;
  SIZE 80.000 BY 180.000 ;
  SYMMETRY X Y R90 ;
  SITE IOLibSite ;
  PIN c2p
    DIRECTION INPUT ;
    USE SIGNAL ;
    PORT
      LAYER Metal2 ;
        RECT 18.330 178.090 18.620 180.000 ;
      LAYER Metal3 ;
        RECT 18.225 179.710 18.725 180.000 ;
    END
  END c2p
  PIN c2p_en
    DIRECTION INPUT ;
    USE SIGNAL ;
    PORT
      LAYER Metal2 ;
        RECT 21.380 174.045 21.670 180.000 ;
      LAYER Metal3 ;
        RECT 21.275 179.710 21.775 180.000 ;
    END
  END c2p_en
  PIN iovdd
    DIRECTION INOUT ;
    USE POWER ;
    PORT
      LAYER Metal3 ;
        RECT 0.000 93.500 80.000 119.000 ;
    END
    PORT
      LAYER Metal3 ;
        RECT 0.000 66.000 80.000 91.500 ;
    END
    PORT
      LAYER Metal4 ;
        RECT 0.000 93.500 80.000 119.000 ;
    END
    PORT
      LAYER Metal4 ;
        RECT 0.000 66.000 80.000 91.500 ;
    END
    PORT
      LAYER Metal5 ;
        RECT 0.000 93.500 80.000 119.000 ;
    END
    PORT
      LAYER Metal5 ;
        RECT 0.000 66.000 80.000 91.500 ;
    END
    PORT
      LAYER TopMetal1 ;
        RECT 0.000 93.500 80.000 119.000 ;
    END
    PORT
      LAYER TopMetal1 ;
        RECT 0.000 66.000 80.000 91.500 ;
    END
    PORT
      LAYER TopMetal2 ;
        RECT 0.000 95.000 80.000 117.500 ;
    END
    PORT
      LAYER TopMetal2 ;
        RECT 0.000 67.500 80.000 90.000 ;
    END
  END iovdd
  PIN iovss
    DIRECTION INOUT ;
    USE GROUND ;
    PORT
      LAYER Metal3 ;
        RECT 0.000 7.000 80.000 32.500 ;
    END
    PORT
      LAYER Metal3 ;
        RECT 0.000 126.000 80.000 134.000 ;
    END
    PORT
      LAYER Metal3 ;
        RECT 0.000 34.500 80.000 60.000 ;
    END
    PORT
      LAYER Metal4 ;
        RECT 0.000 7.000 80.000 32.500 ;
    END
    PORT
      LAYER Metal4 ;
        RECT 0.000 126.000 80.000 134.000 ;
    END
    PORT
      LAYER Metal4 ;
        RECT 0.000 34.500 80.000 60.000 ;
    END
    PORT
      LAYER Metal5 ;
        RECT 0.000 7.000 80.000 32.500 ;
    END
    PORT
      LAYER Metal5 ;
        RECT 0.000 126.000 80.000 134.000 ;
    END
    PORT
      LAYER Metal5 ;
        RECT 0.000 34.500 80.000 60.000 ;
    END
    PORT
      LAYER TopMetal1 ;
        RECT 0.000 7.000 80.000 32.500 ;
    END
    PORT
      LAYER TopMetal1 ;
        RECT 0.000 126.000 80.000 134.000 ;
    END
    PORT
      LAYER TopMetal1 ;
        RECT 0.000 34.500 80.000 60.000 ;
    END
    PORT
      LAYER TopMetal2 ;
        RECT 0.000 36.000 80.000 58.500 ;
    END
    PORT
      LAYER TopMetal2 ;
        RECT 0.000 8.500 80.000 31.000 ;
    END
    PORT
      LAYER TopMetal2 ;
        RECT 0.000 127.500 80.000 132.500 ;
    END
  END iovss
  PIN p2c
    DIRECTION OUTPUT ;
    USE SIGNAL ;
    PORT
      LAYER Metal2 ;
        RECT 59.830 157.810 60.120 180.000 ;
      LAYER Metal3 ;
        RECT 59.725 179.710 60.225 180.000 ;
    END
  END p2c
  PIN pad
    DIRECTION INOUT ;
    USE SIGNAL ;
    PORT
      LAYER Metal2 ;
        RECT 5.000 0.000 75.000 3.000 ;
      LAYER Metal3 ;
        RECT 5.000 0.000 75.000 3.000 ;
      LAYER Metal4 ;
        RECT 5.000 0.000 75.000 3.000 ;
      LAYER Metal5 ;
        RECT 5.000 0.000 75.000 3.000 ;
      LAYER TopMetal1 ;
        RECT 5.000 0.000 75.000 3.000 ;
      LAYER TopMetal2 ;
        RECT 5.000 0.000 75.000 3.000 ;
    END
  END pad
  PIN vdd
    DIRECTION INOUT ;
    USE POWER ;
    PORT
      LAYER Metal3 ;
        RECT 0.000 160.000 80.000 178.000 ;
    END
    PORT
      LAYER Metal4 ;
        RECT 0.000 140.000 80.000 155.800 ;
    END
    PORT
      LAYER Metal5 ;
        RECT 0.000 140.000 80.000 158.000 ;
    END
    PORT
      LAYER TopMetal1 ;
        RECT 0.000 140.000 80.000 158.000 ;
    END
  END vdd
  PIN vss
    DIRECTION INOUT ;
    USE GROUND ;
    PORT
      LAYER Metal3 ;
        RECT 0.000 140.000 80.000 158.000 ;
    END
    PORT
      LAYER Metal4 ;
        RECT 0.000 162.200 80.000 178.000 ;
    END
    PORT
      LAYER Metal5 ;
        RECT 0.000 160.000 80.000 178.000 ;
    END
    PORT
      LAYER TopMetal1 ;
        RECT 0.000 160.000 80.000 178.000 ;
    END
  END vss
  OBS
    LAYER Metal1 ;
      RECT 0.000 0.000 80.000 180.000 ;
    LAYER Metal2 ;
      RECT 0.000 0.000 80.000 180.000 ;
    LAYER Metal3 ;
      RECT 0.000 0.000 80.000 178.000 ;
    LAYER Metal4 ;
      RECT 0.000 0.000 80.000 178.000 ;
    LAYER Metal5 ;
      RECT 0.000 0.000 80.000 178.000 ;
    LAYER TopMetal1 ;
      RECT 0.000 0.000 80.000 178.000 ;
    LAYER TopMetal2 ;
      RECT 0.000 0.000 80.000 132.500 ;
    LAYER Via1 ;
      RECT 0.000 0.000 80.000 180.000 ;
    LAYER Via2 ;
      RECT 0.000 0.000 80.000 180.000 ;
  END
END IOPadInOut30mA

MACRO IOPadAnalog
  CLASS PAD INOUT ;
  ORIGIN 0.000 0.000 ;
  FOREIGN IOPadAnalog 0.000 0.000 ;
  SIZE 80.000 BY 180.000 ;
  SYMMETRY X Y R90 ;
  SITE IOLibSite ;
  PIN iovdd
    DIRECTION INOUT ;
    USE POWER ;
    PORT
      LAYER Metal3 ;
        RECT 0.000 93.500 80.000 119.000 ;
    END
    PORT
      LAYER Metal3 ;
        RECT 0.000 66.000 80.000 91.500 ;
    END
    PORT
      LAYER Metal4 ;
        RECT 0.000 93.500 80.000 119.000 ;
    END
    PORT
      LAYER Metal4 ;
        RECT 0.000 66.000 80.000 91.500 ;
    END
    PORT
      LAYER Metal5 ;
        RECT 0.000 93.500 80.000 119.000 ;
    END
    PORT
      LAYER Metal5 ;
        RECT 0.000 66.000 80.000 91.500 ;
    END
    PORT
      LAYER TopMetal1 ;
        RECT 0.000 93.500 80.000 119.000 ;
    END
    PORT
      LAYER TopMetal1 ;
        RECT 0.000 66.000 80.000 91.500 ;
    END
    PORT
      LAYER TopMetal2 ;
        RECT 0.000 95.000 80.000 117.500 ;
    END
    PORT
      LAYER TopMetal2 ;
        RECT 0.000 67.500 80.000 90.000 ;
    END
  END iovdd
  PIN iovss
    DIRECTION INOUT ;
    USE GROUND ;
    PORT
      LAYER Metal3 ;
        RECT 0.000 7.000 80.000 32.500 ;
    END
    PORT
      LAYER Metal3 ;
        RECT 0.000 126.000 80.000 134.000 ;
    END
    PORT
      LAYER Metal3 ;
        RECT 0.000 34.500 80.000 60.000 ;
    END
    PORT
      LAYER Metal4 ;
        RECT 0.000 7.000 80.000 32.500 ;
    END
    PORT
      LAYER Metal4 ;
        RECT 0.000 126.000 80.000 134.000 ;
    END
    PORT
      LAYER Metal4 ;
        RECT 0.000 34.500 80.000 60.000 ;
    END
    PORT
      LAYER Metal5 ;
        RECT 0.000 7.000 80.000 32.500 ;
    END
    PORT
      LAYER Metal5 ;
        RECT 0.000 126.000 80.000 134.000 ;
    END
    PORT
      LAYER Metal5 ;
        RECT 0.000 34.500 80.000 60.000 ;
    END
    PORT
      LAYER TopMetal1 ;
        RECT 0.000 7.000 80.000 32.500 ;
    END
    PORT
      LAYER TopMetal1 ;
        RECT 0.000 126.000 80.000 134.000 ;
    END
    PORT
      LAYER TopMetal1 ;
        RECT 0.000 34.500 80.000 60.000 ;
    END
    PORT
      LAYER TopMetal2 ;
        RECT 0.000 36.000 80.000 58.500 ;
    END
    PORT
      LAYER TopMetal2 ;
        RECT 0.000 8.500 80.000 31.000 ;
    END
    PORT
      LAYER TopMetal2 ;
        RECT 0.000 127.500 80.000 132.500 ;
    END
  END iovss
  PIN pad
    DIRECTION INOUT ;
    USE SIGNAL ;
    PORT
      LAYER Metal2 ;
        RECT 26.105 179.000 50.875 180.000 ;
      LAYER Metal3 ;
        RECT 26.105 179.710 50.875 180.000 ;
    END
    PORT
      LAYER Metal2 ;
        RECT 5.000 0.000 75.000 3.000 ;
      LAYER Metal3 ;
        RECT 5.000 0.000 75.000 3.000 ;
      LAYER Metal4 ;
        RECT 5.000 0.000 75.000 3.000 ;
      LAYER Metal5 ;
        RECT 5.000 0.000 75.000 3.000 ;
      LAYER TopMetal1 ;
        RECT 5.000 0.000 75.000 3.000 ;
      LAYER TopMetal2 ;
        RECT 5.000 0.000 75.000 3.000 ;
    END
  END pad
  PIN padres
    DIRECTION INOUT ;
    USE SIGNAL ;
    PORT
      LAYER Metal2 ;
        RECT 57.460 147.180 57.750 180.000 ;
      LAYER Metal3 ;
        RECT 57.355 179.710 57.855 180.000 ;
    END
  END padres
  PIN vdd
    DIRECTION INOUT ;
    USE POWER ;
    PORT
      LAYER Metal3 ;
        RECT 0.000 160.000 80.000 178.000 ;
    END
    PORT
      LAYER Metal4 ;
        RECT 0.000 140.000 80.000 155.800 ;
    END
    PORT
      LAYER Metal5 ;
        RECT 0.000 140.000 80.000 158.000 ;
    END
    PORT
      LAYER TopMetal1 ;
        RECT 0.000 140.000 80.000 158.000 ;
    END
  END vdd
  PIN vss
    DIRECTION INOUT ;
    USE GROUND ;
    PORT
      LAYER Metal3 ;
        RECT 0.000 140.000 80.000 158.000 ;
    END
    PORT
      LAYER Metal4 ;
        RECT 0.000 162.200 80.000 178.000 ;
    END
    PORT
      LAYER Metal5 ;
        RECT 0.000 160.000 80.000 178.000 ;
    END
    PORT
      LAYER TopMetal1 ;
        RECT 0.000 160.000 80.000 178.000 ;
    END
  END vss
  OBS
    LAYER Metal1 ;
      RECT 0.000 0.000 80.000 180.000 ;
    LAYER Metal2 ;
      RECT 0.000 0.000 80.000 180.000 ;
    LAYER Metal3 ;
      RECT 0.000 0.000 80.000 178.000 ;
    LAYER Metal4 ;
      RECT 0.000 0.000 80.000 178.000 ;
    LAYER Metal5 ;
      RECT 0.000 0.000 80.000 178.000 ;
    LAYER TopMetal1 ;
      RECT 0.000 0.000 80.000 178.000 ;
    LAYER TopMetal2 ;
      RECT 0.000 0.000 80.000 132.500 ;
    LAYER Via1 ;
      RECT 0.000 0.000 80.000 180.000 ;
    LAYER Via2 ;
      RECT 0.000 0.000 80.000 180.000 ;
  END
END IOPadAnalog

MACRO IOPadIOVss
  CLASS PAD POWER ;
  ORIGIN 0.000 0.000 ;
  FOREIGN IOPadIOVss 0.000 0.000 ;
  SIZE 80.000 BY 180.000 ;
  SYMMETRY X Y R90 ;
  SITE IOLibSite ;
  PIN iovdd
    DIRECTION INOUT ;
    USE POWER ;
    PORT
      LAYER Metal3 ;
        RECT 0.000 93.500 80.000 119.000 ;
    END
    PORT
      LAYER Metal3 ;
        RECT 0.000 66.000 80.000 91.500 ;
    END
    PORT
      LAYER Metal4 ;
        RECT 0.000 93.500 80.000 119.000 ;
    END
    PORT
      LAYER Metal4 ;
        RECT 0.000 66.000 80.000 91.500 ;
    END
    PORT
      LAYER Metal5 ;
        RECT 0.000 93.500 80.000 119.000 ;
    END
    PORT
      LAYER Metal5 ;
        RECT 0.000 66.000 80.000 91.500 ;
    END
    PORT
      LAYER TopMetal1 ;
        RECT 0.000 93.500 80.000 119.000 ;
    END
    PORT
      LAYER TopMetal1 ;
        RECT 0.000 66.000 80.000 91.500 ;
    END
    PORT
      LAYER TopMetal2 ;
        RECT 0.000 95.000 80.000 117.500 ;
    END
    PORT
      LAYER TopMetal2 ;
        RECT 0.000 67.500 80.000 90.000 ;
    END
  END iovdd
  PIN iovss
    DIRECTION INOUT ;
    USE GROUND ;
    PORT
      LAYER Metal2 ;
        RECT 5.000 0.000 75.000 3.000 ;
      LAYER Metal3 ;
        RECT 5.000 0.000 75.000 3.000 ;
      LAYER Metal4 ;
        RECT 5.000 0.000 75.000 3.000 ;
      LAYER Metal5 ;
        RECT 5.000 0.000 75.000 3.000 ;
      LAYER TopMetal1 ;
        RECT 5.000 0.000 75.000 3.000 ;
      LAYER TopMetal2 ;
        RECT 5.000 0.000 75.000 3.000 ;
    END
    PORT
      LAYER Metal3 ;
        RECT 0.000 7.000 80.000 32.500 ;
    END
    PORT
      LAYER Metal3 ;
        RECT 0.000 126.000 80.000 134.000 ;
    END
    PORT
      LAYER Metal3 ;
        RECT 0.000 34.500 80.000 60.000 ;
    END
    PORT
      LAYER Metal4 ;
        RECT 0.000 7.000 80.000 32.500 ;
    END
    PORT
      LAYER Metal4 ;
        RECT 0.000 126.000 80.000 134.000 ;
    END
    PORT
      LAYER Metal4 ;
        RECT 0.000 34.500 80.000 60.000 ;
    END
    PORT
      LAYER Metal5 ;
        RECT 0.000 7.000 80.000 32.500 ;
    END
    PORT
      LAYER Metal5 ;
        RECT 0.000 126.000 80.000 134.000 ;
    END
    PORT
      LAYER Metal5 ;
        RECT 0.000 34.500 80.000 60.000 ;
    END
    PORT
      LAYER TopMetal1 ;
        RECT 0.000 7.000 80.000 32.500 ;
    END
    PORT
      LAYER TopMetal1 ;
        RECT 0.000 126.000 80.000 134.000 ;
    END
    PORT
      LAYER TopMetal1 ;
        RECT 0.000 34.500 80.000 60.000 ;
    END
    PORT
      LAYER TopMetal2 ;
        RECT 0.000 36.000 80.000 58.500 ;
    END
    PORT
      LAYER TopMetal2 ;
        RECT 0.000 8.500 80.000 31.000 ;
    END
    PORT
      LAYER TopMetal2 ;
        RECT 0.000 127.500 80.000 132.500 ;
    END
  END iovss
  PIN vdd
    DIRECTION INOUT ;
    USE POWER ;
    PORT
      LAYER Metal3 ;
        RECT 0.000 160.000 80.000 178.000 ;
    END
    PORT
      LAYER Metal4 ;
        RECT 0.000 140.000 80.000 155.800 ;
    END
    PORT
      LAYER Metal5 ;
        RECT 0.000 140.000 80.000 158.000 ;
    END
    PORT
      LAYER TopMetal1 ;
        RECT 0.000 140.000 80.000 158.000 ;
    END
  END vdd
  PIN vss
    DIRECTION INOUT ;
    USE GROUND ;
    PORT
      LAYER Metal3 ;
        RECT 0.000 140.000 80.000 158.000 ;
    END
    PORT
      LAYER Metal4 ;
        RECT 0.000 162.200 80.000 178.000 ;
    END
    PORT
      LAYER Metal5 ;
        RECT 0.000 160.000 80.000 178.000 ;
    END
    PORT
      LAYER TopMetal1 ;
        RECT 0.000 160.000 80.000 178.000 ;
    END
  END vss
  OBS
    LAYER Metal1 ;
      RECT 0.000 0.000 80.000 180.000 ;
    LAYER Metal2 ;
      RECT 0.000 0.000 80.000 180.000 ;
    LAYER Metal3 ;
      RECT 0.000 0.000 80.000 178.000 ;
    LAYER Metal4 ;
      RECT 0.000 0.000 80.000 178.000 ;
    LAYER Metal5 ;
      RECT 0.000 0.000 80.000 178.000 ;
    LAYER TopMetal1 ;
      RECT 0.000 0.000 80.000 178.000 ;
    LAYER TopMetal2 ;
      RECT 0.000 0.000 80.000 132.500 ;
    LAYER Via1 ;
      RECT 0.000 0.000 80.000 180.000 ;
    LAYER Via2 ;
      RECT 0.000 0.000 80.000 180.000 ;
  END
END IOPadIOVss

MACRO IOPadIOVdd
  CLASS PAD POWER ;
  ORIGIN 0.000 0.000 ;
  FOREIGN IOPadIOVdd 0.000 0.000 ;
  SIZE 80.000 BY 180.000 ;
  SYMMETRY X Y R90 ;
  SITE IOLibSite ;
  PIN iovdd
    DIRECTION INOUT ;
    USE POWER ;
    PORT
      LAYER Metal2 ;
        RECT 5.000 0.000 75.000 3.000 ;
      LAYER Metal3 ;
        RECT 5.000 0.000 75.000 3.000 ;
      LAYER Metal4 ;
        RECT 5.000 0.000 75.000 3.000 ;
      LAYER Metal5 ;
        RECT 5.000 0.000 75.000 3.000 ;
      LAYER TopMetal1 ;
        RECT 5.000 0.000 75.000 3.000 ;
      LAYER TopMetal2 ;
        RECT 5.000 0.000 75.000 3.000 ;
    END
    PORT
      LAYER Metal3 ;
        RECT 0.000 93.500 80.000 119.000 ;
    END
    PORT
      LAYER Metal3 ;
        RECT 0.000 66.000 80.000 91.500 ;
    END
    PORT
      LAYER Metal4 ;
        RECT 0.000 93.500 80.000 119.000 ;
    END
    PORT
      LAYER Metal4 ;
        RECT 0.000 66.000 80.000 91.500 ;
    END
    PORT
      LAYER Metal5 ;
        RECT 0.000 93.500 80.000 119.000 ;
    END
    PORT
      LAYER Metal5 ;
        RECT 0.000 66.000 80.000 91.500 ;
    END
    PORT
      LAYER TopMetal1 ;
        RECT 0.000 93.500 80.000 119.000 ;
    END
    PORT
      LAYER TopMetal1 ;
        RECT 0.000 66.000 80.000 91.500 ;
    END
    PORT
      LAYER TopMetal2 ;
        RECT 0.000 95.000 80.000 117.500 ;
    END
    PORT
      LAYER TopMetal2 ;
        RECT 0.000 67.500 80.000 90.000 ;
    END
  END iovdd
  PIN iovss
    DIRECTION INOUT ;
    USE GROUND ;
    PORT
      LAYER Metal3 ;
        RECT 0.000 7.000 80.000 32.500 ;
    END
    PORT
      LAYER Metal3 ;
        RECT 0.000 126.000 80.000 134.000 ;
    END
    PORT
      LAYER Metal3 ;
        RECT 0.000 34.500 80.000 60.000 ;
    END
    PORT
      LAYER Metal4 ;
        RECT 0.000 7.000 80.000 32.500 ;
    END
    PORT
      LAYER Metal4 ;
        RECT 0.000 126.000 80.000 134.000 ;
    END
    PORT
      LAYER Metal4 ;
        RECT 0.000 34.500 80.000 60.000 ;
    END
    PORT
      LAYER Metal5 ;
        RECT 0.000 7.000 80.000 32.500 ;
    END
    PORT
      LAYER Metal5 ;
        RECT 0.000 126.000 80.000 134.000 ;
    END
    PORT
      LAYER Metal5 ;
        RECT 0.000 34.500 80.000 60.000 ;
    END
    PORT
      LAYER TopMetal1 ;
        RECT 0.000 7.000 80.000 32.500 ;
    END
    PORT
      LAYER TopMetal1 ;
        RECT 0.000 126.000 80.000 134.000 ;
    END
    PORT
      LAYER TopMetal1 ;
        RECT 0.000 34.500 80.000 60.000 ;
    END
    PORT
      LAYER TopMetal2 ;
        RECT 0.000 36.000 3.900 58.500 ;
    END
    PORT
      LAYER TopMetal2 ;
        RECT 0.000 8.500 3.900 31.000 ;
    END
    PORT
      LAYER TopMetal2 ;
        RECT 76.100 36.000 80.000 58.500 ;
    END
    PORT
      LAYER TopMetal2 ;
        RECT 0.000 127.500 80.000 132.500 ;
    END
    PORT
      LAYER TopMetal2 ;
        RECT 76.100 8.500 80.000 31.000 ;
    END
  END iovss
  PIN vdd
    DIRECTION INOUT ;
    USE POWER ;
    PORT
      LAYER Metal3 ;
        RECT 0.000 160.000 80.000 178.000 ;
    END
    PORT
      LAYER Metal4 ;
        RECT 0.000 140.000 80.000 155.800 ;
    END
    PORT
      LAYER Metal5 ;
        RECT 0.000 140.000 80.000 158.000 ;
    END
    PORT
      LAYER TopMetal1 ;
        RECT 0.000 140.000 80.000 158.000 ;
    END
  END vdd
  PIN vss
    DIRECTION INOUT ;
    USE GROUND ;
    PORT
      LAYER Metal3 ;
        RECT 0.000 140.000 80.000 158.000 ;
    END
    PORT
      LAYER Metal4 ;
        RECT 0.000 162.200 80.000 178.000 ;
    END
    PORT
      LAYER Metal5 ;
        RECT 0.000 160.000 80.000 178.000 ;
    END
    PORT
      LAYER TopMetal1 ;
        RECT 0.000 160.000 80.000 178.000 ;
    END
  END vss
  OBS
    LAYER Metal1 ;
      RECT 0.000 0.000 80.000 180.000 ;
    LAYER Metal2 ;
      RECT 0.000 0.000 80.000 180.000 ;
    LAYER Metal3 ;
      RECT 0.000 0.000 80.000 178.000 ;
    LAYER Metal4 ;
      RECT 0.000 0.000 80.000 178.000 ;
    LAYER Metal5 ;
      RECT 0.000 0.000 80.000 178.000 ;
    LAYER TopMetal1 ;
      RECT 0.000 0.000 80.000 178.000 ;
    LAYER TopMetal2 ;
      RECT 0.000 0.000 80.000 132.500 ;
    LAYER Via1 ;
      RECT 0.000 0.000 80.000 180.000 ;
    LAYER Via2 ;
      RECT 0.000 0.000 80.000 180.000 ;
  END
END IOPadIOVdd

MACRO IOPadVss
  CLASS PAD POWER ;
  ORIGIN 0.000 0.000 ;
  FOREIGN IOPadVss 0.000 0.000 ;
  SIZE 80.000 BY 180.000 ;
  SYMMETRY X Y R90 ;
  SITE IOLibSite ;
  PIN iovdd
    DIRECTION INOUT ;
    USE POWER ;
    PORT
      LAYER Metal3 ;
        RECT 0.000 93.500 80.000 119.000 ;
    END
    PORT
      LAYER Metal3 ;
        RECT 0.000 66.000 80.000 91.500 ;
    END
    PORT
      LAYER Metal4 ;
        RECT 0.000 93.500 80.000 119.000 ;
    END
    PORT
      LAYER Metal4 ;
        RECT 0.000 66.000 80.000 91.500 ;
    END
    PORT
      LAYER Metal5 ;
        RECT 0.000 93.500 80.000 119.000 ;
    END
    PORT
      LAYER Metal5 ;
        RECT 0.000 66.000 80.000 91.500 ;
    END
    PORT
      LAYER TopMetal1 ;
        RECT 0.000 93.500 80.000 119.000 ;
    END
    PORT
      LAYER TopMetal1 ;
        RECT 0.000 66.000 80.000 91.500 ;
    END
    PORT
      LAYER TopMetal2 ;
        RECT 0.000 95.000 80.000 117.500 ;
    END
    PORT
      LAYER TopMetal2 ;
        RECT 0.000 67.500 80.000 90.000 ;
    END
  END iovdd
  PIN iovss
    DIRECTION INOUT ;
    USE GROUND ;
    PORT
      LAYER Metal3 ;
        RECT 0.000 7.000 80.000 32.500 ;
    END
    PORT
      LAYER Metal3 ;
        RECT 0.000 126.000 80.000 134.000 ;
    END
    PORT
      LAYER Metal3 ;
        RECT 0.000 34.500 80.000 60.000 ;
    END
    PORT
      LAYER Metal4 ;
        RECT 0.000 7.000 80.000 32.500 ;
    END
    PORT
      LAYER Metal4 ;
        RECT 0.000 126.000 80.000 134.000 ;
    END
    PORT
      LAYER Metal4 ;
        RECT 0.000 34.500 80.000 60.000 ;
    END
    PORT
      LAYER Metal5 ;
        RECT 0.000 7.000 80.000 32.500 ;
    END
    PORT
      LAYER Metal5 ;
        RECT 0.000 126.000 80.000 134.000 ;
    END
    PORT
      LAYER Metal5 ;
        RECT 0.000 34.500 80.000 60.000 ;
    END
    PORT
      LAYER TopMetal1 ;
        RECT 0.000 7.000 80.000 32.500 ;
    END
    PORT
      LAYER TopMetal1 ;
        RECT 0.000 126.000 80.000 134.000 ;
    END
    PORT
      LAYER TopMetal1 ;
        RECT 0.000 34.500 80.000 60.000 ;
    END
    PORT
      LAYER TopMetal2 ;
        RECT 0.000 36.000 80.000 58.500 ;
    END
    PORT
      LAYER TopMetal2 ;
        RECT 0.000 8.500 80.000 31.000 ;
    END
    PORT
      LAYER TopMetal2 ;
        RECT 0.000 127.500 80.000 132.500 ;
    END
  END iovss
  PIN vdd
    DIRECTION INOUT ;
    USE POWER ;
    PORT
      LAYER Metal3 ;
        RECT 0.000 160.000 80.000 178.000 ;
    END
    PORT
      LAYER Metal4 ;
        RECT 0.000 140.000 80.000 155.800 ;
    END
    PORT
      LAYER Metal5 ;
        RECT 0.000 140.000 80.000 158.000 ;
    END
    PORT
      LAYER TopMetal1 ;
        RECT 0.000 140.000 80.000 158.000 ;
    END
  END vdd
  PIN vss
    DIRECTION INOUT ;
    USE GROUND ;
    PORT
      LAYER Metal2 ;
        RECT 5.000 0.000 75.000 3.000 ;
      LAYER Metal3 ;
        RECT 5.000 0.000 75.000 3.000 ;
      LAYER Metal4 ;
        RECT 5.000 0.000 75.000 3.000 ;
      LAYER Metal5 ;
        RECT 5.000 0.000 75.000 3.000 ;
      LAYER TopMetal1 ;
        RECT 5.000 0.000 75.000 3.000 ;
      LAYER TopMetal2 ;
        RECT 5.000 0.000 75.000 3.000 ;
    END
    PORT
      LAYER Metal3 ;
        RECT 0.000 140.000 80.000 158.000 ;
    END
    PORT
      LAYER Metal4 ;
        RECT 0.000 162.200 80.000 178.000 ;
    END
    PORT
      LAYER Metal5 ;
        RECT 0.000 160.000 80.000 178.000 ;
    END
    PORT
      LAYER TopMetal1 ;
        RECT 0.000 160.000 80.000 178.000 ;
    END
  END vss
  OBS
    LAYER Metal1 ;
      RECT 0.000 0.000 80.000 180.000 ;
    LAYER Metal2 ;
      RECT 0.000 0.000 80.000 180.000 ;
    LAYER Metal3 ;
      RECT 0.000 0.000 80.000 178.000 ;
    LAYER Metal4 ;
      RECT 0.000 0.000 80.000 178.000 ;
    LAYER Metal5 ;
      RECT 0.000 0.000 80.000 178.000 ;
    LAYER TopMetal1 ;
      RECT 0.000 0.000 80.000 178.000 ;
    LAYER TopMetal2 ;
      RECT 0.000 0.000 80.000 132.500 ;
    LAYER Via1 ;
      RECT 0.000 0.000 80.000 180.000 ;
    LAYER Via2 ;
      RECT 0.000 0.000 80.000 180.000 ;
  END
END IOPadVss

MACRO IOPadVdd
  CLASS PAD POWER ;
  ORIGIN 0.000 0.000 ;
  FOREIGN IOPadVdd 0.000 0.000 ;
  SIZE 80.000 BY 180.000 ;
  SYMMETRY X Y R90 ;
  SITE IOLibSite ;
  PIN iovdd
    DIRECTION INOUT ;
    USE POWER ;
    PORT
      LAYER Metal3 ;
        RECT 0.000 93.500 80.000 119.000 ;
    END
    PORT
      LAYER Metal3 ;
        RECT 0.000 66.000 80.000 91.500 ;
    END
    PORT
      LAYER Metal4 ;
        RECT 0.000 93.500 80.000 119.000 ;
    END
    PORT
      LAYER Metal4 ;
        RECT 0.000 66.000 80.000 91.500 ;
    END
    PORT
      LAYER Metal5 ;
        RECT 0.000 93.500 80.000 119.000 ;
    END
    PORT
      LAYER Metal5 ;
        RECT 0.000 66.000 80.000 91.500 ;
    END
    PORT
      LAYER TopMetal1 ;
        RECT 0.000 93.500 80.000 119.000 ;
    END
    PORT
      LAYER TopMetal1 ;
        RECT 0.000 66.000 80.000 91.500 ;
    END
    PORT
      LAYER TopMetal2 ;
        RECT 76.100 67.500 80.000 90.000 ;
    END
    PORT
      LAYER TopMetal2 ;
        RECT 76.100 95.000 80.000 117.500 ;
    END
    PORT
      LAYER TopMetal2 ;
        RECT 0.000 95.000 3.900 117.500 ;
    END
    PORT
      LAYER TopMetal2 ;
        RECT 0.000 67.500 3.900 90.000 ;
    END
  END iovdd
  PIN iovss
    DIRECTION INOUT ;
    USE GROUND ;
    PORT
      LAYER Metal3 ;
        RECT 0.000 7.000 80.000 32.500 ;
    END
    PORT
      LAYER Metal3 ;
        RECT 0.000 126.000 80.000 134.000 ;
    END
    PORT
      LAYER Metal3 ;
        RECT 0.000 34.500 80.000 60.000 ;
    END
    PORT
      LAYER Metal4 ;
        RECT 0.000 7.000 80.000 32.500 ;
    END
    PORT
      LAYER Metal4 ;
        RECT 0.000 126.000 80.000 134.000 ;
    END
    PORT
      LAYER Metal4 ;
        RECT 0.000 34.500 80.000 60.000 ;
    END
    PORT
      LAYER Metal5 ;
        RECT 0.000 7.000 80.000 32.500 ;
    END
    PORT
      LAYER Metal5 ;
        RECT 0.000 126.000 80.000 134.000 ;
    END
    PORT
      LAYER Metal5 ;
        RECT 0.000 34.500 80.000 60.000 ;
    END
    PORT
      LAYER TopMetal1 ;
        RECT 0.000 7.000 80.000 32.500 ;
    END
    PORT
      LAYER TopMetal1 ;
        RECT 0.000 126.000 80.000 134.000 ;
    END
    PORT
      LAYER TopMetal1 ;
        RECT 0.000 34.500 80.000 60.000 ;
    END
    PORT
      LAYER TopMetal2 ;
        RECT 0.000 36.000 3.900 58.500 ;
    END
    PORT
      LAYER TopMetal2 ;
        RECT 0.000 8.500 3.900 31.000 ;
    END
    PORT
      LAYER TopMetal2 ;
        RECT 76.100 127.500 80.000 132.500 ;
    END
    PORT
      LAYER TopMetal2 ;
        RECT 76.100 36.000 80.000 58.500 ;
    END
    PORT
      LAYER TopMetal2 ;
        RECT 76.100 8.500 80.000 31.000 ;
    END
    PORT
      LAYER TopMetal2 ;
        RECT 0.000 127.500 3.900 132.500 ;
    END
  END iovss
  PIN vdd
    DIRECTION INOUT ;
    USE POWER ;
    PORT
      LAYER Metal2 ;
        RECT 5.000 0.000 75.000 3.000 ;
      LAYER Metal3 ;
        RECT 5.000 0.000 75.000 3.000 ;
      LAYER Metal4 ;
        RECT 5.000 0.000 75.000 3.000 ;
      LAYER Metal5 ;
        RECT 5.000 0.000 75.000 3.000 ;
      LAYER TopMetal1 ;
        RECT 5.000 0.000 75.000 3.000 ;
      LAYER TopMetal2 ;
        RECT 5.000 0.000 75.000 3.000 ;
    END
    PORT
      LAYER Metal3 ;
        RECT 0.000 160.000 80.000 178.000 ;
    END
    PORT
      LAYER Metal4 ;
        RECT 0.000 140.000 80.000 155.800 ;
    END
    PORT
      LAYER Metal5 ;
        RECT 0.000 140.000 80.000 158.000 ;
    END
    PORT
      LAYER TopMetal1 ;
        RECT 0.000 140.000 80.000 158.000 ;
    END
    PORT
      LAYER TopMetal2 ;
        RECT 7.500 141.500 72.500 156.500 ;
    END
  END vdd
  PIN vss
    DIRECTION INOUT ;
    USE GROUND ;
    PORT
      LAYER Metal3 ;
        RECT 0.000 140.000 80.000 158.000 ;
    END
    PORT
      LAYER Metal4 ;
        RECT 0.000 162.200 80.000 178.000 ;
    END
    PORT
      LAYER Metal5 ;
        RECT 0.000 160.000 80.000 178.000 ;
    END
    PORT
      LAYER TopMetal1 ;
        RECT 0.000 160.000 80.000 178.000 ;
    END
  END vss
  OBS
    LAYER Metal1 ;
      RECT 0.000 0.000 80.000 180.000 ;
    LAYER Metal2 ;
      RECT 0.000 0.000 80.000 180.000 ;
    LAYER Metal3 ;
      RECT 0.000 0.000 80.000 178.000 ;
    LAYER Metal4 ;
      RECT 0.000 0.000 80.000 178.000 ;
    LAYER Metal5 ;
      RECT 0.000 0.000 80.000 178.000 ;
    LAYER TopMetal1 ;
      RECT 0.000 0.000 80.000 178.000 ;
    LAYER TopMetal2 ;
      RECT 0.000 0.000 80.000 156.500 ;
    LAYER Via1 ;
      RECT 0.000 0.000 80.000 180.000 ;
    LAYER Via2 ;
      RECT 0.000 0.000 80.000 180.000 ;
  END
END IOPadVdd
